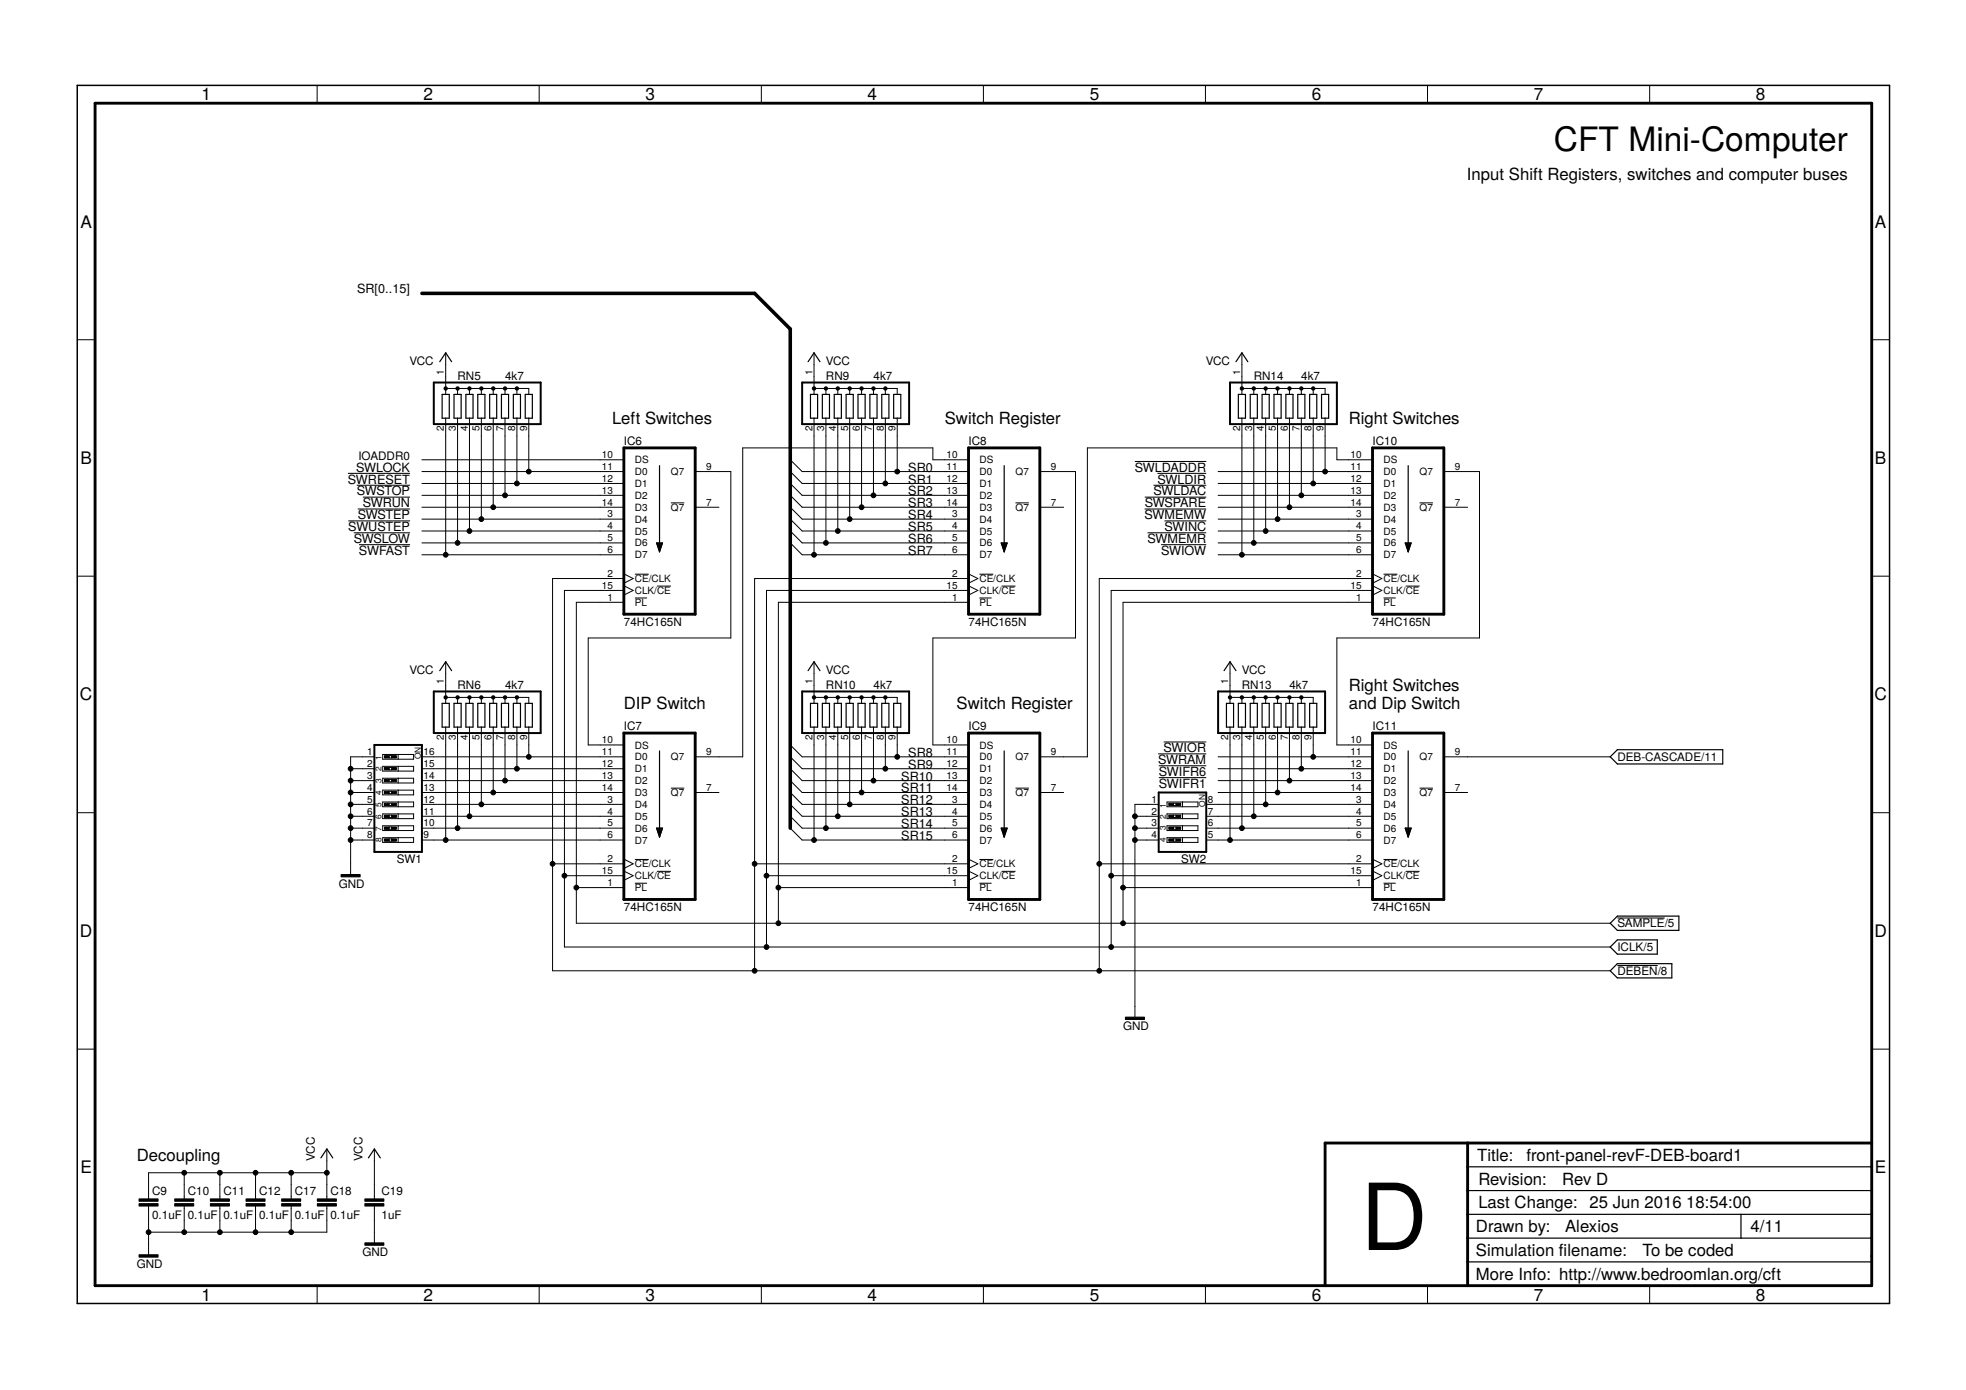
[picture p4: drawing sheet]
<svg xmlns="http://www.w3.org/2000/svg" width="420mm" height="297mm" viewBox="0 0 420 297" stroke-linecap="round" stroke-linejoin="round" font-family="sans-serif">
<defs><g id="words">
<text font-size="19.7" x="290.8" y="267.1">D</text>
<text font-size="7.2" x="332.1" y="32.2">CFT Mini-Computer</text>
<g font-size="3.7">
<text x="43" y="21.4">1</text>
<text x="90.5" y="21.4">2</text>
<text x="138" y="21.4">3</text>
<text x="185.4" y="21.4">4</text>
<text x="232.9" y="21.4">5</text>
<text x="280.3" y="21.4">6</text>
<text x="327.8" y="21.4">7</text>
<text x="375.3" y="21.4">8</text>
<text x="17.2" y="48.6">A</text>
<text x="400.7" y="48.6">A</text>
<text x="17.2" y="99.2">B</text>
<text x="400.7" y="99.2">B</text>
<text x="17.1" y="149.7">C</text>
<text x="400.6" y="149.7">C</text>
<text x="17.1" y="200.2">D</text>
<text x="400.6" y="200.2">D</text>
<text x="17.2" y="250.8">E</text>
<text x="400.7" y="250.8">E</text>
<text x="43" y="277.9">1</text>
<text x="90.5" y="277.9">2</text>
<text x="138" y="277.9">3</text>
<text x="185.4" y="277.9">4</text>
<text x="232.9" y="277.9">5</text>
<text x="280.3" y="277.9">6</text>
<text x="327.8" y="277.9">7</text>
<text x="375.3" y="277.9">8</text>
</g>
<g font-size="3.6">
<text x="313.5" y="38.6">Input Shift Registers, switches and computer buses</text>
<text x="130.8" y="90.6">Left Switches</text>
<text x="201.9" y="90.6">Switch Register</text>
<text x="288.3" y="90.6">Right Switches</text>
<text x="288.3" y="147.8">Right Switches</text>
<text x="133.3" y="151.6">DIP Switch</text>
<text x="204.4" y="151.6">Switch Register</text>
<text x="288.3" y="151.6">and Dip Switch</text>
<text x="29.2" y="248.1">Decoupling</text>
<text x="315.7" y="248.1">Title:</text>
<text x="326.2" y="248.2">front-panel-revF-DEB-board1</text>
<text x="315.9" y="253.2">Revision:</text>
<text x="333.8" y="253.3">Rev D</text>
<text x="315.4" y="263.3">Drawn by:</text>
<text x="315.9" y="258.2">Last Change: 25 Jun 2016</text>
<text x="334.5" y="263.3">Alexios</text>
<text x="360.4" y="258.1">18:54:00</text>
<text x="374.1" y="263.2">4/11</text>
<text x="315.4" y="268.4">Simulation flename:</text>
<text x="333.2" y="268.4">i</text>
<text x="351" y="268.4">To be coded</text>
<text x="315.4" y="273.5">More Info: http://www.bedroomlan.org/cft</text>
</g>
<g font-size="2.7">
<text x="76.3" y="62.7">SR[0..15]</text>
<text x="76.1" y="100.8">SWLOCK</text>
<text x="194.1" y="100.8">SR0</text>
<text x="242.5" y="100.8">SWLDADDR</text>
<text x="74.4" y="103.3">SWRESET</text>
<text x="76.2" y="105.9">SWSTOP</text>
<text x="194.1" y="103.3">SR1</text>
<text x="194.1" y="105.9">SR2</text>
<text x="246.5" y="105.9">SWLDAC</text>
<text x="247.3" y="103.3">SWLDIR</text>
<text x="74.4" y="113.5">SWUSTEP</text>
<text x="76.4" y="110.9">SWSTEP</text>
<text x="77.5" y="108.4">SWRUN</text>
<text x="194.1" y="108.4">SR3</text>
<text x="194.1" y="110.9">SR4</text>
<text x="194.1" y="113.5">SR5</text>
<text x="244.6" y="110.9">SWMEMW</text>
<text x="244.6" y="108.4">SWSPARE</text>
<text x="248.8" y="113.5">SWINC</text>
<text x="75.6" y="116">SWSLOW</text>
<text x="76.7" y="118.6">SWFAST</text>
<text x="194.1" y="116">SR6</text>
<text x="194.1" y="118.6">SR7</text>
<text x="245.2" y="116">SWMEMR</text>
<text x="248.1" y="118.6">SWIOW</text>
<text x="194.1" y="161.7">SR8</text>
<text x="248.7" y="160.7">SWIOR</text>
<text x="192.6" y="166.8">SR10</text>
<text x="194.1" y="164.3">SR9</text>
<text x="247.5" y="163.3">SWRAM</text>
<text x="247.6" y="165.8">SWIFR6</text>
<text x="192.6" y="169.4">SR11</text>
<text x="192.6" y="171.9">SR12</text>
<text x="247.6" y="168.3">SWIFR1</text>
<text x="192.6" y="174.4">SR13</text>
<text x="192.6" y="177">SR14</text>
<text x="192.6" y="179.5">SR15</text>
</g>
<g font-size="2.5">
<text x="87.5" y="77.9">VCC</text>
<text x="176.5" y="77.9">VCC</text>
<text x="257.7" y="77.9">VCC</text>
<text x="97.8" y="81.1">RN5</text>
<text x="107.9" y="81.1">4k7</text>
<text x="176.5" y="81.1">RN9</text>
<text x="186.7" y="81.1">4k7</text>
<text x="267.9" y="81.1">RN14</text>
<text x="278.1" y="81.1">4k7</text>
<text x="133.3" y="95.1">IC6</text>
<text x="207" y="95.1">IC8</text>
<text x="293.3" y="95.1">IC10</text>
<text x="76.6" y="98.2">IOADDR0</text>
<text x="133.3" y="133.8">74HC165N</text>
<text x="207" y="133.8">74HC165N</text>
<text x="293.3" y="133.8">74HC165N</text>
<text x="87.5" y="144">VCC</text>
<text x="176.5" y="144">VCC</text>
<text x="265.4" y="144">VCC</text>
<text x="97.8" y="147.1">RN6</text>
<text x="107.9" y="147.1">4k7</text>
<text x="176.5" y="147.1">RN10</text>
<text x="186.7" y="147.1">4k7</text>
<text x="265.4" y="147.1">RN13</text>
<text x="275.6" y="147.1">4k7</text>
<text x="133.3" y="156">IC7</text>
<text x="207" y="156">IC9</text>
<text x="293.3" y="156">IC11</text>
<text x="345.7" y="162.6">DEB-CASCADE/11</text>
<text x="84.8" y="184.5">SW1</text>
<text x="252.4" y="184.5">SW2</text>
<text x="72.4" y="189.7">GND</text>
<text x="133.3" y="194.7">74HC165N</text>
<text x="207" y="194.7">74HC165N</text>
<text x="293.3" y="194.7">74HC165N</text>
<text x="345.7" y="203.3">ICLK/5</text>
<text x="345.7" y="198.2">SAMPLE/5</text>
<text x="345.7" y="208.3">DEBEN/8</text>
<text x="240" y="220.1">GND</text>
<text x="67.3" y="248.1" transform="rotate(-90 67.3 248.1)">VCC</text>
<text x="77.5" y="248.1" transform="rotate(-90 77.5 248.1)">VCC</text>
<text x="32.5" y="255.3">C9</text>
<text x="40.1" y="255.3">C10</text>
<text x="47.7" y="255.3">C11</text>
<text x="55.4" y="255.3">C12</text>
<text x="63" y="255.3">C17</text>
<text x="70.6" y="255.3">C18</text>
<text x="81.5" y="255.3">C19</text>
<text x="32.5" y="260.4">0.1uF</text>
<text x="40.1" y="260.4">0.1uF</text>
<text x="47.7" y="260.4">0.1uF</text>
<text x="55.4" y="260.4">0.1uF</text>
<text x="63" y="260.4">0.1uF</text>
<text x="70.6" y="260.4">0.1uF</text>
<text x="81.5" y="260.4">1uF</text>
<text x="77.5" y="268.4">GND</text>
<text x="29.2" y="270.9">GND</text>
</g>
<g font-size="2.1">
<text x="94.9" y="80.1" transform="rotate(-90 94.9 80.1)">1</text>
<text x="173.6" y="80.1" transform="rotate(-90 173.6 80.1)">1</text>
<text x="265" y="80.1" transform="rotate(-90 265 80.1)">1</text>
<text x="94.9" y="92.2" transform="rotate(-90 94.9 92.2)">2</text>
<text x="97.4" y="92.2" transform="rotate(-90 97.4 92.2)">3</text>
<text x="100" y="92.2" transform="rotate(-90 100 92.2)">4</text>
<text x="102.5" y="92.2" transform="rotate(-90 102.5 92.2)">5</text>
<text x="105" y="92.2" transform="rotate(-90 105 92.2)">6</text>
<text x="107.6" y="92.2" transform="rotate(-90 107.6 92.2)">7</text>
<text x="110.1" y="92.2" transform="rotate(-90 110.1 92.2)">8</text>
<text x="112.7" y="92.2" transform="rotate(-90 112.7 92.2)">9</text>
<text x="173.6" y="92.2" transform="rotate(-90 173.6 92.2)">2</text>
<text x="176.2" y="92.2" transform="rotate(-90 176.2 92.2)">3</text>
<text x="178.7" y="92.2" transform="rotate(-90 178.7 92.2)">4</text>
<text x="181.2" y="92.2" transform="rotate(-90 181.2 92.2)">5</text>
<text x="183.8" y="92.2" transform="rotate(-90 183.8 92.2)">6</text>
<text x="186.3" y="92.2" transform="rotate(-90 186.3 92.2)">7</text>
<text x="188.9" y="92.2" transform="rotate(-90 188.9 92.2)">8</text>
<text x="191.4" y="92.2" transform="rotate(-90 191.4 92.2)">9</text>
<text x="265" y="92.2" transform="rotate(-90 265 92.2)">2</text>
<text x="267.6" y="92.2" transform="rotate(-90 267.6 92.2)">3</text>
<text x="270.1" y="92.2" transform="rotate(-90 270.1 92.2)">4</text>
<text x="272.7" y="92.2" transform="rotate(-90 272.7 92.2)">5</text>
<text x="275.2" y="92.2" transform="rotate(-90 275.2 92.2)">6</text>
<text x="277.7" y="92.2" transform="rotate(-90 277.7 92.2)">7</text>
<text x="280.3" y="92.2" transform="rotate(-90 280.3 92.2)">8</text>
<text x="282.8" y="92.2" transform="rotate(-90 282.8 92.2)">9</text>
<text x="128.6" y="97.9">10</text>
<text x="128.6" y="100.4">11</text>
<text x="135.7" y="99">DS</text>
<text x="135.7" y="101.5">D0</text>
<text x="143.4" y="101.5">Q7</text>
<text x="150.9" y="100.4">9</text>
<text x="202.3" y="97.9">10</text>
<text x="202.3" y="100.4">11</text>
<text x="209.3" y="99">DS</text>
<text x="209.3" y="101.5">D0</text>
<text x="217" y="101.5">Q7</text>
<text x="224.6" y="100.4">9</text>
<text x="288.6" y="97.9">10</text>
<text x="288.6" y="100.4">11</text>
<text x="295.7" y="99">DS</text>
<text x="295.7" y="101.5">D0</text>
<text x="303.4" y="101.5">Q7</text>
<text x="310.9" y="100.4">9</text>
<text x="128.6" y="103">12</text>
<text x="128.6" y="105.5">13</text>
<text x="135.7" y="104.1">D1</text>
<text x="135.7" y="106.6">D2</text>
<text x="202.3" y="103">12</text>
<text x="202.3" y="105.5">13</text>
<text x="209.3" y="104.1">D1</text>
<text x="209.3" y="106.6">D2</text>
<text x="288.6" y="103">12</text>
<text x="288.6" y="105.5">13</text>
<text x="295.7" y="104.1">D1</text>
<text x="295.7" y="106.6">D2</text>
<text x="128.6" y="108">14</text>
<text x="129.8" y="110.6">3</text>
<text x="129.8" y="113.1">4</text>
<text x="135.7" y="111.7">D4</text>
<text x="135.7" y="109.2">D3</text>
<text x="143.4" y="109.2">Q7</text>
<text x="150.9" y="108">7</text>
<text x="202.3" y="108">14</text>
<text x="203.5" y="110.6">3</text>
<text x="203.5" y="113.1">4</text>
<text x="209.3" y="111.7">D4</text>
<text x="209.3" y="109.2">D3</text>
<text x="217" y="109.2">Q7</text>
<text x="224.6" y="108">7</text>
<text x="288.6" y="108">14</text>
<text x="289.8" y="110.6">3</text>
<text x="289.8" y="113.1">4</text>
<text x="295.7" y="111.7">D4</text>
<text x="295.7" y="109.2">D3</text>
<text x="303.4" y="109.2">Q7</text>
<text x="310.9" y="108">7</text>
<text x="129.8" y="115.7">5</text>
<text x="129.8" y="118.2">6</text>
<text x="135.7" y="114.2">D5</text>
<text x="135.7" y="116.8">D6</text>
<text x="135.7" y="119.3">D7</text>
<text x="203.5" y="115.7">5</text>
<text x="203.5" y="118.2">6</text>
<text x="209.3" y="114.2">D5</text>
<text x="209.3" y="116.8">D6</text>
<text x="209.3" y="119.3">D7</text>
<text x="289.8" y="115.7">5</text>
<text x="289.8" y="118.2">6</text>
<text x="295.7" y="114.2">D5</text>
<text x="295.7" y="116.8">D6</text>
<text x="295.7" y="119.3">D7</text>
<text x="128.6" y="125.8">15</text>
<text x="129.8" y="123.3">2</text>
<text x="135.7" y="124.4">CE/CLK</text>
<text x="202.3" y="125.8">15</text>
<text x="203.5" y="123.3">2</text>
<text x="209.3" y="124.4">CE/CLK</text>
<text x="288.6" y="125.8">15</text>
<text x="289.8" y="123.3">2</text>
<text x="295.7" y="124.4">CE/CLK</text>
<text x="129.8" y="128.4">1</text>
<text x="135.7" y="129.5">PL</text>
<text x="135.7" y="126.9">CLK/CE</text>
<text x="203.5" y="128.4">1</text>
<text x="209.3" y="129.5">PL</text>
<text x="209.3" y="126.9">CLK/CE</text>
<text x="289.8" y="128.4">1</text>
<text x="295.7" y="129.5">PL</text>
<text x="295.7" y="126.9">CLK/CE</text>
<text x="94.9" y="146.1" transform="rotate(-90 94.9 146.1)">1</text>
<text x="173.6" y="146.1" transform="rotate(-90 173.6 146.1)">1</text>
<text x="262.5" y="146.1" transform="rotate(-90 262.5 146.1)">1</text>
<text x="78.5" y="161.4">1</text>
<text x="90.5" y="161.4">16</text>
<text x="94.9" y="158.2" transform="rotate(-90 94.9 158.2)">2</text>
<text x="97.4" y="158.2" transform="rotate(-90 97.4 158.2)">3</text>
<text x="100" y="158.2" transform="rotate(-90 100 158.2)">4</text>
<text x="102.5" y="158.2" transform="rotate(-90 102.5 158.2)">5</text>
<text x="105" y="158.2" transform="rotate(-90 105 158.2)">6</text>
<text x="107.6" y="158.2" transform="rotate(-90 107.6 158.2)">7</text>
<text x="110.1" y="158.2" transform="rotate(-90 110.1 158.2)">8</text>
<text x="112.7" y="158.2" transform="rotate(-90 112.7 158.2)">9</text>
<text x="128.6" y="158.8">10</text>
<text x="128.6" y="161.4">11</text>
<text x="135.7" y="160">DS</text>
<text x="150.9" y="161.4">9</text>
<text x="173.6" y="158.2" transform="rotate(-90 173.6 158.2)">2</text>
<text x="176.2" y="158.2" transform="rotate(-90 176.2 158.2)">3</text>
<text x="178.7" y="158.2" transform="rotate(-90 178.7 158.2)">4</text>
<text x="181.2" y="158.2" transform="rotate(-90 181.2 158.2)">5</text>
<text x="183.8" y="158.2" transform="rotate(-90 183.8 158.2)">6</text>
<text x="186.3" y="158.2" transform="rotate(-90 186.3 158.2)">7</text>
<text x="188.9" y="158.2" transform="rotate(-90 188.9 158.2)">8</text>
<text x="191.4" y="158.2" transform="rotate(-90 191.4 158.2)">9</text>
<text x="202.3" y="158.8">10</text>
<text x="202.3" y="161.4">11</text>
<text x="209.3" y="160">DS</text>
<text x="224.6" y="161.4">9</text>
<text x="262.5" y="158.2" transform="rotate(-90 262.5 158.2)">2</text>
<text x="265" y="158.2" transform="rotate(-90 265 158.2)">3</text>
<text x="267.6" y="158.2" transform="rotate(-90 267.6 158.2)">4</text>
<text x="270.1" y="158.2" transform="rotate(-90 270.1 158.2)">5</text>
<text x="272.7" y="158.2" transform="rotate(-90 272.7 158.2)">6</text>
<text x="275.2" y="158.2" transform="rotate(-90 275.2 158.2)">7</text>
<text x="277.7" y="158.2" transform="rotate(-90 277.7 158.2)">8</text>
<text x="280.3" y="158.2" transform="rotate(-90 280.3 158.2)">9</text>
<text x="288.6" y="158.8">10</text>
<text x="288.6" y="161.4">11</text>
<text x="295.7" y="160">DS</text>
<text x="310.9" y="161.4">9</text>
<text x="78.5" y="163.9">2</text>
<text x="78.5" y="166.5">3</text>
<text x="90.5" y="166.5">14</text>
<text x="90.5" y="163.9">15</text>
<text x="128.6" y="163.9">12</text>
<text x="128.6" y="166.5">13</text>
<text x="135.7" y="162.5">D0</text>
<text x="135.7" y="165">D1</text>
<text x="135.7" y="167.6">D2</text>
<text x="143.4" y="162.5">Q7</text>
<text x="202.3" y="163.9">12</text>
<text x="202.3" y="166.5">13</text>
<text x="209.3" y="162.5">D0</text>
<text x="209.3" y="165">D1</text>
<text x="209.3" y="167.6">D2</text>
<text x="217" y="162.5">Q7</text>
<text x="288.6" y="163.9">12</text>
<text x="288.6" y="166.5">13</text>
<text x="295.7" y="162.5">D0</text>
<text x="295.7" y="165">D1</text>
<text x="295.7" y="167.6">D2</text>
<text x="303.4" y="162.5">Q7</text>
<text x="78.5" y="169">4</text>
<text x="78.5" y="171.5">5</text>
<text x="90.5" y="171.5">12</text>
<text x="90.5" y="169">13</text>
<text x="128.6" y="169">14</text>
<text x="129.8" y="171.5">3</text>
<text x="135.7" y="172.7">D4</text>
<text x="135.7" y="170.1">D3</text>
<text x="143.4" y="170.1">Q7</text>
<text x="150.9" y="169">7</text>
<text x="202.3" y="169">14</text>
<text x="203.5" y="171.5">3</text>
<text x="209.3" y="172.7">D4</text>
<text x="209.3" y="170.1">D3</text>
<text x="217" y="170.1">Q7</text>
<text x="224.6" y="169">7</text>
<text x="246.1" y="171.5">1</text>
<text x="258.1" y="171.5">8</text>
<text x="288.6" y="169">14</text>
<text x="289.8" y="171.5">3</text>
<text x="295.7" y="172.7">D4</text>
<text x="295.7" y="170.1">D3</text>
<text x="303.4" y="170.1">Q7</text>
<text x="310.9" y="169">7</text>
<text x="78.5" y="174.1">6</text>
<text x="78.5" y="176.6">7</text>
<text x="78.5" y="179.2">8</text>
<text x="90.5" y="179.2">9</text>
<text x="90.5" y="176.6">10</text>
<text x="90.5" y="174.1">11</text>
<text x="129.8" y="174.1">4</text>
<text x="129.8" y="176.6">5</text>
<text x="129.8" y="179.2">6</text>
<text x="135.7" y="175.2">D5</text>
<text x="135.7" y="177.7">D6</text>
<text x="203.5" y="174.1">4</text>
<text x="203.5" y="176.6">5</text>
<text x="203.5" y="179.2">6</text>
<text x="209.3" y="175.2">D5</text>
<text x="209.3" y="177.7">D6</text>
<text x="246.1" y="174.1">2</text>
<text x="246.1" y="176.6">3</text>
<text x="246.1" y="179.2">4</text>
<text x="258.1" y="179.2">5</text>
<text x="258.1" y="176.6">6</text>
<text x="258.1" y="174.1">7</text>
<text x="289.8" y="174.1">4</text>
<text x="289.8" y="176.6">5</text>
<text x="289.8" y="179.2">6</text>
<text x="295.7" y="175.2">D5</text>
<text x="295.7" y="177.7">D6</text>
<text x="129.8" y="184.2">2</text>
<text x="135.7" y="185.4">CE/CLK</text>
<text x="135.7" y="180.3">D7</text>
<text x="203.5" y="184.2">2</text>
<text x="209.3" y="185.4">CE/CLK</text>
<text x="209.3" y="180.3">D7</text>
<text x="289.8" y="184.2">2</text>
<text x="295.7" y="185.4">CE/CLK</text>
<text x="295.7" y="180.3">D7</text>
<text x="128.6" y="186.8">15</text>
<text x="129.8" y="189.3">1</text>
<text x="135.7" y="190.4">PL</text>
<text x="135.7" y="187.9">CLK/CE</text>
<text x="202.3" y="186.8">15</text>
<text x="203.5" y="189.3">1</text>
<text x="209.3" y="190.4">PL</text>
<text x="209.3" y="187.9">CLK/CE</text>
<text x="288.6" y="186.8">15</text>
<text x="289.8" y="189.3">1</text>
<text x="295.7" y="190.4">PL</text>
<text x="295.7" y="187.9">CLK/CE</text>
</g>
<g font-size="1.8">
<text x="81.5" y="167.3" transform="rotate(-90 81.5 167.3)">3</text>
<text x="81.5" y="164.8" transform="rotate(-90 81.5 164.8)">2</text>
<text x="81.5" y="162.5" transform="rotate(-90 81.5 162.5)">1</text>
<text x="89.9" y="162.2" transform="rotate(-90 89.9 162.2)">ON</text>
<text x="81.5" y="172.5" transform="rotate(-90 81.5 172.5)">5</text>
<text x="81.5" y="169.8" transform="rotate(-90 81.5 169.8)">4</text>
<text x="249.1" y="172.6" transform="rotate(-90 249.1 172.6)">1</text>
<text x="257.5" y="172.4" transform="rotate(-90 257.5 172.4)">ON</text>
<text x="81.5" y="180" transform="rotate(-90 81.5 180)">8</text>
<text x="81.5" y="177.6" transform="rotate(-90 81.5 177.6)">7</text>
<text x="81.5" y="175" transform="rotate(-90 81.5 175)">6</text>
<text x="249.1" y="180" transform="rotate(-90 249.1 180)">4</text>
<text x="249.1" y="177.5" transform="rotate(-90 249.1 177.5)">3</text>
<text x="249.1" y="174.9" transform="rotate(-90 249.1 174.9)">2</text>
</g>
</g></defs>
<g fill="none" stroke="#000" stroke-width=".21">
<path d="M67.8 18.2v3.9M115.2 18.2v3.9M162.7 18.2v3.9M210.2 18.2v3.9M257.6 18.2v3.9M305.1 18.2v3.9M352.6 18.2v3.9M20.3 22.1h379.7v252.6h-379.7zM16.5 72.6h3.8M95.2 75.4v8.9M174 75.4v8.9M265.4 75.4v8.9"/>
<path d="M400 72.6h3.8M90.2 98.3h43.1M95.2 89.4v29.2M95.2 83h17.8v1.3M97.8 83v1.3M97.8 89.4v26.6M100.3 83v1.3M100.3 89.4v24.1M102.9 83v1.3M102.9 89.4v21.5M105.4 83v1.3M105.4 89.4v19"/>
<path d="M107.9 83v1.3M107.9 89.4v16.5M110.5 83v1.3M110.5 89.4v13.9M113 89.4v11.4M168.9 98.3l2.5 2.5h35.6M174 83h17.7v1.3M174 89.4v29.2M176.5 83v1.3M176.5 89.4v26.6M179 83v1.3M179 89.4v24.1"/>
<path d="M181.6 83v1.3M181.6 89.4v21.5M184.1 83v1.3M184.1 89.4v19M186.7 83v1.3M186.7 89.4v16.5M189.2 83v1.3M189.2 89.4v13.9M191.7 89.4v11.4M207 98.3h-7.6v-2.6h-40.7v66h-10.1M242.5 98.6h15.3M265.4 83h17.8v1.3"/>
<path d="M265.4 89.4v29.2M267.9 83v1.3M267.9 89.4v26.6M270.5 83v1.3M270.5 89.4v24.1M273 83v1.3M273 89.4v21.5M275.6 83v1.3M275.6 89.4v19M278.1 83v1.3M278.1 89.4v16.5M280.6 83v1.3"/>
<path d="M280.6 89.4v13.9M283.2 89.4v11.4M293.3 98.3h-7.6v-2.6h-53.3v66h-10.2M74.4 101.2h13.2M74.4 111.3h13.2M75.6 113.9h12M76.2 103.7h11.4M76.5 108.8h11.1M76.7 116.4h10.9M77.6 106.2h10M90.2 110.9h43.1M90.2 113.5h43.1"/>
<path d="M90.2 116h43.1M90.2 118.6h43.1M90.2 108.4h43.1M90.2 100.8h43.1M90.2 103.3h43.1M90.2 105.9h43.1M143.4 107.5h2.8M148.6 108.4h5M148.6 100.8h7.6v35.5h-30.5v22.9h7.6M168.9 108.4l2.5 2.5h35.6M168.9 110.9l2.5 2.6h35.6M168.9 113.5l2.5 2.5h35.6"/>
<path d="M168.9 116l2.5 2.6h35.6M168.9 105.9l2.5 2.5h35.6M168.9 100.8l2.5 2.5h35.6M168.9 103.3l2.5 2.6h35.6M217 107.5h2.9M222.2 108.4h5.1M222.2 100.8h7.6v35.5h-30.4v22.9h7.6M244.6 108.8h13.2M244.6 106.2h13.2M245.2 113.9h12.6M246.5 103.7h11.3M247.4 101.2h10.4"/>
<path d="M248.1 116.4h9.7M248.9 111.3h8.9M260.3 110.9h33M260.3 113.5h33M260.3 116h33M260.3 118.6h33M260.3 108.4h33M260.3 100.8h33M260.3 103.3h33M260.3 105.9h33M303.4 107.5h2.8M308.6 108.4h5"/>
<path d="M308.6 100.8h7.6v35.5h-30.5v22.9h7.6M16.5 123.1h3.8M133.3 128.7h-10.1v68.6h220.9M133.3 122.6l2 1-2 1M133.3 123.6h-15.2v83.9h226M133.3 125.2l2 1-2 1M133.3 126.2h-12.7v76.2h223.5M135.7 127.8h2.6M135.7 122.7h2.9M140.4 125.2h3M207 128.7h-40.7v68.6M207 123.6h-45.7v83.9"/>
<path d="M207 126.2h-43.2v76.2M207 122.6l2 1-2 1M207 125.2l2 1-2 1M209.3 127.8h2.6M209.3 122.7h3M214.1 125.2h2.9M293.3 128.7h-53.3v68.6M293.3 123.6h-58.4v83.9M293.3 126.2h-55.8v76.2M293.3 122.6l2 1-2 1M293.3 125.2l2 1-2 1M295.7 127.8h2.6"/>
<path d="M295.7 122.7h2.9M300.4 125.2h3M400 123.1h3.8M95.2 141.4v8.9M95.2 155.4v24.1M95.2 149h17.8v1.3M97.8 149v1.3M97.8 155.4v21.6M100.3 149v1.3M100.3 155.4v19M102.9 149v1.3M102.9 155.4v16.5"/>
<path d="M105.4 149v1.3M105.4 155.4v14M107.9 149v1.3M107.9 155.4v11.4M110.5 149v1.3M110.5 155.4v8.9M113 155.4v6.3M168.9 159.2l2.5 2.5h35.6M174 149h17.7v1.3M174 141.4v8.9M174 155.4v24.1M176.5 149v1.3"/>
<path d="M176.5 155.4v21.6M179 149v1.3M179 155.4v19M181.6 149v1.3M181.6 155.4v16.5M184.1 149v1.3M184.1 155.4v14M186.7 149v1.3M186.7 155.4v11.4M189.2 149v1.3M189.2 155.4v8.9M191.7 155.4v6.3"/>
<path d="M248.7 158.6h9.1M262.9 149h17.7v1.3M262.9 141.4v8.9M262.9 155.4v24.1M265.4 149v1.3M265.4 155.4v21.6M267.9 149v1.3M267.9 155.4v19M270.5 149v1.3M270.5 155.4v16.5M273 149v1.3M273 155.4v14"/>
<path d="M275.6 149v1.3M275.6 155.4v11.4M278.1 149v1.3M278.1 155.4v8.9M280.6 155.4v6.3M16.5 173.7h3.8M74.9 171.9h5.1M74.9 174.4h5.1M74.9 177h5.1M74.9 179.5h5.1M74.9 169.4h5.1M74.9 164.3h5.1"/>
<path d="M74.9 166.8h5.1M80 161.7h-5.1v25.4M81.8 179h6.6v1h-6.6zM81.8 161.2h6.6v1h-6.6zM81.8 163.8h6.6v1h-6.6zM81.8 166.3h6.6v1h-6.6zM81.8 168.8h6.6v1.1h-6.6zM81.8 171.4h6.6v1h-6.6zM81.8 173.9h6.6v1h-6.6zM81.8 176.5h6.6v1h-6.6zM83.2 179.8h.5M83.2 179.3h.5"/>
<path d="M83.2 177.2h.5M83.2 176.7h.5M83.2 174.7h.5M83.2 174.2h.5M83.2 172.1h.5M83.2 171.6h.5M83.2 169.6h.5M83.2 169.1h.5M83.2 167.1h.5M83.2 166.6h.5M83.2 164.5h.5M83.2 164h.5"/>
<path d="M83.2 162h.5M83.2 161.5h.5M85.1 161.2v1M85.1 163.8v1M85.1 166.3v1M85.1 168.8v1.1M85.1 171.4v1M85.1 173.9v1M85.1 176.5v1M85.1 179v1M90.2 171.9h43.1M90.2 174.4h43.1"/>
<path d="M90.2 177h43.1M90.2 179.5h43.1M90.2 169.4h43.1M90.2 161.7h43.1M90.2 164.3h43.1M90.2 166.8h43.1M143.4 168.4h2.8M148.6 169.4h5M168.9 169.4l2.5 2.5h35.6M168.9 171.9l2.5 2.5h35.6M168.9 174.4l2.5 2.6h35.6M168.9 177l2.5 2.5h35.6"/>
<path d="M168.9 166.8l2.5 2.6h35.6M168.9 161.7l2.5 2.6h35.6M168.9 164.3l2.5 2.5h35.6M217 168.4h2.9M222.2 169.4h5.1M242.5 174.4h5.1M242.5 177h5.1M242.5 179.5h5.1M247.5 161.1h10.3M247.6 171.9h-5.1v45.7M247.6 166.2h10.2M247.6 163.6h10.2"/>
<path d="M249.4 179h6.6v1h-6.6zM249.4 176.5h6.6v1h-6.6zM249.4 173.9h6.6v1h-6.6zM249.4 171.4h6.6v1h-6.6zM250.8 179.8h.5M250.8 179.3h.5M250.8 177.2h.5M250.8 176.7h.5M250.8 174.7h.5M250.8 174.2h.5M250.8 172.1h.5M250.8 171.6h.5"/>
<path d="M252.7 171.4v1M252.7 173.9v1M252.7 176.5v1M252.7 179v1M257.8 171.9h35.5M257.8 174.4h35.5M257.8 177h35.5M257.8 179.5h35.5M260.3 169.4h33M260.3 161.7h33M260.3 164.3h33M260.3 166.8h33"/>
<path d="M303.4 168.4h2.8M308.6 169.4h5M308.6 161.7h35.5M400 173.7h3.8M118.1 184.6h15.2M120.6 187.1h12.7M123.2 189.7h10.1M133.3 183.6l2 1-2 1M133.3 186.1l2 1-2 1M135.7 188.7h2.6M135.7 183.7h2.9M140.4 186.2h3"/>
<path d="M161.3 184.6h45.7M163.8 187.1h43.2M166.3 189.7h40.7M207 183.6l2 1-2 1M207 186.1l2 1-2 1M209.3 188.7h2.6M209.3 183.7h3M214.1 186.2h2.9M234.9 184.6h58.4M237.5 187.1h55.8M240 189.7h53.3M293.3 183.6l2 1-2 1"/>
<path d="M293.3 186.1l2 1-2 1M295.7 188.7h2.6M295.7 183.7h2.9M300.4 186.2h3M345.7 196.2h10.1M345.7 206.3h8.6M16.5 224.2h3.8M400 224.2h3.8M31.7 257.7v10.7M39.4 250.6v5.6M39.4 257.7v5.6M47 250.6v5.6"/>
<path d="M47 257.7v5.6M54.6 250.6v5.6M54.6 257.7v5.6M62.2 250.6v5.6M62.2 257.7v5.6M69.8 245.5v10.7M69.8 257.7v5.6h-38.1M69.8 250.6h-38.1v5.6M80 245.5v10.7M80 257.7v8.2M67.8 274.7v3.9M115.2 274.7v3.9"/>
<path d="M162.7 274.7v3.9M210.2 274.7v3.9M257.6 274.7v3.9M305.1 274.7v3.9M352.6 274.7v3.9M400 274.6h.1"/>
</g>
<g fill="none" stroke="#000" stroke-width=".25">
<path d="M94 77.3l1.2-1.9 1.3 1.9M172.7 77.3l1.3-1.9 1.2 1.9M264.1 77.3l1.3-1.9 1.3 1.9M94.5 84.3h1.5v5.1h-1.5zM97 84.3h1.6v5.1h-1.6zM99.6 84.3h1.5v5.1h-1.5zM102.1 84.3h1.5v5.1h-1.5zM104.6 84.3h1.6v5.1h-1.6zM107.2 84.3h1.5v5.1h-1.5zM109.7 84.3h1.5v5.1h-1.5zM112.2 84.3h1.6v5.1h-1.6zM140.9 99.5v18.4"/>
<path d="M173.2 84.3h1.5v5.1h-1.5zM175.7 84.3h1.6v5.1h-1.6zM178.3 84.3h1.5v5.1h-1.5zM180.8 84.3h1.6v5.1h-1.6zM183.4 84.3h1.5v5.1h-1.5zM185.9 84.3h1.5v5.1h-1.5zM188.4 84.3h1.6v5.1h-1.6zM191 84.3h1.5v5.1h-1.5zM214.6 99.5v18.4M264.6 84.3h1.6v5.1h-1.6zM267.2 84.3h1.5v5.1h-1.5zM269.7 84.3h1.6v5.1h-1.6z"/>
<path d="M272.3 84.3h1.5v5.1h-1.5zM274.8 84.3h1.5v5.1h-1.5zM277.3 84.3h1.6v5.1h-1.6zM279.9 84.3h1.5v5.1h-1.5zM282.4 84.3h1.6v5.1h-1.6zM300.9 99.5v18.4M140.3 116h1.3l-.7 1.9zM140.4 116.1h1.2M140.4 116.3h1.1M140.5 116.6h.9M140.6 116.8h.7M140.7 117h.6"/>
<path d="M140.7 117.2h.5M140.8 117.5h.3M140.9 117.7h.1M140.9 117.9h.1M214 116h1.2l-.6 1.9zM214 116.1h1.2M214.1 116.3h1M214.1 116.6h1M214.2 116.8h.8M214.3 117h.6M214.4 117.2h.4M214.4 117.5h.4"/>
<path d="M214.5 117.7h.2M214.6 117.9h.1M300.3 116h1.3l-.7 1.9zM300.4 116.1h1.2M300.4 116.3h1.1M300.5 116.6h.9M300.6 116.8h.7M300.7 117h.6M300.7 117.2h.5M300.8 117.5h.3M300.9 117.7h.1M300.9 117.9h.1"/>
<path d="M94 143.3l1.2-1.9 1.3 1.9M94.5 150.3h1.5v5.1h-1.5zM97 150.3h1.6v5.1h-1.6zM99.6 150.3h1.5v5.1h-1.5zM102.1 150.3h1.5v5.1h-1.5zM104.6 150.3h1.6v5.1h-1.6zM107.2 150.3h1.5v5.1h-1.5zM109.7 150.3h1.5v5.1h-1.5zM112.2 150.3h1.6v5.1h-1.6zM172.7 143.3l1.3-1.9 1.2 1.9M173.2 150.3h1.5v5.1h-1.5zM175.7 150.3h1.6v5.1h-1.6z"/>
<path d="M178.3 150.3h1.5v5.1h-1.5zM180.8 150.3h1.6v5.1h-1.6zM183.4 150.3h1.5v5.1h-1.5zM185.9 150.3h1.5v5.1h-1.5zM188.4 150.3h1.6v5.1h-1.6zM191 150.3h1.5v5.1h-1.5zM261.6 143.3l1.3-1.9 1.2 1.9M262.1 150.3h1.5v5.1h-1.5zM264.6 150.3h1.6v5.1h-1.6zM267.2 150.3h1.5v5.1h-1.5zM269.7 150.3h1.6v5.1h-1.6zM272.3 150.3h1.5v5.1h-1.5z"/>
<path d="M274.8 150.3h1.5v5.1h-1.5zM277.3 150.3h1.6v5.1h-1.6zM279.9 150.3h1.5v5.1h-1.5zM140.3 177h1.3l-.7 1.9zM140.3 177h1.3M140.4 177.2h1.1M140.5 177.4h.9M140.5 177.7h.9M140.6 177.9h.7M140.7 178.1h.5M140.8 178.3h.3M140.8 178.6h.3"/>
<path d="M140.9 178.8h.1M140.9 160.5v18.4M214 177h1.2l-.6 1.9zM214 177h1.2M214.1 177.2h1.1M214.1 177.4h1M214.2 177.7h.8M214.3 177.9h.6M214.4 178.1h.5M214.4 178.3h.4M214.5 178.6h.2M214.6 178.8h.1"/>
<path d="M214.6 160.5v18.4M300.3 177h1.3l-.7 1.9zM300.3 177h1.3M300.4 177.2h1.1M300.5 177.4h.9M300.5 177.7h.8M300.6 177.9h.7M300.7 178.1h.5M300.8 178.3h.3M300.8 178.6h.3M300.9 178.8h.1M300.9 160.5v18.4"/>
<path d="M344.1 161.7l1.6-1.5h22.5v3.1h-22.5zM73 187.1h3.8M344.1 197.3l1.6-1.5h13.1v3h-13.1zM240.6 217.6h3.9M344.1 202.4l1.6-1.5h8.5v3h-8.5zM344.1 207.5l1.6-1.6h11.6v3.1h-11.6zM68.6 247.4l1.2-1.9 1.3 1.9M78.7 247.4l1.3-1.9 1.3 1.9M313.6 249.3h86.4M313.6 254.4h86.4M313.6 259.5h86.4M372.1 259.5v5.1"/>
<path d="M29.8 268.4h3.9M78.1 265.9h3.8M313.6 264.6h86.4M400 268.4v1.3h-86.4"/>
</g>
<path d="M20.3 22.1h379.7v252.6h-379.7zM133.3 95.7h15.3v35.6h-15.3zM207 95.7h15.2v35.6h-15.2zM293.3 95.7h15.3v35.6h-15.3zM133.3 156.7h15.3v35.5h-15.3zM207 156.7h15.2v35.5h-15.2zM293.3 156.7h15.3v35.5h-15.3zM313.6 244.3v30.4M400 244.3h-116.8v30.4" fill="none" stroke="#000" stroke-width=".61"/>
<path d="M16.5 18.2h387.3v260.4h-387.3z" fill="none" stroke="#000" stroke-width=".32"/>
<g fill="none" stroke="#000" stroke-width=".42">
<path d="M92.7 81.7h22.8v8.9h-22.8zM171.4 81.7h22.9v8.9h-22.9zM262.9 81.7h22.8v8.9h-22.8zM80 159.2h10.2v22.9h-10.2zM92.7 147.8h22.8v8.9h-22.8zM171.4 147.8h22.9v8.9h-22.9zM260.3 147.8h22.9v8.9h-22.9zM247.6 169.4h10.2v12.7h-10.2z"/>
<circle cx="95.2" cy="83" r=".25"/>
<circle cx="97.8" cy="83" r=".25"/>
<circle cx="100.3" cy="83" r=".25"/>
<circle cx="102.9" cy="83" r=".25"/>
<circle cx="105.4" cy="83" r=".25"/>
<circle cx="107.9" cy="83" r=".25"/>
<circle cx="110.5" cy="83" r=".25"/>
<circle cx="174" cy="83" r=".25"/>
<circle cx="176.5" cy="83" r=".25"/>
<circle cx="179" cy="83" r=".25"/>
<circle cx="181.6" cy="83" r=".25"/>
<circle cx="184.1" cy="83" r=".25"/>
<circle cx="186.7" cy="83" r=".25"/>
<circle cx="189.2" cy="83" r=".25"/>
<circle cx="265.4" cy="83" r=".25"/>
<circle cx="267.9" cy="83" r=".25"/>
<circle cx="270.5" cy="83" r=".25"/>
<circle cx="273" cy="83" r=".25"/>
<circle cx="275.6" cy="83" r=".25"/>
<circle cx="278.1" cy="83" r=".25"/>
<circle cx="280.6" cy="83" r=".25"/>
<circle cx="95.2" cy="149" r=".25"/>
<circle cx="97.8" cy="149" r=".25"/>
<circle cx="100.3" cy="149" r=".25"/>
<circle cx="102.9" cy="149" r=".25"/>
<circle cx="105.4" cy="149" r=".25"/>
<circle cx="107.9" cy="149" r=".25"/>
<circle cx="110.5" cy="149" r=".25"/>
<circle cx="174" cy="149" r=".25"/>
<circle cx="176.5" cy="149" r=".25"/>
<circle cx="179" cy="149" r=".25"/>
<circle cx="181.6" cy="149" r=".25"/>
<circle cx="184.1" cy="149" r=".25"/>
<circle cx="186.7" cy="149" r=".25"/>
<circle cx="189.2" cy="149" r=".25"/>
<circle cx="262.9" cy="149" r=".25"/>
<circle cx="265.4" cy="149" r=".25"/>
<circle cx="267.9" cy="149" r=".25"/>
<circle cx="270.5" cy="149" r=".25"/>
<circle cx="273" cy="149" r=".25"/>
<circle cx="275.6" cy="149" r=".25"/>
<circle cx="278.1" cy="149" r=".25"/>
</g>
<g fill="#000" stroke="#000" stroke-width=".21">
<path d="M82.2 179.3h1v.5h-1zM82.2 176.7h1v.5h-1zM82.2 174.2h1v.5h-1zM82.2 171.6h1v.5h-1zM82.2 169.1h1v.5h-1zM82.2 166.6h1v.5h-1zM82.2 164h1v.5h-1zM82.2 161.5h1v.5h-1zM83.7 179.3h1v.5h-1zM83.7 176.7h1v.5h-1zM83.7 174.2h1v.5h-1zM83.7 171.6h1v.5h-1z"/>
<path d="M83.7 169.1h1v.5h-1zM83.7 166.6h1v.5h-1zM83.7 164h1v.5h-1zM83.7 161.5h1v.5h-1zM249.8 179.3h1v.5h-1zM249.8 176.7h1v.5h-1zM249.8 174.2h1v.5h-1zM249.8 171.6h1v.5h-1zM251.3 179.3h1v.5h-1zM251.3 176.7h1v.5h-1zM251.3 174.2h1v.5h-1zM251.3 171.6h1v.5h-1z"/>
<path d="M72.9 186.9h4.1v.5h-4.1zM240.5 217.4h4.1v.5h-4.1zM29.7 256.2h4.1v.5h-4.1zM29.7 257.2h4.1v.5h-4.1zM37.3 256.2h4.1v.5h-4.1zM37.3 257.2h4.1v.5h-4.1zM45 256.2h4v.5h-4zM45 257.2h4v.5h-4zM52.6 256.2h4v.5h-4zM52.6 257.2h4v.5h-4zM60.2 256.2h4.1v.5h-4.1zM60.2 257.2h4.1v.5h-4.1z"/>
<path d="M67.8 256.2h4.1v.5h-4.1zM67.8 257.2h4.1v.5h-4.1zM78 257.2h4v.5h-4zM78 256.2h4v.5h-4zM29.7 268.1h4.1v.5h-4.1zM78 265.6h4v.5h-4z"/>
</g>
<path d="M90.2 62.7h71.1l7.6 7.6v106.7" fill="none" stroke="#000" stroke-width=".76"/>
<g fill="#000" stroke="#000" stroke-width=".21">
<circle cx="95.2" cy="118.6" r=".51"/>
<circle cx="97.8" cy="116" r=".51"/>
<circle cx="100.3" cy="113.5" r=".51"/>
<circle cx="102.9" cy="110.9" r=".51"/>
<circle cx="105.4" cy="108.4" r=".51"/>
<circle cx="107.9" cy="105.9" r=".51"/>
<circle cx="110.5" cy="103.3" r=".51"/>
<circle cx="113" cy="100.8" r=".51"/>
<circle cx="174" cy="118.6" r=".51"/>
<circle cx="176.5" cy="116" r=".51"/>
<circle cx="179" cy="113.5" r=".51"/>
<circle cx="181.6" cy="110.9" r=".51"/>
<circle cx="184.1" cy="108.4" r=".51"/>
<circle cx="186.7" cy="105.9" r=".51"/>
<circle cx="189.2" cy="103.3" r=".51"/>
<circle cx="191.7" cy="100.8" r=".51"/>
<circle cx="265.4" cy="118.6" r=".51"/>
<circle cx="267.9" cy="116" r=".51"/>
<circle cx="270.5" cy="113.5" r=".51"/>
<circle cx="273" cy="110.9" r=".51"/>
<circle cx="275.6" cy="108.4" r=".51"/>
<circle cx="278.1" cy="105.9" r=".51"/>
<circle cx="280.6" cy="103.3" r=".51"/>
<circle cx="283.2" cy="100.8" r=".51"/>
<circle cx="74.9" cy="169.4" r=".51"/>
<circle cx="74.9" cy="177" r=".51"/>
<circle cx="74.9" cy="174.4" r=".51"/>
<circle cx="74.9" cy="171.9" r=".51"/>
<circle cx="74.9" cy="166.8" r=".51"/>
<circle cx="74.9" cy="164.3" r=".51"/>
<circle cx="74.9" cy="179.5" r=".51"/>
<circle cx="95.2" cy="179.5" r=".51"/>
<circle cx="97.8" cy="177" r=".51"/>
<circle cx="100.3" cy="174.4" r=".51"/>
<circle cx="102.9" cy="171.9" r=".51"/>
<circle cx="105.4" cy="169.4" r=".51"/>
<circle cx="107.9" cy="166.8" r=".51"/>
<circle cx="110.5" cy="164.3" r=".51"/>
<circle cx="113" cy="161.7" r=".51"/>
<circle cx="174" cy="179.5" r=".51"/>
<circle cx="176.5" cy="177" r=".51"/>
<circle cx="179" cy="174.4" r=".51"/>
<circle cx="181.6" cy="171.9" r=".51"/>
<circle cx="184.1" cy="169.4" r=".51"/>
<circle cx="186.7" cy="166.8" r=".51"/>
<circle cx="189.2" cy="164.3" r=".51"/>
<circle cx="191.7" cy="161.7" r=".51"/>
<circle cx="242.5" cy="179.5" r=".51"/>
<circle cx="242.5" cy="177" r=".51"/>
<circle cx="242.5" cy="174.4" r=".51"/>
<circle cx="262.9" cy="179.5" r=".51"/>
<circle cx="265.4" cy="177" r=".51"/>
<circle cx="267.9" cy="174.4" r=".51"/>
<circle cx="270.5" cy="171.9" r=".51"/>
<circle cx="273" cy="169.4" r=".51"/>
<circle cx="275.6" cy="166.8" r=".51"/>
<circle cx="278.1" cy="164.3" r=".51"/>
<circle cx="280.6" cy="161.7" r=".51"/>
<circle cx="118.1" cy="184.6" r=".51"/>
<circle cx="120.6" cy="187.1" r=".51"/>
<circle cx="123.2" cy="189.7" r=".51"/>
<circle cx="161.3" cy="184.6" r=".51"/>
<circle cx="163.8" cy="187.1" r=".51"/>
<circle cx="166.3" cy="189.7" r=".51"/>
<circle cx="166.3" cy="197.3" r=".51"/>
<circle cx="234.9" cy="184.6" r=".51"/>
<circle cx="237.5" cy="187.1" r=".51"/>
<circle cx="240" cy="197.3" r=".51"/>
<circle cx="240" cy="189.7" r=".51"/>
<circle cx="161.3" cy="207.5" r=".51"/>
<circle cx="163.8" cy="202.4" r=".51"/>
<circle cx="234.9" cy="207.5" r=".51"/>
<circle cx="237.5" cy="202.4" r=".51"/>
<circle cx="39.4" cy="250.6" r=".51"/>
<circle cx="47" cy="250.6" r=".51"/>
<circle cx="54.6" cy="250.6" r=".51"/>
<circle cx="62.2" cy="250.6" r=".51"/>
<circle cx="69.8" cy="250.6" r=".51"/>
<circle cx="31.7" cy="263.3" r=".51"/>
<circle cx="39.4" cy="263.3" r=".51"/>
<circle cx="47" cy="263.3" r=".51"/>
<circle cx="54.6" cy="263.3" r=".51"/>
<circle cx="62.2" cy="263.3" r=".51"/>
</g>
<use href="#words"/>
</svg>
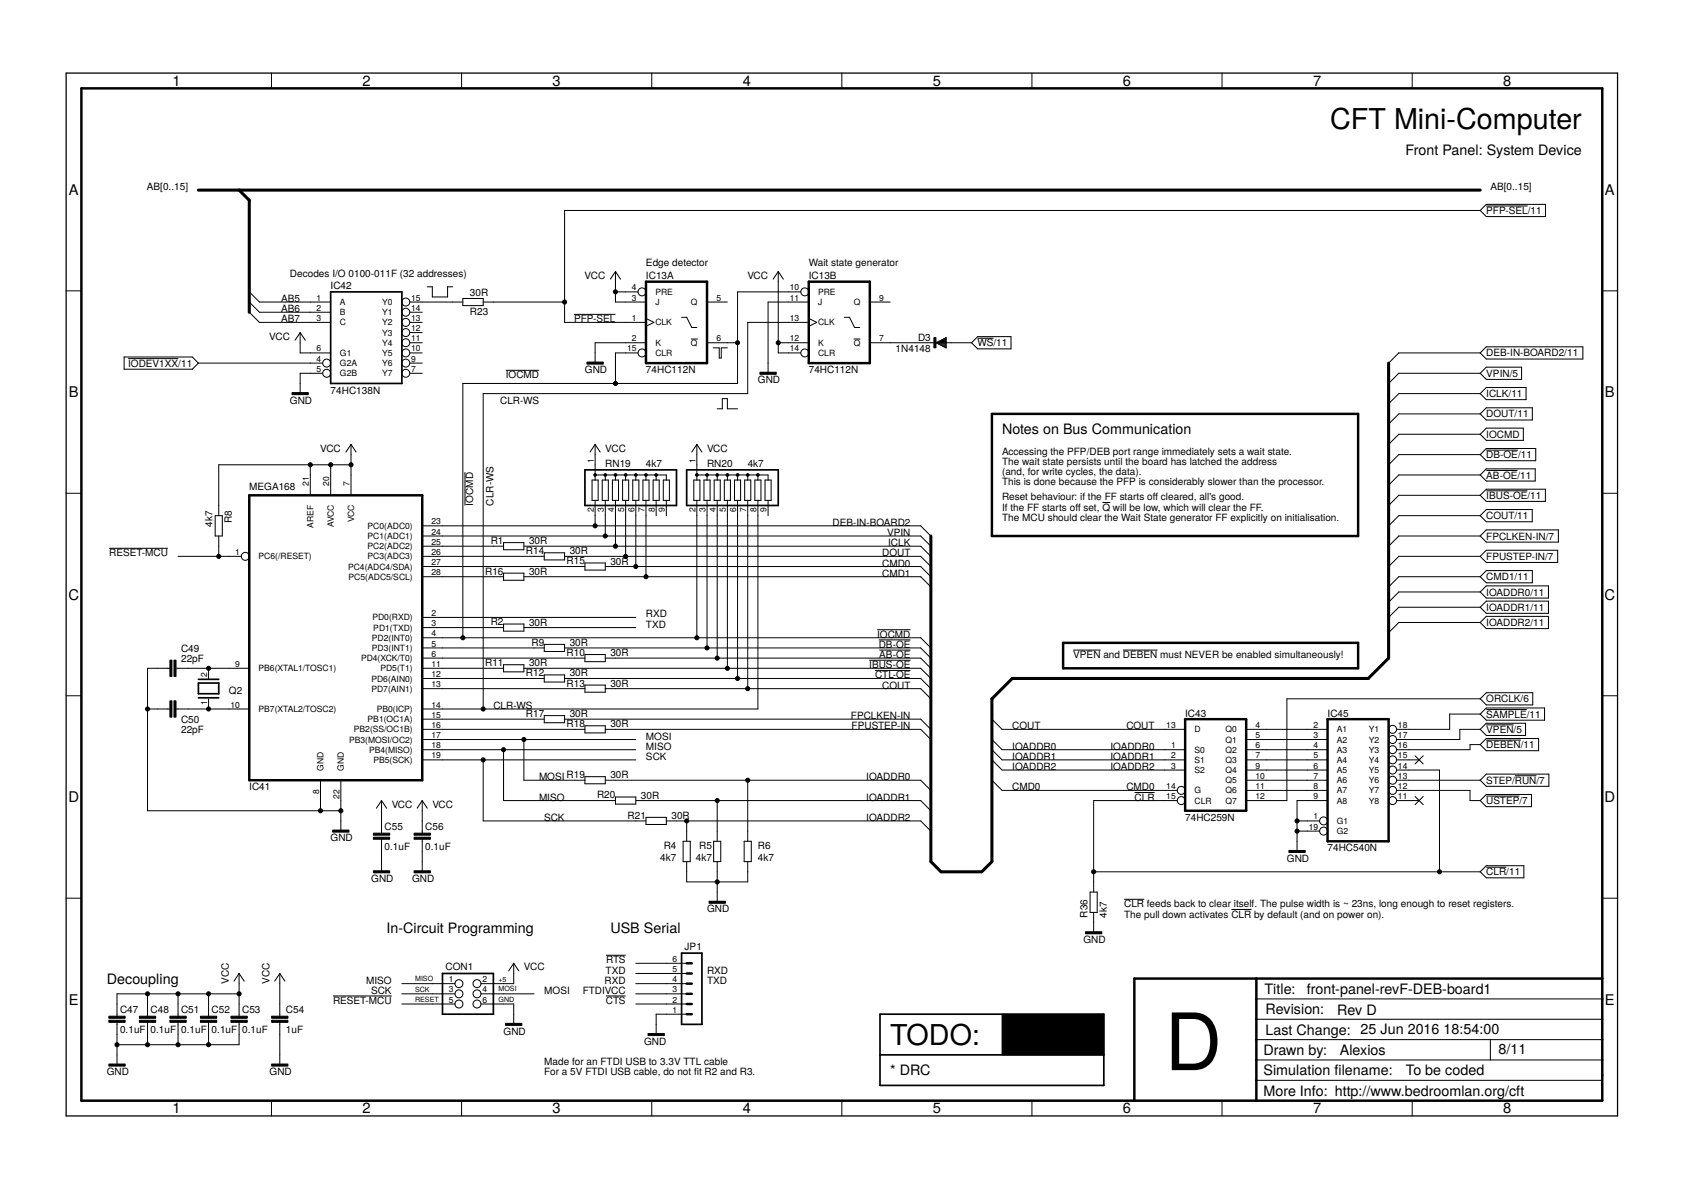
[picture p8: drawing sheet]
<svg xmlns="http://www.w3.org/2000/svg" width="420mm" height="297mm" viewBox="0 0 420 297" stroke-linecap="round" stroke-linejoin="round" font-family="sans-serif">
<defs><g id="words">
<text font-size="19.7" x="290.8" y="267.1">D</text>
<g font-size="7.2">
<text x="332.1" y="32.2">CFT Mini-Computer</text>
<text x="222.2" y="260.8">TODO:</text>
</g>
<g font-size="3.7">
<text x="43" y="21.4">1</text>
<text x="90.5" y="21.4">2</text>
<text x="138" y="21.4">3</text>
<text x="185.4" y="21.4">4</text>
<text x="232.9" y="21.4">5</text>
<text x="280.3" y="21.4">6</text>
<text x="327.8" y="21.4">7</text>
<text x="375.3" y="21.4">8</text>
<text x="17.2" y="48.6">A</text>
<text x="400.7" y="48.6">A</text>
<text x="17.2" y="99.2">B</text>
<text x="400.7" y="99.2">B</text>
<text x="17.1" y="149.7">C</text>
<text x="400.6" y="149.7">C</text>
<text x="17.1" y="200.2">D</text>
<text x="400.6" y="200.2">D</text>
<text x="17.2" y="250.8">E</text>
<text x="400.7" y="250.8">E</text>
<text x="43" y="277.9">1</text>
<text x="90.5" y="277.9">2</text>
<text x="138" y="277.9">3</text>
<text x="185.4" y="277.9">4</text>
<text x="232.9" y="277.9">5</text>
<text x="280.3" y="277.9">6</text>
<text x="327.8" y="277.9">7</text>
<text x="375.3" y="277.9">8</text>
</g>
<g font-size="3.6">
<text x="350.9" y="38.6">Front Panel: System Device</text>
<text x="250.2" y="108.4">Notes on Bus Communication</text>
<text x="96.5" y="232.8">In-Circuit Programming</text>
<text x="152.4" y="232.8">USB Serial</text>
<text x="26.7" y="245.5">Decoupling</text>
<text x="315.7" y="248.1">Title:</text>
<text x="326.2" y="248.2">front-panel-revF-DEB-board1</text>
<text x="315.9" y="253.2">Revision:</text>
<text x="333.8" y="253.3">Rev D</text>
<text x="315.4" y="263.3">Drawn by:</text>
<text x="315.9" y="258.2">Last Change: 25 Jun 2016</text>
<text x="334.5" y="263.3">Alexios</text>
<text x="360.4" y="258.1">18:54:00</text>
<text x="374.1" y="263.2">8/11</text>
<text x="222.2" y="268.4">* DRC</text>
<text x="315.4" y="268.4">Simulation flename:</text>
<text x="333.2" y="268.4">i</text>
<text x="351" y="268.4">To be coded</text>
<text x="315.4" y="273.5">More Info: http://www.bedroomlan.org/cft</text>
</g>
<g font-size="2.5">
<text x="36.7" y="47.5">AB[0..15]</text>
<text x="372.1" y="47.5">AB[0..15]</text>
<text x="371.1" y="53.4">PFP-SEL/11</text>
<text x="72.4" y="69">Decodes I/O 0100-011F (32 addresses)</text>
<text x="145.9" y="69.5">VCC</text>
<text x="161.3" y="66.5">Edge detector</text>
<text x="161.3" y="69.7">IC13A</text>
<text x="186.6" y="69.5">VCC</text>
<text x="201.9" y="66.5">Wait state generator</text>
<text x="201.9" y="69.7">IC13B</text>
<text x="70.2" y="75.4">AB5</text>
<text x="70.2" y="77.9">AB6</text>
<text x="82.5" y="72.2">IC42</text>
<text x="117.3" y="73.9">30R</text>
<text x="70.2" y="80.5">AB7</text>
<text x="117.3" y="78.7">R23</text>
<text x="143.3" y="80.5">PFP-SEL</text>
<text x="67.2" y="84.8">VCC</text>
<text x="223.6" y="87.9">1N4148</text>
<text x="229.2" y="85.1">D3</text>
<text x="244.1" y="86.4">WS/11</text>
<text x="371.1" y="89">DEB-IN-BOARD2/11</text>
<text x="32" y="91.5">IODEV1XX/11</text>
<text x="126.3" y="94.4">IOCMD</text>
<text x="146" y="93.2">GND</text>
<text x="161.3" y="93.2">74HC112N</text>
<text x="189.2" y="95.7">GND</text>
<text x="201.9" y="93.2">74HC112N</text>
<text x="371.1" y="94.1">VPIN/5</text>
<text x="72.4" y="100.8">GND</text>
<text x="82.5" y="98.2">74HC138N</text>
<text x="124.9" y="100.8">CLR-WS</text>
<text x="371.1" y="99.1">ICLK/11</text>
<text x="371.1" y="104.2">DOUT/11</text>
<text x="79.9" y="112.7">VCC</text>
<text x="151.1" y="112.7">VCC</text>
<text x="176.5" y="112.7">VCC</text>
<text x="250.2" y="113.5">Accessing the PFP/DEB port range immediately sets a wait state.</text>
<text x="371.1" y="109.3">IOCMD</text>
<text x="151.1" y="116.7">RN19</text>
<text x="161.3" y="116.7">4k7</text>
<text x="176.5" y="116.7">RN20</text>
<text x="186.7" y="116.7">4k7</text>
<text x="250.2" y="116">The wait state persists until the board has latched the address</text>
<text x="250.2" y="118.6">(and, for write cycles, the data).</text>
<text x="371.1" y="114.4">DB-OE/11</text>
<text x="371.1" y="119.5">AB-OE/11</text>
<text x="62.2" y="122.4">MEGA168</text>
<text x="250.2" y="121.1">This is done because the PFP is considerably slower than the processor.</text>
<text x="250.2" y="124.9">Reset behaviour: if the FF starts of cleared, all's good.</text>
<text x="287.8" y="124.9">f</text>
<text x="371.1" y="124.5">IBUS-OE/11</text>
<text x="53.1" y="131.5" transform="rotate(-90 53.1 131.5)">4k7</text>
<text x="57.9" y="130.6" transform="rotate(-90 57.9 130.6)">R8</text>
<text x="118.1" y="126.2" transform="rotate(-90 118.1 126.2)">IOCMD</text>
<text x="123.2" y="126.2" transform="rotate(-90 123.2 126.2)">CLR-WS</text>
<text x="207.8" y="131.3">DEB-IN-BOARD2</text>
<text x="250.2" y="127.4">If the FF starts of set, Q will be low, which will clear the FF.</text>
<text x="250.2" y="130">The MCU should clear the Wait State generator FF explicitly on initialisation.</text>
<text x="268.5" y="127.4">f</text>
<text x="371.1" y="129.6">COUT/11</text>
<text x="122.5" y="135.8">R1</text>
<text x="132.1" y="135.8">30R</text>
<text x="221.5" y="133.8">VPIN</text>
<text x="221.7" y="136.3">ICLK</text>
<text x="371.1" y="134.7">FPCLKEN-IN/7</text>
<text x="27.3" y="138.9">RESET-MCU</text>
<text x="121.1" y="143.4">R16</text>
<text x="131.3" y="138.3">R14</text>
<text x="132.1" y="143.4">30R</text>
<text x="141.4" y="140.9">R15</text>
<text x="142.2" y="138.4">30R</text>
<text x="152.4" y="140.9">30R</text>
<text x="220.2" y="141.4">CMD0</text>
<text x="220.2" y="144">CMD1</text>
<text x="220.2" y="138.9">DOUT</text>
<text x="371.1" y="139.8">FPUSTEP-IN/7</text>
<text x="371.1" y="148.7">IOADDR0/11</text>
<text x="371.1" y="144.8">CMD1/11</text>
<text x="161.3" y="154.1">RXD</text>
<text x="371.1" y="152.5">IOADDR1/11</text>
<text x="122.5" y="156.1">R2</text>
<text x="132.1" y="156.1">30R</text>
<text x="132.7" y="161.2">R9</text>
<text x="142.2" y="161.2">30R</text>
<text x="161.3" y="156.7">TXD</text>
<text x="219" y="159.2">IOCMD</text>
<text x="219.4" y="161.7">DB-OE</text>
<text x="371.1" y="156.3">IOADDR2/11</text>
<text x="45.2" y="165.2">22pF</text>
<text x="45.2" y="162.6">C49</text>
<text x="121.1" y="166.3">R11</text>
<text x="132.1" y="166.3">30R</text>
<text x="141.4" y="163.7">R10</text>
<text x="152.4" y="163.8">30R</text>
<text x="217" y="166.8">IBUS-OE</text>
<text x="219.5" y="164.3">AB-OE</text>
<text x="267.9" y="164.3">VPEN and DEBEN must NEVER be enabled simultaneously!</text>
<text x="57.1" y="173.2">Q2</text>
<text x="131.3" y="168.8">R12</text>
<text x="141.4" y="171.4">R13</text>
<text x="142.2" y="168.8">30R</text>
<text x="152.4" y="171.4">30R</text>
<text x="218.5" y="169.4">CTL-OE</text>
<text x="220.3" y="171.9">COUT</text>
<text x="123.2" y="177">CLR-WS</text>
<text x="131.3" y="179">R17</text>
<text x="142.2" y="179">30R</text>
<text x="212.4" y="179.5">FPCLKEN-IN</text>
<text x="295.9" y="178.9">IC43</text>
<text x="331.4" y="178.9">IC45</text>
<text x="371.1" y="179.1">SAMPLE/11</text>
<text x="371.1" y="175.3">ORCLK/6</text>
<text x="45.2" y="182.9">22pF</text>
<text x="45.2" y="180.4">C50</text>
<text x="141.4" y="181.5">R18</text>
<text x="152.4" y="181.5">30R</text>
<text x="161.3" y="184.6">MOSI</text>
<text x="212.6" y="182.1">FPUSTEP-IN</text>
<text x="252.7" y="182.1">COUT</text>
<text x="281.2" y="182.1">COUT</text>
<text x="371.1" y="182.9">VPEN/5</text>
<text x="161.3" y="189.7">SCK</text>
<text x="161.3" y="187.1">MISO</text>
<text x="252.7" y="187.1">IOADDR0</text>
<text x="252.7" y="189.7">IOADDR1</text>
<text x="277.2" y="187.1">IOADDR0</text>
<text x="277.2" y="189.7">IOADDR1</text>
<text x="371.1" y="186.7">DEBEN/11</text>
<text x="62.2" y="197.3">IC41</text>
<text x="134.6" y="194.7">MOSI R19</text>
<text x="152.4" y="194.2">30R</text>
<text x="216.3" y="194.7">IOADDR0</text>
<text x="252.7" y="192.2">IOADDR2</text>
<text x="252.7" y="197.3">CMD0</text>
<text x="277.2" y="192.2">IOADDR2</text>
<text x="281.2" y="197.3">CMD0</text>
<text x="371.1" y="195.6">STEP/RUN/7</text>
<text x="97.8" y="201.6">VCC</text>
<text x="107.9" y="201.6">VCC</text>
<text x="134.6" y="199.8">MISO</text>
<text x="149.1" y="199.3">R20</text>
<text x="160" y="199.3">30R</text>
<text x="216.3" y="199.8">IOADDR1</text>
<text x="283.3" y="199.8">CLR</text>
<text x="371.1" y="200.7">USTEP/7</text>
<text x="82.5" y="210">GND</text>
<text x="96" y="207.1">C55</text>
<text x="106.2" y="207.1">C56</text>
<text x="135.8" y="204.9">SCK</text>
<text x="156.7" y="204.4">R21</text>
<text x="167.6" y="204.4">30R</text>
<text x="216.3" y="204.9">IOADDR2</text>
<text x="295.9" y="204.9">74HC259N</text>
<text x="96" y="212.1">0.1uF</text>
<text x="106.2" y="212.1">0.1uF</text>
<text x="164.8" y="214.8">4k7</text>
<text x="165.7" y="212">R4</text>
<text x="173.7" y="214.8">4k7</text>
<text x="174.6" y="212">R5</text>
<text x="189.2" y="214.8">4k7</text>
<text x="189.2" y="212">R6</text>
<text x="321.3" y="215.1">GND</text>
<text x="331.4" y="212.5">74HC540N</text>
<text x="92.7" y="220.1">GND</text>
<text x="102.9" y="220.1">GND</text>
<text x="371.1" y="218.5">CLR/11</text>
<text x="176.5" y="227.8">GND</text>
<text x="280.6" y="226.5">CLR feeds back to clear itself. The pulse width is ~ 23ns, long enough to reset registers.</text>
<text x="271.5" y="229" transform="rotate(-90 271.5 229)">R36</text>
<text x="276.3" y="229" transform="rotate(-90 276.3 229)">4k7</text>
<text x="280.6" y="229">The pull down activates CLR by default (and on power on).</text>
<text x="170.9" y="237.2">JP1</text>
<text x="270.5" y="235.4">GND</text>
<text x="57.1" y="245.5" transform="rotate(-90 57.1 245.5)">VCC</text>
<text x="67.3" y="245.5" transform="rotate(-90 67.3 245.5)">VCC</text>
<text x="91.4" y="245.5">MISO</text>
<text x="111.2" y="242.2">CON1</text>
<text x="130.8" y="242.2">VCC</text>
<text x="150.9" y="245.5">RXD</text>
<text x="151.2" y="243">TXD</text>
<text x="151.3" y="240.5">RTS</text>
<text x="176.5" y="243">RXD</text>
<text x="176.5" y="245.5">TXD</text>
<text x="83.1" y="250.6">RESET-MCU</text>
<text x="92.7" y="248.1">SCK</text>
<text x="135.9" y="248.1">MOSI</text>
<text x="145.5" y="248.1">FTDIVCC</text>
<text x="151.3" y="250.6">CTS</text>
<text x="30" y="257.9">0.1uF</text>
<text x="30" y="252.8">C47</text>
<text x="37.6" y="257.9">0.1uF</text>
<text x="37.6" y="252.8">C48</text>
<text x="45.2" y="257.9">0.1uF</text>
<text x="45.2" y="252.8">C51</text>
<text x="52.8" y="257.9">0.1uF</text>
<text x="52.8" y="252.8">C52</text>
<text x="60.4" y="257.9">0.1uF</text>
<text x="60.4" y="252.8">C53</text>
<text x="71.4" y="257.9">1uF</text>
<text x="71.4" y="252.8">C54</text>
<text x="125.7" y="258.2">GND</text>
<text x="160.8" y="260.8">GND</text>
<text x="26.7" y="268.4">GND</text>
<text x="67.3" y="268.4">GND</text>
<text x="135.9" y="265.9">Made for an FTDI USB to 3.3V TTL cable</text>
<text x="135.9" y="268.4">For a 5V FTDI USB cable, do not ft R2 and R3.</text>
<text x="173.3" y="268.4">i</text>
</g>
<g font-size="2.1">
<text x="79" y="75">1</text>
<text x="79" y="77.6">2</text>
<text x="84.9" y="76.2">A</text>
<text x="95.4" y="76.2">Y0</text>
<text x="102.7" y="77.6">14</text>
<text x="102.7" y="75">15</text>
<text x="157.8" y="75">3</text>
<text x="157.8" y="72.5">4</text>
<text x="163.6" y="76.2">J</text>
<text x="163.6" y="73.6">PRE</text>
<text x="172.5" y="76.2">Q</text>
<text x="178.8" y="75">5</text>
<text x="197.2" y="75">11</text>
<text x="197.2" y="72.5">10</text>
<text x="204.2" y="76.2">J</text>
<text x="204.2" y="73.6">PRE</text>
<text x="213.1" y="76.2">Q</text>
<text x="219.5" y="75">9</text>
<text x="79" y="80.1">3</text>
<text x="84.9" y="78.7">B</text>
<text x="84.9" y="81.2">C</text>
<text x="95.4" y="83.8">Y3</text>
<text x="95.4" y="81.2">Y2</text>
<text x="95.4" y="78.7">Y1</text>
<text x="102.7" y="82.7">12</text>
<text x="102.7" y="80.1">13</text>
<text x="157.8" y="80.1">1</text>
<text x="163.6" y="81.2">CLK</text>
<text x="197.2" y="80.1">13</text>
<text x="204.2" y="81.2">CLK</text>
<text x="79" y="87.7">6</text>
<text x="84.9" y="88.8">G1</text>
<text x="95.4" y="88.8">Y5</text>
<text x="95.4" y="86.3">Y4</text>
<text x="102.7" y="87.7">10</text>
<text x="102.7" y="85.2">11</text>
<text x="156.6" y="87.7">15</text>
<text x="157.8" y="85.2">2</text>
<text x="163.6" y="86.3">K</text>
<text x="163.6" y="88.8">CLR</text>
<text x="172.5" y="86.3">Q</text>
<text x="178.8" y="85.2">6</text>
<text x="197.2" y="85.2">12</text>
<text x="197.2" y="87.7">14</text>
<text x="204.2" y="86.3">K</text>
<text x="204.2" y="88.8">CLR</text>
<text x="213.1" y="86.3">Q</text>
<text x="219.5" y="85.2">7</text>
<text x="79" y="90.3">4</text>
<text x="79" y="92.8">5</text>
<text x="84.9" y="91.4">G2A</text>
<text x="84.9" y="93.9">G2B</text>
<text x="95.4" y="93.9">Y7</text>
<text x="95.4" y="91.4">Y6</text>
<text x="102.7" y="92.8">7</text>
<text x="102.7" y="90.3">9</text>
<text x="148.2" y="115.7" transform="rotate(-90 148.2 115.7)">1</text>
<text x="173.6" y="115.7" transform="rotate(-90 173.6 115.7)">1</text>
<text x="77.1" y="121.3" transform="rotate(-90 77.1 121.3)">21</text>
<text x="82.2" y="121.3" transform="rotate(-90 82.2 121.3)">20</text>
<text x="87.3" y="121.3" transform="rotate(-90 87.3 121.3)">7</text>
<text x="78.2" y="131.7" transform="rotate(-90 78.2 131.7)">AREF</text>
<text x="83.3" y="131.6" transform="rotate(-90 83.3 131.6)">AVCC</text>
<text x="88.4" y="130.4" transform="rotate(-90 88.4 130.4)">VCC</text>
<text x="107.7" y="130.9">23</text>
<text x="148.2" y="127.7" transform="rotate(-90 148.2 127.7)">2</text>
<text x="150.8" y="127.7" transform="rotate(-90 150.8 127.7)">3</text>
<text x="153.3" y="127.7" transform="rotate(-90 153.3 127.7)">4</text>
<text x="155.8" y="127.7" transform="rotate(-90 155.8 127.7)">5</text>
<text x="158.4" y="127.7" transform="rotate(-90 158.4 127.7)">6</text>
<text x="160.9" y="127.7" transform="rotate(-90 160.9 127.7)">7</text>
<text x="163.5" y="127.7" transform="rotate(-90 163.5 127.7)">8</text>
<text x="166" y="127.7" transform="rotate(-90 166 127.7)">9</text>
<text x="173.6" y="127.7" transform="rotate(-90 173.6 127.7)">2</text>
<text x="176.2" y="127.7" transform="rotate(-90 176.2 127.7)">3</text>
<text x="178.7" y="127.7" transform="rotate(-90 178.7 127.7)">4</text>
<text x="181.2" y="127.7" transform="rotate(-90 181.2 127.7)">5</text>
<text x="183.8" y="127.7" transform="rotate(-90 183.8 127.7)">6</text>
<text x="186.3" y="127.7" transform="rotate(-90 186.3 127.7)">7</text>
<text x="188.9" y="127.7" transform="rotate(-90 188.9 127.7)">8</text>
<text x="191.4" y="127.7" transform="rotate(-90 191.4 127.7)">9</text>
<text x="91.8" y="137.1">PC2(ADC2)</text>
<text x="91.8" y="134.6">PC1(ADC1)</text>
<text x="91.8" y="132">PC0(ADC0)</text>
<text x="107.7" y="136">25</text>
<text x="107.7" y="133.4">24</text>
<text x="58.7" y="138.5">1</text>
<text x="64.6" y="139.6">PC6(/RESET)</text>
<text x="86.9" y="142.2">PC4(ADC4/SDA)</text>
<text x="91.8" y="139.6">PC3(ADC3)</text>
<text x="107.7" y="143.6">28</text>
<text x="107.7" y="141.1">27</text>
<text x="107.7" y="138.5">26</text>
<text x="87" y="144.7">PC5(ADC5/SCL)</text>
<text x="93" y="154.9">PD0(RXD)</text>
<text x="107.7" y="153.8">2</text>
<text x="92.8" y="160">PD2(INT0)</text>
<text x="93.2" y="157.4">PD1(TXD)</text>
<text x="107.7" y="161.4">5</text>
<text x="107.7" y="158.8">4</text>
<text x="107.7" y="156.3">3</text>
<text x="58.7" y="166.5">9</text>
<text x="64.6" y="167.6">PB6(XTAL1/TOSC1)</text>
<text x="90.1" y="165">PD4(XCK/T0)</text>
<text x="92.8" y="162.5">PD3(INT1)</text>
<text x="95" y="167.6">PD5(T1)</text>
<text x="107.7" y="166.5">11</text>
<text x="107.7" y="163.9">6</text>
<text x="51.7" y="169" transform="rotate(-90 51.7 169)">2</text>
<text x="92.7" y="172.7">PD7(AIN1)</text>
<text x="92.7" y="170.1">PD6(AIN0)</text>
<text x="107.7" y="171.5">13</text>
<text x="107.7" y="169">12</text>
<text x="51.7" y="176" transform="rotate(-90 51.7 176)">1</text>
<text x="57.5" y="176.6">10</text>
<text x="64.6" y="177.7">PB7(XTAL2/TOSC2)</text>
<text x="94" y="177.7">PB0(ICP)</text>
<text x="107.7" y="179.2">15</text>
<text x="107.7" y="176.6">14</text>
<text x="87.1" y="185.4">PB3(MOSI/OC2)</text>
<text x="88.4" y="182.8">PB2(SS/OC1B)</text>
<text x="91.8" y="180.3">PB1(OC1A)</text>
<text x="107.7" y="184.2">17</text>
<text x="107.7" y="181.7">16</text>
<text x="291.2" y="181.7">13</text>
<text x="298.2" y="182.8">D</text>
<text x="305.9" y="182.8">Q0</text>
<text x="305.9" y="185.4">Q1</text>
<text x="313.5" y="181.7">4</text>
<text x="313.5" y="184.2">5</text>
<text x="327.9" y="181.7">2</text>
<text x="327.9" y="184.2">3</text>
<text x="333.8" y="182.8">A1</text>
<text x="333.8" y="185.4">A2</text>
<text x="341.7" y="185.4">Y2</text>
<text x="341.7" y="182.8">Y1</text>
<text x="349" y="184.2">17</text>
<text x="349" y="181.7">18</text>
<text x="92.1" y="187.9">PB4(MISO)</text>
<text x="93.2" y="190.4">PB5(SCK)</text>
<text x="107.7" y="189.3">19</text>
<text x="107.7" y="186.8">18</text>
<text x="292.4" y="186.8">1</text>
<text x="292.4" y="189.3">2</text>
<text x="292.4" y="191.9">3</text>
<text x="298.2" y="187.9">S0</text>
<text x="298.2" y="190.4">S1</text>
<text x="305.9" y="187.9">Q2</text>
<text x="305.9" y="190.4">Q3</text>
<text x="313.5" y="186.8">6</text>
<text x="313.5" y="189.3">7</text>
<text x="313.5" y="191.9">9</text>
<text x="327.9" y="186.8">4</text>
<text x="327.9" y="189.3">5</text>
<text x="327.9" y="191.9">6</text>
<text x="333.8" y="187.9">A3</text>
<text x="333.8" y="190.4">A4</text>
<text x="341.7" y="190.4">Y4</text>
<text x="341.7" y="187.9">Y3</text>
<text x="349" y="191.9">14</text>
<text x="349" y="189.3">15</text>
<text x="349" y="186.8">16</text>
<text x="80.8" y="192.4" transform="rotate(-90 80.8 192.4)">GND</text>
<text x="85.8" y="192.4" transform="rotate(-90 85.8 192.4)">GND</text>
<text x="291.2" y="196.9">14</text>
<text x="298.2" y="193">S2</text>
<text x="305.9" y="193">Q4</text>
<text x="305.9" y="195.5">Q5</text>
<text x="313.5" y="194.4">10</text>
<text x="313.5" y="196.9">11</text>
<text x="327.9" y="194.4">7</text>
<text x="327.9" y="196.9">8</text>
<text x="333.8" y="193">A5</text>
<text x="333.8" y="195.5">A6</text>
<text x="341.7" y="195.5">Y6</text>
<text x="341.7" y="193">Y5</text>
<text x="349" y="196.9">12</text>
<text x="349" y="194.4">13</text>
<text x="79.6" y="198.3" transform="rotate(-90 79.6 198.3)">8</text>
<text x="84.7" y="199.5" transform="rotate(-90 84.7 199.5)">22</text>
<text x="291.2" y="199.5">15</text>
<text x="298.2" y="198">G</text>
<text x="298.2" y="200.6">CLR</text>
<text x="305.9" y="198">Q6</text>
<text x="305.9" y="200.6">Q7</text>
<text x="313.5" y="199.5">12</text>
<text x="327.9" y="199.5">9</text>
<text x="333.8" y="198">A7</text>
<text x="333.8" y="200.6">A8</text>
<text x="341.7" y="200.6">Y8</text>
<text x="341.7" y="198">Y7</text>
<text x="349" y="199.5">11</text>
<text x="326.7" y="207.1">19</text>
<text x="327.9" y="204.6">1</text>
<text x="333.8" y="205.7">G1</text>
<text x="333.8" y="208.2">G2</text>
<text x="112" y="245.2">1</text>
<text x="120.4" y="245.2">2</text>
<text x="167.9" y="245.2">4</text>
<text x="167.9" y="242.6">5</text>
<text x="167.9" y="240.1">6</text>
<text x="112" y="247.7">3</text>
<text x="112" y="250.3">5</text>
<text x="120.4" y="247.7">4</text>
<text x="120.4" y="250.3">6</text>
<text x="167.9" y="250.3">2</text>
<text x="167.9" y="247.7">3</text>
<text x="167.9" y="252.8">1</text>
</g>
<g font-size="1.8">
<text x="103.6" y="244.8">MISO</text>
<text x="124.4" y="245">+5</text>
<text x="103.6" y="250.1">RESET</text>
<text x="103.6" y="247.6">SCK</text>
<text x="124.4" y="247.4">MOSI</text>
<text x="124.4" y="250.1">GND</text>
</g>
</g></defs>
<g fill="none" stroke="#000" stroke-width=".25">
<path d="M67.8 18.2v3.9M115.2 18.2v3.9M162.7 18.2v3.9M210.2 18.2v3.9M257.6 18.2v3.9M305.1 18.2v3.9M352.6 18.2v3.9M20.3 22.1h379.7v252.6h-379.7zM369.5 52.5l1.6-1.5h14.7v3.1h-14.7zM369.5 52.5h-228.6v28h20.4M371.1 51.4h10.3M16.5 72.6h3.8"/>
<path d="M62.2 72.9l2.6 2.5h17.7M62.2 75.4l2.6 2.5h17.7M62.2 77.9l2.6 2.6h17.7M102.3 75.4h13.2M102.3 77.9h3.1M106.7 71.6h1.2v2.5h3.8v-2.5h1.3M115.5 74.5h5.1v1.8h-5.1zM120.6 75.4h20.3M143.3 78.5h10.3M153.6 67.8v7.6h7.7M153.6 72.9h5.7M153.6 67.8l1.3 1.9"/>
<path d="M153.6 67.8l-1.2 1.9M161.3 79.5l2 1-2 .9M170.2 79.2h1.2l1.3 2.5h1.3M176.5 75.4h5.1M194.3 67.8v20.3h5.6M194.3 67.8l1.3 1.9M194.3 67.8l-1.3 1.9M199.9 72.9h-15.8v22.8h-68.6v63.5M201.9 75.4h-10.2v17.8M201.9 79.5l2 1-2 .9M210.8 79.2h1.3l1.2 2.5h1.3M217.1 75.4h5.1"/>
<path d="M400 72.6h3.8M31 89.1h17l1.5 1.5-1.5 1.6h-17zM32 89.5h12.5M49.5 90.6h31.1M73 98.3h3.8M74.9 83v5.1h7.6M74.9 83l1.3 1.9M74.9 83l-1.2 1.9M80.6 93.2h-5.7v5.1M102.3 80.5h3.1M102.3 90.6h3.1M102.3 93.2h3.1"/>
<path d="M102.3 88.1h3.1M102.3 85.6h3.1M102.3 83h3.1M126.3 92.4h8.3M146.7 90.6h3.8M159.3 88.1h-5.7v7.6M161.3 85.6h-12.7v5M172.5 84.6h1.7M176.5 85.6h7.6M178 86.8h1.6v2.6h.5v-2.6h1.5M189.8 93.2h3.9M194.3 85.6h7.6"/>
<path d="M201.9 80.5h-15.2v17.8h-66.1v78.7M213.1 84.6h1.7M217.1 85.6h25.4M233.7 85.6l2.5-1.3v2.5zM233.8 85.4h2.4M233.9 85.7h2.3M234.3 85.2h1.9M234.4 85.9h1.8M234.7 85h1.5M234.8 86.1h1.4M235.2 84.8h1M235.2 86.3h1"/>
<path d="M235.6 84.6h.6M235.7 86.6h.5M236.1 84.3h.1M236.1 86.8h.1M244.1 84h8.3v3.1h-8.3l-1.6-1.5zM244.1 84.4h3.9M369.5 98.3h-20.3l-2.5 2.5M369.5 93.2h-20.3l-2.5 2.5M369.5 88.1h-20.3l-2.5 2.5M371.1 86.6h24.1v3h-24.1l-1.6-1.5zM371.1 91.7h8.8v3h-8.8l-1.6-1.5zM371.1 96.7h9.9v3.1h-9.9l-1.6-1.5z"/>
<path d="M77.5 116v7.6M82.5 116v7.6M87.6 110.9v12.7M87.6 110.9l1.3 1.9M87.6 110.9l-1.2 1.9M87.6 116h-33v12.7M116.1 117.9v8.3M147.8 119.8h1.5v5.1h-1.5zM148.6 110.9v8.9M148.6 118.6h17.7v1.2M148.6 110.9l-1.3 1.9M148.6 110.9l1.2 1.9"/>
<path d="M150.3 119.8h1.6v5.1h-1.6zM151.1 118.6v1.2M152.9 119.8h1.5v5.1h-1.5zM153.6 118.6v1.2M155.4 119.8h1.6v5.1h-1.6zM156.2 118.6v1.2M158 119.8h1.5v5.1h-1.5zM158.7 118.6v1.2M160.5 119.8h1.5v5.1h-1.5zM161.3 118.6v1.2M163 119.8h1.6v5.1h-1.6zM163.8 118.6v1.2"/>
<path d="M165.6 119.8h1.5v5.1h-1.5zM173.2 119.8h1.5v5.1h-1.5zM174 118.6h17.7v1.2M174 110.9v8.9M174 110.9l-1.3 1.9M174 110.9l1.2 1.9M175.7 119.8h1.6v5.1h-1.6zM176.5 118.6v1.2M178.3 119.8h1.5v5.1h-1.5zM179 102h1.3v-2.5h1.3v2.5h2.5M179 118.6v1.2M180.8 119.8h1.6v5.1h-1.6z"/>
<path d="M181.6 118.6v1.2M183.4 119.8h1.5v5.1h-1.5zM184.1 118.6v1.2M185.9 119.8h1.5v5.1h-1.5zM186.7 118.6v1.2M188.4 119.8h1.6v5.1h-1.6zM189.2 118.6v1.2M191 119.8h1.5v5.1h-1.5zM369.5 108.4h-20.3l-2.5 2.5M369.5 103.3l1.6-1.5h11.4v3h-11.4zM369.5 113.5h-20.3l-2.5 2.5M369.5 118.6h-20.3l-2.5 2.5"/>
<path d="M369.5 103.3h-20.3l-2.5 2.6M371.1 106.9h9.2v3h-9.2l-1.6-1.5zM371.1 112h12.3v3h-12.3l-1.6-1.5zM371.1 112.4h7.9M371.1 117h12.2v3.1h-12.2l-1.6-1.5zM371.1 117.4h7.7M16.5 123.1h3.8M27.3 136.9h14.6M44.4 138.9h15.8M53.7 128.7h1.8v5.1h-1.8zM54.6 133.8v5.1M105.4 138.9h30.5"/>
<path d="M105.4 136.3h20.3M105.4 133.8h124.4l2.6 2.5M105.4 131.3h124.4l2.6 2.5M125.7 135.4h5.1v1.8h-5.1zM130.8 136.3h99l2.6 2.6M135.9 138h5v1.8h-5zM140.9 138.9h88.9l2.6 2.5M148.6 124.9v6.4M151.1 124.9v8.9M153.6 124.9v11.4M156.2 124.9v14M158.7 124.9v16.5"/>
<path d="M161.3 124.9v19.1M163.8 124.9v3.8M166.3 124.9v3.8M174 124.9v34.3M176.5 124.9v36.8M179 124.9v39.4M181.6 124.9v41.9M184.1 124.9v44.5M186.7 124.9v47M189.2 124.9v52.1h-83.8M191.7 124.9v3.8M275.2 125.4h2"/>
<path d="M369.5 128.7h-20.3l-2.5 2.6M369.5 128.7l1.6-1.5h11.4v3h-11.4zM369.5 123.6h-20.3l-2.5 2.6M369.5 133.8h-20.3l-2.5 2.5M369.5 138.9h-20.3l-2.5 2.5M371.1 122.1h14.7v3.1h-14.7l-1.6-1.6zM371.1 122.5h10.2M371.1 132.3h17.9v3h-17.9l-1.6-1.5zM371.1 137.4h17.8v3h-17.8l-1.6-1.5zM400 123.1h3.8M105.4 159.2h124.4l2.6 2.5M105.4 156.7h20.3"/>
<path d="M105.4 154.1h53.3M105.4 144h20.3M105.4 141.4h40.6M125.7 143.1h5.1v1.7h-5.1zM125.7 155.8h5.1v1.7h-5.1zM130.8 156.7h27.9M130.8 144h99l2.6 2.5M146 140.5h5.1v1.8h-5.1zM151.1 141.4h78.7l2.6 2.6M219 157.2h8.3M219.4 159.7h7.9M369.5 151.6l1.6-1.5h15.5v3h-15.5z"/>
<path d="M369.5 155.4l1.6-1.5h15.5v3h-15.5zM369.5 144h-20.3l-2.5 2.5M369.5 147.8h-20.3l-2.5 2.5M369.5 151.6h-20.3l-2.5 2.5M369.5 155.4h-20.3l-2.5 2.5M371.1 146.2h15.5v3.1h-15.5l-1.6-1.5zM371.1 142.4h11.4v3.1h-11.4l-1.6-1.5zM16.5 173.7h3.8M36.8 177h5.6M42.4 166.8h-5.6v35.6h48.3M43.9 177h18.3M43.9 166.8h18.3"/>
<path d="M52.1 166.8v2.6M52.1 174.4v2.6M105.4 166.8h20.3M105.4 179.5h30.5M105.4 171.9h40.6M105.4 169.4h30.5M105.4 164.3h40.6M105.4 161.7h30.5M125.7 165.9h5.1v1.8h-5.1zM130.8 166.8h99l2.6 2.6M135.9 160.8h5v1.8h-5zM135.9 168.5h5v1.7h-5z"/>
<path d="M135.9 178.6h5v1.8h-5zM140.9 179.5h88.9l2.6 2.6M140.9 169.4h88.9l2.6 2.5M140.9 161.7h88.9l2.6 2.6M146 163.4h5.1v1.8h-5.1zM146 171h5.1v1.8h-5.1zM151.1 171.9h78.7l2.6 2.5M151.1 164.3h78.7l2.6 2.5M217 164.8h10.3M218.5 167.3h8.8M219.5 162.3h7.8M247.6 179.5l2.6 2.6h45.7"/>
<path d="M267.9 162.3h6.9M280.4 162.3h8.6M369.5 178.2h-7.6v3.9h-13.2M369.5 174.4h-48.2v25.4h-10.2M371.1 176.7h14.5v3.1h-14.5l-1.6-1.6zM371.1 177.1h10.1M371.1 172.9h11.6v3.1h-11.6l-1.6-1.6zM400 173.7h3.8M80 194.8v7.6M85.1 194.8v12.7M95.2 199.8v8.2M95.2 199.8l-1.2 1.9"/>
<path d="M95.2 199.8l1.3 1.9M105.4 189.7h53.3M105.4 187.1h53.3M105.4 184.6h53.3M105.4 182.1h40.6M105.4 199.8v8.2M105.4 199.8l-1.3 1.9M105.4 199.8l1.3 1.9M120.6 189.7v15.2h40.7M125.7 187.1v12.7h27.9M130.8 184.6v10.2h15.2M146 181.2h5.1v1.7h-5.1z"/>
<path d="M146 193.9h5.1v1.7h-5.1zM151.1 182.1h78.7l2.6 2.5M151.1 194.8h78.7l2.6 2.5M153.6 198.9h5.1v1.8h-5.1zM158.7 199.8h71.1l2.6 2.6M179 199.8v10.2M186.7 194.8v15.2M247.6 187.1l2.6 2.6h45.7M247.6 184.6l2.6 2.5h45.7M247.6 189.7l2.6 2.5h45.7M247.6 194.8l2.6 2.5h43.7M283.3 197.8h4.9"/>
<path d="M293.9 199.8h-20.9v22.9M311.1 189.7h20.3M311.1 187.1h20.3M311.1 184.6h20.3M311.1 182.1h20.3M311.1 192.2h20.3M311.1 194.8h20.3M311.1 197.3h20.3M331.4 199.8h-7.6v12.7M348.7 189.7h5.6M348.7 192.2h10.7v25.4M348.7 194.8h20.8"/>
<path d="M348.7 197.3h18.3v2.5h2.5M348.7 199.8h5.6M353.3 198.8l2 2.1M353.3 188.7l2 2M355.3 188.7l-2 2M355.3 198.8l-2 2.1M369.5 185.9h-2.5v1.2h-18.3M369.5 182.1h-5.1v2.5h-15.7M371.1 180.5h9.8v3.1h-9.8l-1.6-1.5zM371.1 180.9h6.8M371.1 184.3h13v3.1h-13l-1.6-1.5zM371.1 184.7h8.6"/>
<path d="M371.1 193.2h15.6v3.1h-15.6l-1.6-1.5zM371.1 198.3h11.2v3.1h-11.2l-1.6-1.6zM371.1 198.7h8.2M378.2 193.6h5.4M83.2 207.5h3.8M93.3 217.6h3.9M95.2 209.5v8.1M103.5 217.6h3.8M105.4 209.5v8.1M161.3 204h5v1.8h-5zM166.3 204.9h63.5l2.6 2.6M170.5 210h1.8v5.1h-1.8z"/>
<path d="M171.4 215.1v5h15.3v-5M171.4 204.9v5.1M178.2 210h1.7v5.1h-1.7zM179 215.1v10.1M185.8 210h1.8v5.1h-1.8zM273 217.6h96.5M321.9 212.5h3.8M323.8 207.5h5.7M323.8 204.9h5.7M371.1 216.1h9.3v3h-9.3l-1.6-1.5zM371.1 216.5h4.9M16.5 224.2h3.8"/>
<path d="M151.3 238.4h4.9M177.1 225.2h3.9M271.1 232.8h3.8M272.1 222.7h1.8v5.1h-1.8zM273 227.8v5M280.6 224.5h5M307.4 227h5M400 224.2h3.8M29.2 255.2v10.7M36.8 248.1v5.6M36.8 255.2v5.6M44.4 248.1v5.6"/>
<path d="M44.4 255.2v5.6M52.1 248.1v5.6M52.1 255.2v5.6M59.7 243l1.3 1.9M59.7 243l-1.3 1.9M59.7 243v10.7M59.7 255.2v5.6h-30.5M59.7 248.1h-30.5v5.6M69.8 243l1.3 1.9M69.8 243l-1.2 1.9M69.8 243v10.7M69.8 255.2v10.7"/>
<path d="M83.1 248.6h14.7M100.3 245.5h13.3M100.3 248.1h13.3M100.3 250.6h13.3M120.1 248.1h13.2M120.1 250.6h8.1v5.1M126.3 255.7h3.9M128.2 240.5v5h-8.1M128.2 240.5l-1.2 1.9M128.2 240.5l1.3 1.9M151.3 248.6h4.9M158.7 245.5h12.7"/>
<path d="M158.7 248.1h12.7M158.7 250.6h12.7M158.7 243h12.7M158.7 240.5h12.7M161.9 258.2h3.8M171.4 253.2h-7.6v5M313.6 249.3h86.4M313.6 254.4h86.4M313.6 259.5h86.4M372.1 259.5v5.1M27.3 265.9h3.8M67.8 274.7v3.9"/>
<path d="M67.9 265.9h3.9M115.2 274.7v3.9M162.7 274.7v3.9M210.2 274.7v3.9M257.6 274.7v3.9M305.1 274.7v3.9M313.6 264.6h86.4M313.6 269.7h86.4M352.6 274.7v3.9M400 274.6h.1"/>
<circle cx="101.3" cy="75.4" r=".99"/>
<circle cx="101.3" cy="77.9" r=".99"/>
<circle cx="160.3" cy="72.9" r=".99"/>
<circle cx="200.9" cy="72.9" r=".99"/>
<circle cx="81.6" cy="93.2" r=".99"/>
<circle cx="81.6" cy="90.6" r=".99"/>
<circle cx="101.3" cy="93.2" r=".99"/>
<circle cx="101.3" cy="90.6" r=".99"/>
<circle cx="101.3" cy="88.1" r=".99"/>
<circle cx="101.3" cy="83" r=".99"/>
<circle cx="101.3" cy="80.5" r=".99"/>
<circle cx="101.3" cy="85.6" r=".99"/>
<circle cx="160.3" cy="88.1" r=".99"/>
<circle cx="200.9" cy="88.1" r=".99"/>
<circle cx="61.2" cy="138.9" r=".99"/>
<circle cx="294.9" cy="199.8" r=".99"/>
<circle cx="294.9" cy="197.3" r=".99"/>
<circle cx="347.7" cy="194.8" r=".99"/>
<circle cx="347.7" cy="199.8" r=".99"/>
<circle cx="347.7" cy="197.3" r=".99"/>
<circle cx="347.7" cy="192.2" r=".99"/>
<circle cx="347.7" cy="187.1" r=".99"/>
<circle cx="347.7" cy="184.6" r=".99"/>
<circle cx="347.7" cy="182.1" r=".99"/>
<circle cx="347.7" cy="189.7" r=".99"/>
<circle cx="330.4" cy="204.9" r=".99"/>
<circle cx="330.4" cy="207.5" r=".99"/>
<circle cx="114.6" cy="250.6" r=".99"/>
<circle cx="114.6" cy="245.5" r=".99"/>
<circle cx="114.6" cy="248.1" r=".99"/>
<circle cx="119.1" cy="245.5" r=".99"/>
<circle cx="119.1" cy="248.1" r=".99"/>
<circle cx="119.1" cy="250.6" r=".99"/>
</g>
<g fill="none" stroke="#000" stroke-width=".61">
<path d="M20.3 22.1h379.7v252.6h-379.7zM161.3 70.3h15.2v20.3h-15.2zM201.9 70.3h15.2v20.3h-15.2zM247.6 103.3h91.4v30.5h-91.4zM62.2 123.6h43.2v71.2h-43.2zM265.4 160.5h73.6v6.3h-73.6zM295.9 179.5h15.2v22.9h-15.2zM331.4 179.5h15.3v30.5h-15.3zM171.4 248.1h1.3M171.4 250.6h1.3M171.4 253.2h1.3M171.4 243h1.3"/>
<path d="M171.4 245.5h1.3M171.4 240.5h1.3M313.6 244.3v30.4M400 244.3h-116.8v30.4"/>
</g>
<path d="M16.5 18.2h387.3v260.4h-387.3z" fill="none" stroke="#000" stroke-width=".32"/>
<g fill="#000" stroke="#000" stroke-width=".25">
<path d="M72.9 98h4.1v.5h-4.1zM146.5 90.4h4.1v.5h-4.1zM189.7 92.9h4.1v.5h-4.1zM233.2 84.3h.5v2.5h-.5zM42.4 164.8h.5v4h-.5zM42.4 174.9h.5v4.1h-.5zM43.4 164.8h.5v4h-.5zM43.4 174.9h.5v4.1h-.5zM83.1 207.2h4v.5h-4zM93.2 208h4.1v.5h-4.1zM93.2 209h4.1v.5h-4.1zM93.2 217.4h4.1v.5h-4.1z"/>
<path d="M103.4 208h4v.5h-4zM103.4 209h4v.5h-4zM103.4 217.4h4v.5h-4zM321.8 212.3h4v.5h-4zM177 225h4.1v.5h-4.1zM271 232.6h4.1v.5h-4.1zM27.2 253.7h4v.5h-4zM27.2 254.7h4v.5h-4zM34.8 253.7h4.1v.5h-4.1zM34.8 254.7h4.1v.5h-4.1zM42.4 253.7h4.1v.5h-4.1zM42.4 254.7h4.1v.5h-4.1z"/>
<path d="M50 253.7h4.1v.5h-4.1zM50 254.7h4.1v.5h-4.1zM57.7 253.7h4v.5h-4zM57.7 254.7h4v.5h-4zM67.8 254.7h4.1v.5h-4.1zM67.8 253.7h4.1v.5h-4.1zM126.2 255.4h4.1v.5h-4.1zM161.8 258h4v.5h-4zM250.2 253.2h25.4v10.1h-25.4zM27.2 265.6h4v.5h-4zM67.8 265.6h4.1v.5h-4.1z"/>
</g>
<g fill="none" stroke="#000" stroke-width=".42">
<path d="M82.5 72.9h17.8v22.8h-17.8zM146 117.3h22.9v8.9h-22.9zM171.4 117.3h22.9v8.9h-22.9zM49.5 170.5h5.1v2.7h-5.1zM49.5 169.6h5.1M49.5 174.2h5.1M170.2 237.9h5v17.8h-5zM110.5 243h12.7v10.2h-12.7zM219.7 253.2h55.9v17.7h-55.9zM219.7 263.3h55.9"/>
<circle cx="148.6" cy="118.6" r=".25"/>
<circle cx="151.1" cy="118.6" r=".25"/>
<circle cx="153.6" cy="118.6" r=".25"/>
<circle cx="156.2" cy="118.6" r=".25"/>
<circle cx="158.7" cy="118.6" r=".25"/>
<circle cx="161.3" cy="118.6" r=".25"/>
<circle cx="163.8" cy="118.6" r=".25"/>
<circle cx="174" cy="118.6" r=".25"/>
<circle cx="176.5" cy="118.6" r=".25"/>
<circle cx="179" cy="118.6" r=".25"/>
<circle cx="181.6" cy="118.6" r=".25"/>
<circle cx="184.1" cy="118.6" r=".25"/>
<circle cx="186.7" cy="118.6" r=".25"/>
<circle cx="189.2" cy="118.6" r=".25"/>
</g>
<path d="M49.5 47.5h320M59.7 47.5l2.5 2.5v27.9M346.7 90.6v73.7l-5.1 5.1h-88.9l-5.1 5v40.7l-2.5 2.5h-10.2l-2.5-2.5v-81.3" fill="none" stroke="#000" stroke-width=".76"/>
<g fill="#000" stroke="#000" stroke-width=".25">
<circle cx="140.9" cy="75.4" r=".51"/>
<circle cx="153.6" cy="72.9" r=".51"/>
<circle cx="153.6" cy="95.7" r=".51"/>
<circle cx="184.1" cy="85.6" r=".51"/>
<circle cx="194.3" cy="85.6" r=".51"/>
<circle cx="77.5" cy="116" r=".51"/>
<circle cx="82.5" cy="116" r=".51"/>
<circle cx="87.6" cy="116" r=".51"/>
<circle cx="54.6" cy="138.9" r=".51"/>
<circle cx="148.6" cy="131.3" r=".51"/>
<circle cx="151.1" cy="133.8" r=".51"/>
<circle cx="153.6" cy="136.3" r=".51"/>
<circle cx="156.2" cy="138.9" r=".51"/>
<circle cx="115.5" cy="159.2" r=".51"/>
<circle cx="158.7" cy="141.4" r=".51"/>
<circle cx="161.3" cy="144" r=".51"/>
<circle cx="174" cy="159.2" r=".51"/>
<circle cx="36.8" cy="177" r=".51"/>
<circle cx="52.1" cy="177" r=".51"/>
<circle cx="52.1" cy="166.8" r=".51"/>
<circle cx="120.6" cy="177" r=".51"/>
<circle cx="176.5" cy="161.7" r=".51"/>
<circle cx="179" cy="164.3" r=".51"/>
<circle cx="181.6" cy="166.8" r=".51"/>
<circle cx="184.1" cy="169.4" r=".51"/>
<circle cx="186.7" cy="171.9" r=".51"/>
<circle cx="120.6" cy="189.7" r=".51"/>
<circle cx="125.7" cy="187.1" r=".51"/>
<circle cx="130.8" cy="184.6" r=".51"/>
<circle cx="179" cy="199.8" r=".51"/>
<circle cx="186.7" cy="194.8" r=".51"/>
<circle cx="80" cy="202.4" r=".51"/>
<circle cx="85.1" cy="202.4" r=".51"/>
<circle cx="171.4" cy="204.9" r=".51"/>
<circle cx="273" cy="217.6" r=".51"/>
<circle cx="323.8" cy="207.5" r=".51"/>
<circle cx="323.8" cy="204.9" r=".51"/>
<circle cx="359.4" cy="217.6" r=".51"/>
<circle cx="179" cy="220.1" r=".51"/>
<circle cx="36.8" cy="248.1" r=".51"/>
<circle cx="44.4" cy="248.1" r=".51"/>
<circle cx="52.1" cy="248.1" r=".51"/>
<circle cx="59.7" cy="248.1" r=".51"/>
<circle cx="29.2" cy="260.8" r=".51"/>
<circle cx="36.8" cy="260.8" r=".51"/>
<circle cx="44.4" cy="260.8" r=".51"/>
<circle cx="52.1" cy="260.8" r=".51"/>
</g>
<use href="#words"/>
</svg>
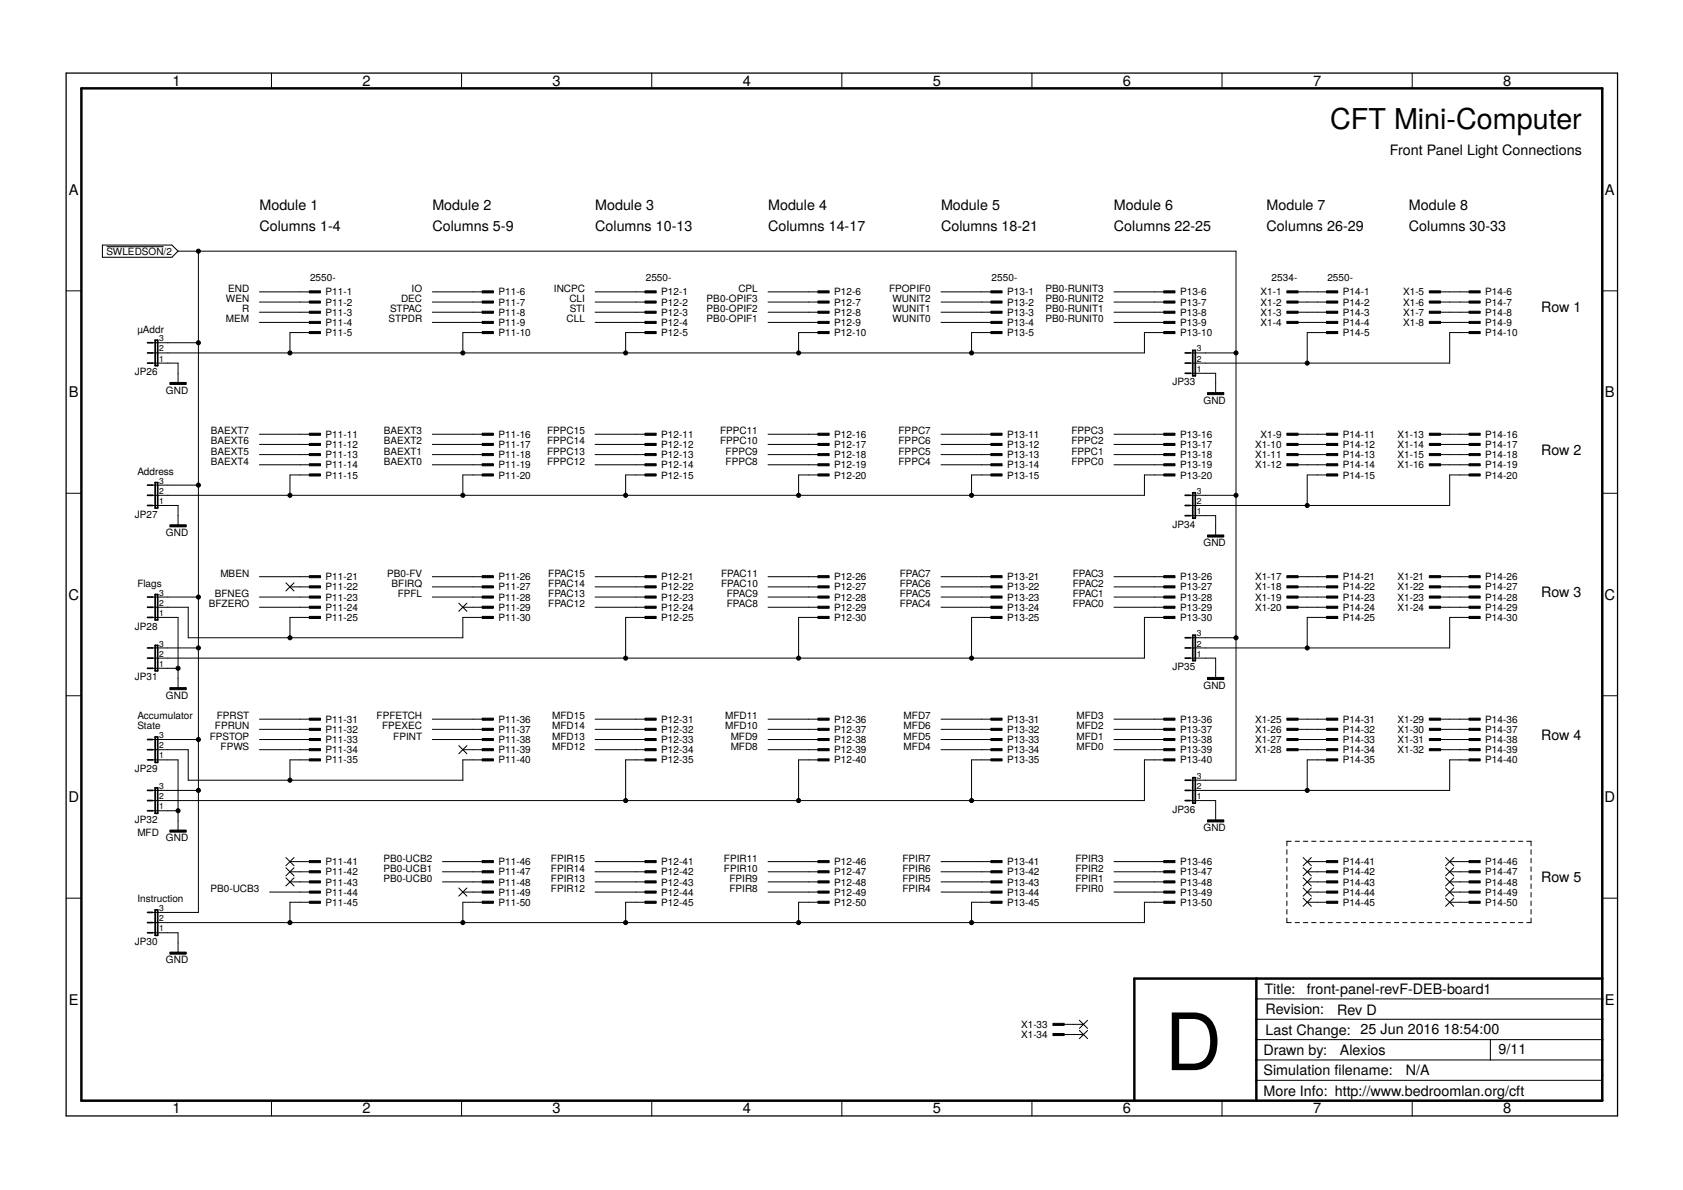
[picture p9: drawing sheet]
<svg xmlns="http://www.w3.org/2000/svg" width="420mm" height="297mm" viewBox="0 0 420 297" stroke-linecap="round" stroke-linejoin="round" font-family="sans-serif">
<defs><g id="words">
<text font-size="19.7" x="290.8" y="267.1">D</text>
<text font-size="7.2" x="332.1" y="32.2">CFT Mini-Computer</text>
<g font-size="3.7">
<text x="43" y="21.4">1</text>
<text x="90.5" y="21.4">2</text>
<text x="138" y="21.4">3</text>
<text x="185.4" y="21.4">4</text>
<text x="232.9" y="21.4">5</text>
<text x="280.3" y="21.4">6</text>
<text x="327.8" y="21.4">7</text>
<text x="375.3" y="21.4">8</text>
<text x="17.2" y="48.6">A</text>
<text x="400.7" y="48.6">A</text>
<text x="17.2" y="99.2">B</text>
<text x="400.7" y="99.2">B</text>
<text x="17.1" y="149.7">C</text>
<text x="400.6" y="149.7">C</text>
<text x="17.1" y="200.2">D</text>
<text x="400.6" y="200.2">D</text>
<text x="17.2" y="250.8">E</text>
<text x="400.7" y="250.8">E</text>
<text x="43" y="277.9">1</text>
<text x="90.5" y="277.9">2</text>
<text x="138" y="277.9">3</text>
<text x="185.4" y="277.9">4</text>
<text x="232.9" y="277.9">5</text>
<text x="280.3" y="277.9">6</text>
<text x="327.8" y="277.9">7</text>
<text x="375.3" y="277.9">8</text>
</g>
<g font-size="3.6">
<text x="347" y="38.6">Front Panel Light Connections</text>
<text x="64.8" y="52.5">Module 1</text>
<text x="107.9" y="52.5">Module 2</text>
<text x="148.6" y="52.5">Module 3</text>
<text x="191.7" y="52.5">Module 4</text>
<text x="234.9" y="52.5">Module 5</text>
<text x="278.1" y="52.5">Module 6</text>
<text x="316.2" y="52.5">Module 7</text>
<text x="351.8" y="52.5">Module 8</text>
<text x="64.8" y="57.6">Columns 1-4</text>
<text x="107.9" y="57.6">Columns 5-9</text>
<text x="148.6" y="57.6">Columns 10-13</text>
<text x="191.7" y="57.6">Columns 14-17</text>
<text x="234.9" y="57.6">Columns 18-21</text>
<text x="278.1" y="57.6">Columns 22-25</text>
<text x="316.2" y="57.6">Columns 26-29</text>
<text x="351.8" y="57.6">Columns 30-33</text>
<text x="384.8" y="77.9">Row 1</text>
<text x="384.8" y="113.5">Row 2</text>
<text x="384.8" y="149">Row 3</text>
<text x="384.8" y="184.6">Row 4</text>
<text x="384.8" y="220.1">Row 5</text>
<text x="315.7" y="248.1">Title:</text>
<text x="326.2" y="248.2">front-panel-revF-DEB-board1</text>
<text x="315.9" y="253.2">Revision:</text>
<text x="333.8" y="253.3">Rev D</text>
<text x="315.4" y="263.3">Drawn by:</text>
<text x="315.9" y="258.2">Last Change: 25 Jun 2016</text>
<text x="334.5" y="263.3">Alexios</text>
<text x="360.4" y="258.1">18:54:00</text>
<text x="374.1" y="263.2">9/11</text>
<text x="315.4" y="268.4">Simulation flename:</text>
<text x="333.2" y="268.4">i</text>
<text x="351" y="268.4">N/A</text>
<text x="315.4" y="273.5">More Info: http://www.bedroomlan.org/cft</text>
</g>
<g font-size="2.5">
<text x="26.6" y="63.6">SWLEDSON/2</text>
<text x="77.4" y="70.2">2550-</text>
<text x="161.2" y="70.2">2550-</text>
<text x="247.6" y="70.2">2550-</text>
<text x="317.5" y="70.2">2534-</text>
<text x="331.4" y="70.2">2550-</text>
<text x="56.4" y="75.4">WEN</text>
<text x="57" y="72.8">END</text>
<text x="60.4" y="77.9">R</text>
<text x="81.3" y="73.7">P11-1</text>
<text x="81.3" y="76.3">P11-2</text>
<text x="97.4" y="77.9">STPAC</text>
<text x="100.1" y="75.4">DEC</text>
<text x="102.8" y="72.8">IO</text>
<text x="124.4" y="73.7">P11-6</text>
<text x="124.4" y="76.3">P11-7</text>
<text x="138.3" y="72.8">INCPC</text>
<text x="142.1" y="75.4">CLI</text>
<text x="142.2" y="77.9">STI</text>
<text x="165.1" y="73.7">P12-1</text>
<text x="165.1" y="76.3">P12-2</text>
<text x="176.4" y="77.9">PB0-OPIF2</text>
<text x="176.4" y="75.4">PB0-OPIF3</text>
<text x="184.3" y="72.8">CPL</text>
<text x="208.3" y="73.7">P12-6</text>
<text x="208.3" y="76.3">P12-7</text>
<text x="221.9" y="72.8">FPOPIF0</text>
<text x="222.8" y="75.4">WUNIT2</text>
<text x="222.8" y="77.9">WUNIT1</text>
<text x="251.4" y="73.7">P13-1</text>
<text x="251.4" y="76.3">P13-2</text>
<text x="261" y="77.9">PB0-RUNIT1</text>
<text x="261" y="75.4">PB0-RUNIT2</text>
<text x="261" y="72.8">PB0-RUNIT3</text>
<text x="294.6" y="73.7">P13-6</text>
<text x="294.6" y="76.3">P13-7</text>
<text x="314.7" y="73.7">X1-1</text>
<text x="314.7" y="76.3">X1-2</text>
<text x="335.2" y="73.7">P14-1</text>
<text x="335.2" y="76.3">P14-2</text>
<text x="350.3" y="73.7">X1-5</text>
<text x="350.3" y="76.3">X1-6</text>
<text x="370.8" y="73.7">P14-6</text>
<text x="370.8" y="76.3">P14-7</text>
<text x="34.3" y="83">µAddr</text>
<text x="56.4" y="80.5">MEM</text>
<text x="81.3" y="78.8">P11-3</text>
<text x="81.3" y="81.4">P11-4</text>
<text x="81.3" y="83.9">P11-5</text>
<text x="97" y="80.5">STPDR</text>
<text x="124.4" y="78.8">P11-8</text>
<text x="124.4" y="81.4">P11-9</text>
<text x="124.4" y="83.9">P11-10</text>
<text x="141.4" y="80.5">CLL</text>
<text x="165.1" y="78.8">P12-3</text>
<text x="165.1" y="81.4">P12-4</text>
<text x="165.1" y="83.9">P12-5</text>
<text x="176.4" y="80.5">PB0-OPIF1</text>
<text x="208.3" y="78.8">P12-8</text>
<text x="208.3" y="81.4">P12-9</text>
<text x="208.3" y="83.9">P12-10</text>
<text x="222.8" y="80.5">WUNIT0</text>
<text x="251.4" y="78.8">P13-3</text>
<text x="251.4" y="81.4">P13-4</text>
<text x="251.4" y="83.9">P13-5</text>
<text x="261" y="80.5">PB0-RUNIT0</text>
<text x="294.6" y="78.8">P13-8</text>
<text x="294.6" y="81.4">P13-9</text>
<text x="294.6" y="83.9">P13-10</text>
<text x="314.7" y="78.8">X1-3</text>
<text x="314.7" y="81.4">X1-4</text>
<text x="335.2" y="78.8">P14-3</text>
<text x="335.2" y="81.4">P14-4</text>
<text x="335.2" y="83.9">P14-5</text>
<text x="350.3" y="78.8">X1-7</text>
<text x="350.3" y="81.4">X1-8</text>
<text x="370.8" y="78.8">P14-8</text>
<text x="370.8" y="81.4">P14-9</text>
<text x="370.8" y="83.9">P14-10</text>
<text x="33.7" y="93.7">JP26</text>
<text x="41.4" y="98.2">GND</text>
<text x="292.7" y="96.2">JP33</text>
<text x="300.5" y="100.8">GND</text>
<text x="52.7" y="108.4">BAEXT7</text>
<text x="52.7" y="110.9">BAEXT6</text>
<text x="52.7" y="113.5">BAEXT5</text>
<text x="81.3" y="109.3">P11-11</text>
<text x="81.3" y="111.8">P11-12</text>
<text x="95.8" y="108.4">BAEXT3</text>
<text x="95.8" y="110.9">BAEXT2</text>
<text x="95.8" y="113.5">BAEXT1</text>
<text x="124.4" y="109.3">P11-16</text>
<text x="124.4" y="111.8">P11-17</text>
<text x="136.6" y="108.4">FPPC15</text>
<text x="136.6" y="110.9">FPPC14</text>
<text x="136.6" y="113.5">FPPC13</text>
<text x="165.1" y="109.3">P12-11</text>
<text x="165.1" y="111.8">P12-12</text>
<text x="179.7" y="108.4">FPPC11</text>
<text x="179.7" y="110.9">FPPC10</text>
<text x="181.1" y="113.5">FPPC9</text>
<text x="208.3" y="109.3">P12-16</text>
<text x="208.3" y="111.8">P12-17</text>
<text x="224.3" y="108.4">FPPC7</text>
<text x="224.3" y="110.9">FPPC6</text>
<text x="224.3" y="113.5">FPPC5</text>
<text x="251.4" y="109.3">P13-11</text>
<text x="251.4" y="111.8">P13-12</text>
<text x="267.5" y="108.4">FPPC3</text>
<text x="267.5" y="110.9">FPPC2</text>
<text x="267.5" y="113.5">FPPC1</text>
<text x="294.6" y="109.3">P13-16</text>
<text x="294.6" y="111.8">P13-17</text>
<text x="313.3" y="111.8">X1-10</text>
<text x="314.7" y="109.3">X1-9</text>
<text x="335.2" y="109.3">P14-11</text>
<text x="335.2" y="111.8">P14-12</text>
<text x="348.9" y="109.3">X1-13</text>
<text x="348.9" y="111.8">X1-14</text>
<text x="370.8" y="109.3">P14-16</text>
<text x="370.8" y="111.8">P14-17</text>
<text x="34.3" y="118.6">Address</text>
<text x="52.7" y="116">BAEXT4</text>
<text x="81.3" y="114.4">P11-13</text>
<text x="81.3" y="116.9">P11-14</text>
<text x="81.3" y="119.5">P11-15</text>
<text x="95.8" y="116">BAEXT0</text>
<text x="124.4" y="114.4">P11-18</text>
<text x="124.4" y="116.9">P11-19</text>
<text x="124.4" y="119.5">P11-20</text>
<text x="136.6" y="116">FPPC12</text>
<text x="165.1" y="114.4">P12-13</text>
<text x="165.1" y="116.9">P12-14</text>
<text x="165.1" y="119.5">P12-15</text>
<text x="181.1" y="116">FPPC8</text>
<text x="208.3" y="114.4">P12-18</text>
<text x="208.3" y="116.9">P12-19</text>
<text x="208.3" y="119.5">P12-20</text>
<text x="224.3" y="116">FPPC4</text>
<text x="251.4" y="114.4">P13-13</text>
<text x="251.4" y="116.9">P13-14</text>
<text x="251.4" y="119.5">P13-15</text>
<text x="267.5" y="116">FPPC0</text>
<text x="294.6" y="114.4">P13-18</text>
<text x="294.6" y="116.9">P13-19</text>
<text x="294.6" y="119.5">P13-20</text>
<text x="313.3" y="114.4">X1-11</text>
<text x="313.3" y="116.9">X1-12</text>
<text x="335.2" y="114.4">P14-13</text>
<text x="335.2" y="116.9">P14-14</text>
<text x="335.2" y="119.5">P14-15</text>
<text x="348.9" y="114.4">X1-15</text>
<text x="348.9" y="116.9">X1-16</text>
<text x="370.8" y="114.4">P14-18</text>
<text x="370.8" y="116.9">P14-19</text>
<text x="370.8" y="119.5">P14-20</text>
<text x="33.7" y="129.2">JP27</text>
<text x="292.7" y="131.8">JP34</text>
<text x="41.4" y="133.8">GND</text>
<text x="300.5" y="136.3">GND</text>
<text x="55" y="144">MBEN</text>
<text x="96.6" y="144">PB0-FV</text>
<text x="136.9" y="144">FPAC15</text>
<text x="180" y="144">FPAC11</text>
<text x="224.6" y="144">FPAC7</text>
<text x="267.8" y="144">FPAC3</text>
<text x="34.3" y="146.5">Flags</text>
<text x="53.6" y="149">BFNEG</text>
<text x="81.3" y="144.8">P11-21</text>
<text x="81.3" y="147.4">P11-22</text>
<text x="81.3" y="149.9">P11-23</text>
<text x="97.8" y="146.5">BFIRQ</text>
<text x="99.3" y="149">FPFL</text>
<text x="124.4" y="144.8">P11-26</text>
<text x="124.4" y="147.4">P11-27</text>
<text x="124.4" y="149.9">P11-28</text>
<text x="136.9" y="149">FPAC13</text>
<text x="136.9" y="146.5">FPAC14</text>
<text x="165.1" y="144.8">P12-21</text>
<text x="165.1" y="147.4">P12-22</text>
<text x="165.1" y="149.9">P12-23</text>
<text x="180" y="146.5">FPAC10</text>
<text x="181.4" y="149">FPAC9</text>
<text x="208.3" y="144.8">P12-26</text>
<text x="208.3" y="147.4">P12-27</text>
<text x="208.3" y="149.9">P12-28</text>
<text x="224.6" y="149">FPAC5</text>
<text x="224.6" y="146.5">FPAC6</text>
<text x="251.4" y="144.8">P13-21</text>
<text x="251.4" y="147.4">P13-22</text>
<text x="251.4" y="149.9">P13-23</text>
<text x="267.8" y="149">FPAC1</text>
<text x="267.8" y="146.5">FPAC2</text>
<text x="294.6" y="144.8">P13-26</text>
<text x="294.6" y="147.4">P13-27</text>
<text x="294.6" y="149.9">P13-28</text>
<text x="313.3" y="144.8">X1-17</text>
<text x="313.3" y="147.4">X1-18</text>
<text x="313.3" y="149.9">X1-19</text>
<text x="335.2" y="144.8">P14-21</text>
<text x="335.2" y="147.4">P14-22</text>
<text x="335.2" y="149.9">P14-23</text>
<text x="348.9" y="144.8">X1-21</text>
<text x="348.9" y="147.4">X1-22</text>
<text x="348.9" y="149.9">X1-23</text>
<text x="370.8" y="144.8">P14-26</text>
<text x="370.8" y="147.4">P14-27</text>
<text x="370.8" y="149.9">P14-28</text>
<text x="52.1" y="151.6">BFZERO</text>
<text x="81.3" y="152.5">P11-24</text>
<text x="81.3" y="155">P11-25</text>
<text x="124.4" y="152.5">P11-29</text>
<text x="124.4" y="155">P11-30</text>
<text x="136.9" y="151.6">FPAC12</text>
<text x="165.1" y="152.5">P12-24</text>
<text x="165.1" y="155">P12-25</text>
<text x="181.4" y="151.6">FPAC8</text>
<text x="208.3" y="152.5">P12-29</text>
<text x="208.3" y="155">P12-30</text>
<text x="224.6" y="151.6">FPAC4</text>
<text x="251.4" y="152.5">P13-24</text>
<text x="251.4" y="155">P13-25</text>
<text x="267.8" y="151.6">FPAC0</text>
<text x="294.6" y="152.5">P13-29</text>
<text x="294.6" y="155">P13-30</text>
<text x="313.3" y="152.5">X1-20</text>
<text x="335.2" y="152.5">P14-24</text>
<text x="335.2" y="155">P14-25</text>
<text x="348.9" y="152.5">X1-24</text>
<text x="370.8" y="152.5">P14-29</text>
<text x="370.8" y="155">P14-30</text>
<text x="33.7" y="157.2">JP28</text>
<text x="292.7" y="167.3">JP35</text>
<text x="33.7" y="169.9">JP31</text>
<text x="300.5" y="171.9">GND</text>
<text x="34.3" y="179.5">Accumulator</text>
<text x="41.4" y="174.4">GND</text>
<text x="54.1" y="179.5">FPRST</text>
<text x="94" y="179.5">FPFETCH</text>
<text x="137.8" y="179.5">MFD15</text>
<text x="181" y="179.5">MFD11</text>
<text x="225.6" y="179.5">MFD7</text>
<text x="268.8" y="179.5">MFD3</text>
<text x="34.3" y="182.1">State</text>
<text x="52.4" y="184.6">FPSTOP</text>
<text x="53.7" y="182.1">FPRUN</text>
<text x="81.3" y="180.4">P11-31</text>
<text x="81.3" y="182.9">P11-32</text>
<text x="81.3" y="185.5">P11-33</text>
<text x="95.4" y="182.1">FPEXEC</text>
<text x="98.2" y="184.6">FPINT</text>
<text x="124.4" y="180.4">P11-36</text>
<text x="124.4" y="182.9">P11-37</text>
<text x="124.4" y="185.5">P11-38</text>
<text x="137.8" y="182.1">MFD14</text>
<text x="137.8" y="184.6">MFD13</text>
<text x="165.1" y="180.4">P12-31</text>
<text x="165.1" y="182.9">P12-32</text>
<text x="165.1" y="185.5">P12-33</text>
<text x="181" y="182.1">MFD10</text>
<text x="182.4" y="184.6">MFD9</text>
<text x="208.3" y="180.4">P12-36</text>
<text x="208.3" y="182.9">P12-37</text>
<text x="208.3" y="185.5">P12-38</text>
<text x="225.6" y="182.1">MFD6</text>
<text x="225.6" y="184.6">MFD5</text>
<text x="251.4" y="180.4">P13-31</text>
<text x="251.4" y="182.9">P13-32</text>
<text x="251.4" y="185.5">P13-33</text>
<text x="268.8" y="182.1">MFD2</text>
<text x="268.8" y="184.6">MFD1</text>
<text x="294.6" y="180.4">P13-36</text>
<text x="294.6" y="182.9">P13-37</text>
<text x="294.6" y="185.5">P13-38</text>
<text x="313.3" y="180.4">X1-25</text>
<text x="313.3" y="182.9">X1-26</text>
<text x="313.3" y="185.5">X1-27</text>
<text x="335.2" y="180.4">P14-31</text>
<text x="335.2" y="182.9">P14-32</text>
<text x="335.2" y="185.5">P14-33</text>
<text x="348.9" y="180.4">X1-29</text>
<text x="348.9" y="182.9">X1-30</text>
<text x="348.9" y="185.5">X1-31</text>
<text x="370.8" y="180.4">P14-36</text>
<text x="370.8" y="182.9">P14-37</text>
<text x="370.8" y="185.5">P14-38</text>
<text x="55.1" y="187.1">FPWS</text>
<text x="81.3" y="188">P11-34</text>
<text x="81.3" y="190.6">P11-35</text>
<text x="124.4" y="188">P11-39</text>
<text x="124.4" y="190.6">P11-40</text>
<text x="137.8" y="187.1">MFD12</text>
<text x="165.1" y="188">P12-34</text>
<text x="165.1" y="190.6">P12-35</text>
<text x="182.4" y="187.1">MFD8</text>
<text x="208.3" y="188">P12-39</text>
<text x="208.3" y="190.6">P12-40</text>
<text x="225.6" y="187.1">MFD4</text>
<text x="251.4" y="188">P13-34</text>
<text x="251.4" y="190.6">P13-35</text>
<text x="268.8" y="187.1">MFD0</text>
<text x="294.6" y="188">P13-39</text>
<text x="294.6" y="190.6">P13-40</text>
<text x="313.3" y="188">X1-28</text>
<text x="335.2" y="188">P14-34</text>
<text x="335.2" y="190.6">P14-35</text>
<text x="348.9" y="188">X1-32</text>
<text x="370.8" y="188">P14-39</text>
<text x="370.8" y="190.6">P14-40</text>
<text x="33.7" y="192.7">JP29</text>
<text x="292.7" y="202.9">JP36</text>
<text x="33.7" y="205.4">JP32</text>
<text x="34.3" y="208.7">MFD</text>
<text x="41.4" y="210">GND</text>
<text x="300.5" y="207.4">GND</text>
<text x="81.3" y="216">P11-41</text>
<text x="95.7" y="215.1">PB0-UCB2</text>
<text x="124.4" y="216">P11-46</text>
<text x="137.5" y="215.1">FPIR15</text>
<text x="165.1" y="216">P12-41</text>
<text x="180.7" y="215.1">FPIR11</text>
<text x="208.3" y="216">P12-46</text>
<text x="225.3" y="215.1">FPIR7</text>
<text x="251.4" y="216">P13-41</text>
<text x="268.5" y="215.1">FPIR3</text>
<text x="294.6" y="216">P13-46</text>
<text x="335.2" y="216">P14-41</text>
<text x="370.8" y="216">P14-46</text>
<text x="81.3" y="218.5">P11-42</text>
<text x="81.3" y="221">P11-43</text>
<text x="95.7" y="217.6">PB0-UCB1</text>
<text x="95.7" y="220.1">PB0-UCB0</text>
<text x="124.4" y="218.5">P11-47</text>
<text x="124.4" y="221">P11-48</text>
<text x="137.5" y="217.6">FPIR14</text>
<text x="137.5" y="220.1">FPIR13</text>
<text x="165.1" y="218.5">P12-42</text>
<text x="165.1" y="221">P12-43</text>
<text x="180.7" y="217.6">FPIR10</text>
<text x="182.1" y="220.1">FPIR9</text>
<text x="208.3" y="218.5">P12-47</text>
<text x="208.3" y="221">P12-48</text>
<text x="225.3" y="217.6">FPIR6</text>
<text x="225.3" y="220.1">FPIR5</text>
<text x="251.4" y="218.5">P13-42</text>
<text x="251.4" y="221">P13-43</text>
<text x="268.5" y="220.1">FPIR1</text>
<text x="268.5" y="217.6">FPIR2</text>
<text x="294.6" y="218.5">P13-47</text>
<text x="294.6" y="221">P13-48</text>
<text x="335.2" y="218.5">P14-42</text>
<text x="335.2" y="221">P14-43</text>
<text x="370.8" y="218.5">P14-47</text>
<text x="370.8" y="221">P14-48</text>
<text x="34.3" y="225.2">Instruction</text>
<text x="52.5" y="222.7">PB0-UCB3</text>
<text x="81.3" y="223.6">P11-44</text>
<text x="81.3" y="226.1">P11-45</text>
<text x="124.4" y="223.6">P11-49</text>
<text x="124.4" y="226.1">P11-50</text>
<text x="137.5" y="222.7">FPIR12</text>
<text x="165.1" y="223.6">P12-44</text>
<text x="165.1" y="226.1">P12-45</text>
<text x="182.1" y="222.7">FPIR8</text>
<text x="208.3" y="223.6">P12-49</text>
<text x="208.3" y="226.1">P12-50</text>
<text x="225.3" y="222.7">FPIR4</text>
<text x="251.4" y="223.6">P13-44</text>
<text x="251.4" y="226.1">P13-45</text>
<text x="268.5" y="222.7">FPIR0</text>
<text x="294.6" y="223.6">P13-49</text>
<text x="294.6" y="226.1">P13-50</text>
<text x="335.2" y="223.6">P14-44</text>
<text x="335.2" y="226.1">P14-45</text>
<text x="370.8" y="223.6">P14-49</text>
<text x="370.8" y="226.1">P14-50</text>
<text x="33.7" y="235.9">JP30</text>
<text x="41.4" y="240.5">GND</text>
<text x="254.9" y="256.6">X1-33</text>
<text x="254.9" y="259.1">X1-34</text>
</g>
<g font-size="2.1">
<text x="39.7" y="87.7">2</text>
<text x="39.7" y="85.2">3</text>
<text x="298.8" y="87.7">3</text>
<text x="39.7" y="90.3">1</text>
<text x="298.8" y="92.8">1</text>
<text x="298.8" y="90.3">2</text>
<text x="39.7" y="125.8">1</text>
<text x="39.7" y="123.3">2</text>
<text x="39.7" y="120.7">3</text>
<text x="298.8" y="125.8">2</text>
<text x="298.8" y="123.3">3</text>
<text x="298.8" y="128.4">1</text>
<text x="39.7" y="148.7">3</text>
<text x="39.7" y="153.8">1</text>
<text x="39.7" y="151.2">2</text>
<text x="39.7" y="161.4">3</text>
<text x="298.8" y="161.4">2</text>
<text x="298.8" y="158.8">3</text>
<text x="39.7" y="166.5">1</text>
<text x="39.7" y="163.9">2</text>
<text x="298.8" y="163.9">1</text>
<text x="39.7" y="184.2">3</text>
<text x="39.7" y="189.3">1</text>
<text x="39.7" y="186.8">2</text>
<text x="39.7" y="196.9">3</text>
<text x="298.8" y="196.9">2</text>
<text x="298.8" y="194.4">3</text>
<text x="39.7" y="202">1</text>
<text x="39.7" y="199.5">2</text>
<text x="298.8" y="199.5">1</text>
<text x="39.7" y="227.4">3</text>
<text x="39.7" y="232.5">1</text>
<text x="39.7" y="229.9">2</text>
</g>
</g></defs>
<g fill="none" stroke="#000" stroke-width=".25">
<path d="M67.8 18.2v3.9M115.2 18.2v3.9M162.7 18.2v3.9M210.2 18.2v3.9M257.6 18.2v3.9M305.1 18.2v3.9M352.6 18.2v3.9M20.3 22.1h379.7v252.6h-379.7zM16.5 72.6h3.8M25.6 61.2h17.3l1.5 1.5-1.5 1.5h-17.3zM26.6 61.6h14.2M44.4 62.7h264.2v132.1h-11.5"/>
<path d="M49.5 62.7v165.1h-11.4M64.8 72.9h12.7M64.8 75.4h12.7M64.8 77.9h12.7M107.9 72.9h12.7M107.9 75.4h12.7M107.9 77.9h12.7M148.6 72.9h12.7M148.6 75.4h12.7M148.6 77.9h12.7M191.7 72.9h12.7M191.7 75.4h12.7"/>
<path d="M191.7 77.9h12.7M234.9 72.9h12.7M234.9 75.4h12.7M234.9 77.9h12.7M278.1 72.9h12.7M278.1 75.4h12.7M278.1 77.9h12.7M323.8 72.9h7.6M323.8 75.4h7.6M323.8 77.9h7.6M359.4 72.9h7.6M359.4 75.4h7.6"/>
<path d="M359.4 77.9h7.6M400 72.6h3.8M38.1 90.6h6.3v5.1M38.1 85.6h11.4M42.5 95.7h3.9M64.8 80.5h12.7M77.5 83h-5.1v5.1M107.9 80.5h12.7M120.6 83h-5.1v5.1M148.6 80.5h12.7M161.3 83h-5.1v5.1M191.7 80.5h12.7"/>
<path d="M204.4 83h-5v5.1M234.9 80.5h12.7M247.6 83h-5.1v5.1M278.1 80.5h12.7M290.8 83h-5.1v5.1h-247.6M297.1 93.2h6.4v5.1M297.1 88.1h11.5M301.6 98.3h3.8M323.8 80.5h7.6M331.4 83h-5.1v7.6M359.4 80.5h7.6M367 83h-5.1v7.6h-64.8"/>
<path d="M64.8 108.4h12.7M64.8 110.9h12.7M64.8 113.5h12.7M64.8 116h12.7M77.5 118.6h-5.1v5M107.9 108.4h12.7M107.9 110.9h12.7M107.9 113.5h12.7M107.9 116h12.7M120.6 118.6h-5.1v5M148.6 108.4h12.7M148.6 110.9h12.7"/>
<path d="M148.6 113.5h12.7M148.6 116h12.7M161.3 118.6h-5.1v5M191.7 108.4h12.7M191.7 110.9h12.7M191.7 113.5h12.7M191.7 116h12.7M204.4 118.6h-5v5M234.9 108.4h12.7M234.9 110.9h12.7M234.9 113.5h12.7M234.9 116h12.7"/>
<path d="M247.6 118.6h-5.1v5M278.1 108.4h12.7M278.1 110.9h12.7M278.1 113.5h12.7M278.1 116h12.7M290.8 118.6h-5.1v5h-247.6M323.8 108.4h7.6M323.8 110.9h7.6M323.8 113.5h7.6M323.8 116h7.6M331.4 118.6h-5.1v7.6M359.4 108.4h7.6"/>
<path d="M359.4 110.9h7.6M359.4 113.5h7.6M359.4 116h7.6M367 118.6h-5.1v7.6h-64.8M16.5 123.1h3.8M38.1 126.2h6.3v5.1M38.1 121.1h11.4M42.5 131.3h3.9M297.1 128.7h6.4v5.1M297.1 123.6h11.5M301.6 133.8h3.8M400 123.1h3.8"/>
<path d="M38.1 149h11.4M38.1 151.6h8.9v7.6h68.5v-5.1h5.1M38.1 154.1h6.3v17.8M64.8 144h12.7M64.8 149h12.7M64.8 151.6h12.7M71.4 145.5l2 2M72.4 146.5h5.1M73.4 145.5l-2 2M77.5 154.1h-5.1v5.1M107.9 144h12.7M107.9 146.5h12.7"/>
<path d="M107.9 149h12.7M114.5 150.6l2.1 2M115.5 151.6h5.1M116.6 150.6l-2.1 2M148.6 144h12.7M148.6 146.5h12.7M148.6 149h12.7M148.6 151.6h12.7M161.3 154.1h-5.1v10.2M191.7 144h12.7M191.7 146.5h12.7M191.7 149h12.7"/>
<path d="M191.7 151.6h12.7M204.4 154.1h-5v10.2M234.9 144h12.7M234.9 146.5h12.7M234.9 149h12.7M234.9 151.6h12.7M247.6 154.1h-5.1v10.2M278.1 144h12.7M278.1 146.5h12.7M278.1 149h12.7M278.1 151.6h12.7M290.8 154.1h-5.1v10.2h-247.6"/>
<path d="M297.1 159.2h11.5M323.8 144h7.6M323.8 146.5h7.6M323.8 149h7.6M323.8 151.6h7.6M331.4 154.1h-5.1v7.6M359.4 144h7.6M359.4 146.5h7.6M359.4 149h7.6M359.4 151.6h7.6M367 154.1h-5.1v7.6h-64.8M16.5 173.7h3.8"/>
<path d="M38.1 161.7h11.4M38.1 166.8h6.3M42.5 171.9h3.9M64.8 179.5h12.7M107.9 179.5h12.7M148.6 179.5h12.7M191.7 179.5h12.7M234.9 179.5h12.7M278.1 179.5h12.7M297.1 164.3h6.4v5.1M301.6 169.4h3.8M323.8 179.5h7.6"/>
<path d="M359.4 179.5h7.6M400 173.7h3.8M38.1 184.6h11.4M38.1 187.1h8.9v7.7h68.5v-5.1h5.1M38.1 189.7h6.3v17.8M38.1 197.3h11.4M64.8 182.1h12.7M64.8 184.6h12.7M64.8 187.1h12.7M77.5 189.7h-5.1v5.1M107.9 182.1h12.7M107.9 184.6h12.7"/>
<path d="M114.5 186.1l2.1 2.1M115.5 187.1h5.1M116.6 186.1l-2.1 2.1M148.6 182.1h12.7M148.6 184.6h12.7M148.6 187.1h12.7M161.3 189.7h-5.1v10.1M191.7 182.1h12.7M191.7 184.6h12.7M191.7 187.1h12.7M204.4 189.7h-5v10.1M234.9 182.1h12.7"/>
<path d="M234.9 184.6h12.7M234.9 187.1h12.7M247.6 189.7h-5.1v10.1M278.1 182.1h12.7M278.1 184.6h12.7M278.1 187.1h12.7M290.8 189.7h-5.1v10.1h-247.6M297.1 199.8h6.4v5.1M323.8 182.1h7.6M323.8 184.6h7.6M323.8 187.1h7.6M331.4 189.7h-5.1v7.6"/>
<path d="M359.4 182.1h7.6M359.4 184.6h7.6M359.4 187.1h7.6M367 189.7h-5.1v7.6h-64.8M38.1 202.4h6.3M42.5 207.5h3.9M71.4 214.1l2 2M71.4 216.6l2 2M71.4 219.1l2 2M72.4 215.1h5.1M72.4 217.6h5.1M73.4 214.1l-2 2"/>
<path d="M73.4 216.6l-2 2M73.4 219.1l-2 2M110.5 215.1h10.1M110.5 217.6h10.1M148.6 215.1h12.7M148.6 217.6h12.7M191.7 215.1h12.7M191.7 217.6h12.7M234.9 215.1h12.7M234.9 217.6h12.7M278.1 215.1h12.7M278.1 217.6h12.7"/>
<path d="M301.6 204.9h3.8M321.3 212.1v1.2M321.3 214.2v1.2M321.3 216.4v1.1M321.3 218.5v1.1M322.3 210h-1v1.1M323.3 210h1.1M325.3 214.1l2.1 2M325.3 216.6l2.1 2M325.3 219.1l2.1 2M325.4 210h1.1M326.3 215.1h5.1"/>
<path d="M326.3 217.6h5.1M327.4 214.1l-2.1 2M327.4 216.6l-2.1 2M327.4 219.1l-2.1 2M327.5 210h1M329.5 210h1.1M331.6 210h1.1M333.7 210h1M335.7 210h1.1M337.8 210h1.1M339.9 210h1M341.9 210h1.1"/>
<path d="M344 210h1.1M346.1 210h1M348.1 210h1.1M350.2 210h1.1M352.3 210h1M354.3 210h1.1M356.4 210h1M358.4 210h1.1M360.5 210h1.1M360.9 214.1l2 2M360.9 216.6l2 2M360.9 219.1l2 2"/>
<path d="M361.9 215.1h5.1M361.9 217.6h5.1M362.6 210h1M362.9 214.1l-2 2M362.9 216.6l-2 2M362.9 219.1l-2 2M364.6 210h1.1M366.7 210h1.1M368.8 210h1M370.8 210h1.1M372.9 210h1.1M375 210h1"/>
<path d="M377 210h1.1M379.1 210h1.1M381.2 210h1v1.1M382.2 212.1v1.2M382.2 214.2v1.2M382.2 216.4v1.1M382.2 218.5v1.1M16.5 224.2h3.8M38.1 232.8h6.3v5.1M42.5 237.9h3.9M67.3 222.7h10.2M72.4 220.1h5.1"/>
<path d="M77.5 225.2h-5.1v5.1M110.5 220.1h10.1M114.5 221.7l2.1 2M115.5 222.7h5.1M116.6 221.7l-2.1 2M120.6 225.2h-5.1v5.1M148.6 220.1h12.7M148.6 222.7h12.7M161.3 225.2h-5.1v5.1M191.7 220.1h12.7M191.7 222.7h12.7M204.4 225.2h-5v5.1"/>
<path d="M234.9 220.1h12.7M234.9 222.7h12.7M247.6 225.2h-5.1v5.1M278.1 220.1h12.7M278.1 222.7h12.7M290.8 225.2h-5.1v5.1h-247.6M321.3 229.2v1.1h1M321.3 220.6v1.2M321.3 222.8v1.1M321.3 224.9v1.1M321.3 227v1.2M323.3 230.3h1.1"/>
<path d="M325.3 221.7l2.1 2M325.3 224.2l2.1 2M325.4 230.3h1.1M326.3 220.1h5.1M326.3 222.7h5.1M326.3 225.2h5.1M327.4 221.7l-2.1 2M327.4 224.2l-2.1 2M327.5 230.3h1M329.5 230.3h1.1M331.6 230.3h1.1M333.7 230.3h1"/>
<path d="M335.7 230.3h1.1M337.8 230.3h1.1M339.9 230.3h1M341.9 230.3h1.1M344 230.3h1.1M346.1 230.3h1M348.1 230.3h1.1M350.2 230.3h1.1M352.3 230.3h1M354.3 230.3h1.1M356.4 230.3h1M358.4 230.3h1.1"/>
<path d="M360.5 230.3h1.1M360.9 221.7l2 2M360.9 224.2l2 2M361.9 220.1h5.1M361.9 222.7h5.1M361.9 225.2h5.1M362.6 230.3h1M362.9 221.7l-2 2M362.9 224.2l-2 2M364.6 230.3h1.1M366.7 230.3h1.1M368.8 230.3h1"/>
<path d="M370.8 230.3h1.1M372.9 230.3h1.1M375 230.3h1M377 230.3h1.1M379.1 230.3h1.1M382.2 220.6v1.2M382.2 222.8v1.1M382.2 224.9v1.1M382.2 227v1.2M382.2 229.2v1.1h-1M400 224.2h3.8M265.4 255.7h5.1"/>
<path d="M265.4 258.2h5.1M269.5 254.7l2 2M269.5 257.2l2 2M271.5 254.7l-2 2M271.5 257.2l-2 2M313.6 249.3h86.4M313.6 254.4h86.4M313.6 259.5h86.4M372.1 259.5v5.1M67.8 274.7v3.9M115.2 274.7v3.9M162.7 274.7v3.9"/>
<path d="M210.2 274.7v3.9M257.6 274.7v3.9M305.1 274.7v3.9M313.6 264.6h86.4M313.6 269.7h86.4M352.6 274.7v3.9M400 274.6h.1"/>
</g>
<path d="M20.3 22.1h379.7v252.6h-379.7zM313.6 244.3v30.4M400 244.3h-116.8v30.4" fill="none" stroke="#000" stroke-width=".61"/>
<path d="M16.5 18.2h387.3v260.4h-387.3z" fill="none" stroke="#000" stroke-width=".32"/>
<g fill="#000" stroke="#000" stroke-width=".25">
<path d="M77.2 72.6h2.8v.5h-2.8zM77.2 75.1h2.8v.5h-2.8zM77.2 77.7h2.8v.5h-2.8zM120.4 72.6h2.8v.5h-2.8zM120.4 75.1h2.8v.5h-2.8zM120.4 77.7h2.8v.5h-2.8zM161 72.6h2.8v.5h-2.8zM161 75.1h2.8v.5h-2.8zM161 77.7h2.8v.5h-2.8zM204.2 72.6h2.8v.5h-2.8zM204.2 75.1h2.8v.5h-2.8zM204.2 77.7h2.8v.5h-2.8z"/>
<path d="M247.4 72.6h2.8v.5h-2.8zM247.4 75.1h2.8v.5h-2.8zM247.4 77.7h2.8v.5h-2.8zM290.5 72.6h2.8v.5h-2.8zM290.5 75.1h2.8v.5h-2.8zM290.5 77.7h2.8v.5h-2.8zM321.3 72.6h2.8v.5h-2.8zM321.3 75.1h2.8v.5h-2.8zM321.3 77.7h2.8v.5h-2.8zM331.2 72.6h2.8v.5h-2.8zM331.2 75.1h2.8v.5h-2.8zM331.2 77.7h2.8v.5h-2.8z"/>
<path d="M356.8 72.6h2.8v.5h-2.8zM356.8 75.1h2.8v.5h-2.8zM356.8 77.7h2.8v.5h-2.8zM366.7 72.6h2.8v.5h-2.8zM366.7 75.1h2.8v.5h-2.8zM366.7 77.7h2.8v.5h-2.8zM42.4 95.5h4.1v.5h-4.1zM77.2 80.2h2.8v.5h-2.8zM77.2 82.8h2.8v.5h-2.8zM120.4 80.2h2.8v.5h-2.8zM120.4 82.8h2.8v.5h-2.8zM161 80.2h2.8v.5h-2.8z"/>
<path d="M161 82.8h2.8v.5h-2.8zM204.2 80.2h2.8v.5h-2.8zM204.2 82.8h2.8v.5h-2.8zM247.4 80.2h2.8v.5h-2.8zM247.4 82.8h2.8v.5h-2.8zM290.5 80.2h2.8v.5h-2.8zM290.5 82.8h2.8v.5h-2.8zM301.5 98h4v.5h-4zM321.3 80.2h2.8v.5h-2.8zM331.2 80.2h2.8v.5h-2.8zM331.2 82.8h2.8v.5h-2.8zM356.8 80.2h2.8v.5h-2.8z"/>
<path d="M366.7 80.2h2.8v.5h-2.8zM366.7 82.8h2.8v.5h-2.8zM77.2 108.1h2.8v.5h-2.8zM77.2 110.7h2.8v.5h-2.8zM77.2 113.2h2.8v.5h-2.8zM77.2 115.8h2.8v.5h-2.8zM77.2 118.3h2.8v.5h-2.8zM120.4 108.1h2.8v.5h-2.8zM120.4 110.7h2.8v.5h-2.8zM120.4 113.2h2.8v.5h-2.8zM120.4 115.8h2.8v.5h-2.8zM120.4 118.3h2.8v.5h-2.8z"/>
<path d="M161 108.1h2.8v.5h-2.8zM161 110.7h2.8v.5h-2.8zM161 113.2h2.8v.5h-2.8zM161 115.8h2.8v.5h-2.8zM161 118.3h2.8v.5h-2.8zM204.2 108.1h2.8v.5h-2.8zM204.2 110.7h2.8v.5h-2.8zM204.2 113.2h2.8v.5h-2.8zM204.2 115.8h2.8v.5h-2.8zM204.2 118.3h2.8v.5h-2.8zM247.4 108.1h2.8v.5h-2.8zM247.4 110.7h2.8v.5h-2.8z"/>
<path d="M247.4 113.2h2.8v.5h-2.8zM247.4 115.8h2.8v.5h-2.8zM247.4 118.3h2.8v.5h-2.8zM290.5 108.1h2.8v.5h-2.8zM290.5 110.7h2.8v.5h-2.8zM290.5 113.2h2.8v.5h-2.8zM290.5 115.8h2.8v.5h-2.8zM290.5 118.3h2.8v.5h-2.8zM321.3 108.1h2.8v.5h-2.8zM321.3 110.7h2.8v.5h-2.8zM321.3 113.2h2.8v.5h-2.8zM321.3 115.8h2.8v.5h-2.8z"/>
<path d="M331.2 108.1h2.8v.5h-2.8zM331.2 110.7h2.8v.5h-2.8zM331.2 113.2h2.8v.5h-2.8zM331.2 115.8h2.8v.5h-2.8zM331.2 118.3h2.8v.5h-2.8zM356.8 108.1h2.8v.5h-2.8zM356.8 110.7h2.8v.5h-2.8zM356.8 113.2h2.8v.5h-2.8zM356.8 115.8h2.8v.5h-2.8zM366.7 108.1h2.8v.5h-2.8zM366.7 110.7h2.8v.5h-2.8zM366.7 113.2h2.8v.5h-2.8z"/>
<path d="M366.7 115.8h2.8v.5h-2.8zM366.7 118.3h2.8v.5h-2.8zM42.4 131h4.1v.5h-4.1zM301.5 133.5h4v.5h-4zM77.2 143.7h2.8v.5h-2.8zM77.2 146.2h2.8v.5h-2.8zM77.2 148.8h2.8v.5h-2.8zM77.2 151.3h2.8v.5h-2.8zM77.2 153.9h2.8v.5h-2.8zM120.4 143.7h2.8v.5h-2.8zM120.4 146.2h2.8v.5h-2.8zM120.4 148.8h2.8v.5h-2.8z"/>
<path d="M120.4 151.3h2.8v.5h-2.8zM120.4 153.9h2.8v.5h-2.8zM161 143.7h2.8v.5h-2.8zM161 146.2h2.8v.5h-2.8zM161 148.8h2.8v.5h-2.8zM161 151.3h2.8v.5h-2.8zM161 153.9h2.8v.5h-2.8zM204.2 143.7h2.8v.5h-2.8zM204.2 146.2h2.8v.5h-2.8zM204.2 148.8h2.8v.5h-2.8zM204.2 151.3h2.8v.5h-2.8zM204.2 153.9h2.8v.5h-2.8z"/>
<path d="M247.4 143.7h2.8v.5h-2.8zM247.4 146.2h2.8v.5h-2.8zM247.4 148.8h2.8v.5h-2.8zM247.4 151.3h2.8v.5h-2.8zM247.4 153.9h2.8v.5h-2.8zM290.5 143.7h2.8v.5h-2.8zM290.5 146.2h2.8v.5h-2.8zM290.5 148.8h2.8v.5h-2.8zM290.5 151.3h2.8v.5h-2.8zM290.5 153.9h2.8v.5h-2.8zM321.3 143.7h2.8v.5h-2.8zM321.3 146.2h2.8v.5h-2.8z"/>
<path d="M321.3 148.8h2.8v.5h-2.8zM321.3 151.3h2.8v.5h-2.8zM331.2 143.7h2.8v.5h-2.8zM331.2 146.2h2.8v.5h-2.8zM331.2 148.8h2.8v.5h-2.8zM331.2 151.3h2.8v.5h-2.8zM331.2 153.9h2.8v.5h-2.8zM356.8 143.7h2.8v.5h-2.8zM356.8 146.2h2.8v.5h-2.8zM356.8 148.8h2.8v.5h-2.8zM356.8 151.3h2.8v.5h-2.8zM366.7 143.7h2.8v.5h-2.8z"/>
<path d="M366.7 146.2h2.8v.5h-2.8zM366.7 148.8h2.8v.5h-2.8zM366.7 151.3h2.8v.5h-2.8zM366.7 153.9h2.8v.5h-2.8zM42.4 171.6h4.1v.5h-4.1zM77.2 179.3h2.8v.5h-2.8zM120.4 179.3h2.8v.5h-2.8zM161 179.3h2.8v.5h-2.8zM204.2 179.3h2.8v.5h-2.8zM247.4 179.3h2.8v.5h-2.8zM290.5 179.3h2.8v.5h-2.8zM301.5 169.1h4v.5h-4z"/>
<path d="M321.3 179.3h2.8v.5h-2.8zM331.2 179.3h2.8v.5h-2.8zM356.8 179.3h2.8v.5h-2.8zM366.7 179.3h2.8v.5h-2.8zM77.2 181.8h2.8v.5h-2.8zM77.2 184.3h2.8v.5h-2.8zM77.2 186.9h2.8v.5h-2.8zM77.2 189.4h2.8v.5h-2.8zM120.4 181.8h2.8v.5h-2.8zM120.4 184.3h2.8v.5h-2.8zM120.4 186.9h2.8v.5h-2.8zM120.4 189.4h2.8v.5h-2.8z"/>
<path d="M161 181.8h2.8v.5h-2.8zM161 184.3h2.8v.5h-2.8zM161 186.9h2.8v.5h-2.8zM161 189.4h2.8v.5h-2.8zM204.2 181.8h2.8v.5h-2.8zM204.2 184.3h2.8v.5h-2.8zM204.2 186.9h2.8v.5h-2.8zM204.2 189.4h2.8v.5h-2.8zM247.4 181.8h2.8v.5h-2.8zM247.4 184.3h2.8v.5h-2.8zM247.4 186.9h2.8v.5h-2.8zM247.4 189.4h2.8v.5h-2.8z"/>
<path d="M290.5 181.8h2.8v.5h-2.8zM290.5 184.3h2.8v.5h-2.8zM290.5 186.9h2.8v.5h-2.8zM290.5 189.4h2.8v.5h-2.8zM321.3 181.8h2.8v.5h-2.8zM321.3 184.3h2.8v.5h-2.8zM321.3 186.9h2.8v.5h-2.8zM331.2 181.8h2.8v.5h-2.8zM331.2 184.3h2.8v.5h-2.8zM331.2 186.9h2.8v.5h-2.8zM331.2 189.4h2.8v.5h-2.8zM356.8 181.8h2.8v.5h-2.8z"/>
<path d="M356.8 184.3h2.8v.5h-2.8zM356.8 186.9h2.8v.5h-2.8zM366.7 181.8h2.8v.5h-2.8zM366.7 184.3h2.8v.5h-2.8zM366.7 186.9h2.8v.5h-2.8zM366.7 189.4h2.8v.5h-2.8zM42.4 207.2h4.1v.5h-4.1zM77.2 214.8h2.8v.5h-2.8zM77.2 217.4h2.8v.5h-2.8zM77.2 219.9h2.8v.5h-2.8zM120.4 214.8h2.8v.5h-2.8zM120.4 217.4h2.8v.5h-2.8z"/>
<path d="M120.4 219.9h2.8v.5h-2.8zM161 214.8h2.8v.5h-2.8zM161 217.4h2.8v.5h-2.8zM161 219.9h2.8v.5h-2.8zM204.2 214.8h2.8v.5h-2.8zM204.2 217.4h2.8v.5h-2.8zM204.2 219.9h2.8v.5h-2.8zM247.4 214.8h2.8v.5h-2.8zM247.4 217.4h2.8v.5h-2.8zM247.4 219.9h2.8v.5h-2.8zM290.5 214.8h2.8v.5h-2.8zM290.5 217.4h2.8v.5h-2.8z"/>
<path d="M290.5 219.9h2.8v.5h-2.8zM301.5 204.7h4v.5h-4zM331.2 214.8h2.8v.5h-2.8zM331.2 217.4h2.8v.5h-2.8zM331.2 219.9h2.8v.5h-2.8zM366.7 214.8h2.8v.5h-2.8zM366.7 217.4h2.8v.5h-2.8zM366.7 219.9h2.8v.5h-2.8zM42.4 237.7h4.1v.5h-4.1zM77.2 222.4h2.8v.5h-2.8zM77.2 225h2.8v.5h-2.8zM120.4 222.4h2.8v.5h-2.8z"/>
<path d="M120.4 225h2.8v.5h-2.8zM161 222.4h2.8v.5h-2.8zM161 225h2.8v.5h-2.8zM204.2 222.4h2.8v.5h-2.8zM204.2 225h2.8v.5h-2.8zM247.4 222.4h2.8v.5h-2.8zM247.4 225h2.8v.5h-2.8zM290.5 222.4h2.8v.5h-2.8zM290.5 225h2.8v.5h-2.8zM331.2 222.4h2.8v.5h-2.8zM331.2 225h2.8v.5h-2.8zM366.7 222.4h2.8v.5h-2.8z"/>
<path d="M366.7 225h2.8v.5h-2.8zM262.9 255.4h2.8v.5h-2.8zM262.9 258h2.8v.5h-2.8z"/>
</g>
<g fill="none" stroke="#000" stroke-width=".42">
<path d="M36.8 85.6h1.3M36.8 88.1h1.3M36.8 90.6h1.3M38.7 84.9h.7v6.4h-.7zM295.9 88.1h1.2M295.9 90.6h1.2M295.9 93.2h1.2M297.8 87.5h.6v6.3h-.6zM36.8 121.1h1.3M36.8 123.6h1.3M36.8 126.2h1.3M38.7 120.5h.7v6.3h-.7z"/>
<path d="M295.9 123.6h1.2M295.9 126.2h1.2M295.9 128.7h1.2M297.8 123h.6v6.3h-.6zM36.8 149h1.3M36.8 151.6h1.3M36.8 154.1h1.3M38.7 148.4h.7v6.3h-.7zM295.9 159.2h1.2M297.8 158.6h.6v6.3h-.6zM36.8 161.7h1.3M36.8 164.3h1.3"/>
<path d="M36.8 166.8h1.3M38.7 161.1h.7v6.3h-.7zM295.9 161.7h1.2M295.9 164.3h1.2M36.8 184.6h1.3M36.8 187.1h1.3M36.8 189.7h1.3M36.8 197.3h1.3M36.8 199.8h1.3M38.7 184h.7v6.3h-.7zM38.7 196.7h.7v6.3h-.7zM295.9 197.3h1.2"/>
<path d="M295.9 199.8h1.2M295.9 194.8h1.2M297.8 194.1h.6v6.4h-.6zM36.8 202.4h1.3M36.8 227.8h1.3M36.8 230.3h1.3M36.8 232.8h1.3M38.7 227.1h.7v6.4h-.7z"/>
</g>
<g fill="#000" stroke="#000" stroke-width=".25">
<circle cx="49.5" cy="62.7" r=".51"/>
<circle cx="49.5" cy="85.6" r=".51"/>
<circle cx="72.4" cy="88.1" r=".51"/>
<circle cx="115.5" cy="88.1" r=".51"/>
<circle cx="156.2" cy="88.1" r=".51"/>
<circle cx="199.4" cy="88.1" r=".51"/>
<circle cx="242.5" cy="88.1" r=".51"/>
<circle cx="308.6" cy="88.1" r=".51"/>
<circle cx="326.3" cy="90.6" r=".51"/>
<circle cx="49.5" cy="121.1" r=".51"/>
<circle cx="72.4" cy="123.6" r=".51"/>
<circle cx="115.5" cy="123.6" r=".51"/>
<circle cx="156.2" cy="123.6" r=".51"/>
<circle cx="199.4" cy="123.6" r=".51"/>
<circle cx="242.5" cy="123.6" r=".51"/>
<circle cx="308.6" cy="123.6" r=".51"/>
<circle cx="326.3" cy="126.2" r=".51"/>
<circle cx="49.5" cy="149" r=".51"/>
<circle cx="72.4" cy="159.2" r=".51"/>
<circle cx="308.6" cy="159.2" r=".51"/>
<circle cx="44.4" cy="166.8" r=".51"/>
<circle cx="49.5" cy="161.7" r=".51"/>
<circle cx="156.2" cy="164.3" r=".51"/>
<circle cx="199.4" cy="164.3" r=".51"/>
<circle cx="242.5" cy="164.3" r=".51"/>
<circle cx="326.3" cy="161.7" r=".51"/>
<circle cx="49.5" cy="184.6" r=".51"/>
<circle cx="49.5" cy="197.3" r=".51"/>
<circle cx="72.4" cy="194.8" r=".51"/>
<circle cx="156.2" cy="199.8" r=".51"/>
<circle cx="199.4" cy="199.8" r=".51"/>
<circle cx="242.5" cy="199.8" r=".51"/>
<circle cx="326.3" cy="197.3" r=".51"/>
<circle cx="44.4" cy="202.4" r=".51"/>
<circle cx="72.4" cy="230.3" r=".51"/>
<circle cx="115.5" cy="230.3" r=".51"/>
<circle cx="156.2" cy="230.3" r=".51"/>
<circle cx="199.4" cy="230.3" r=".51"/>
<circle cx="242.5" cy="230.3" r=".51"/>
</g>
<use href="#words"/>
</svg>
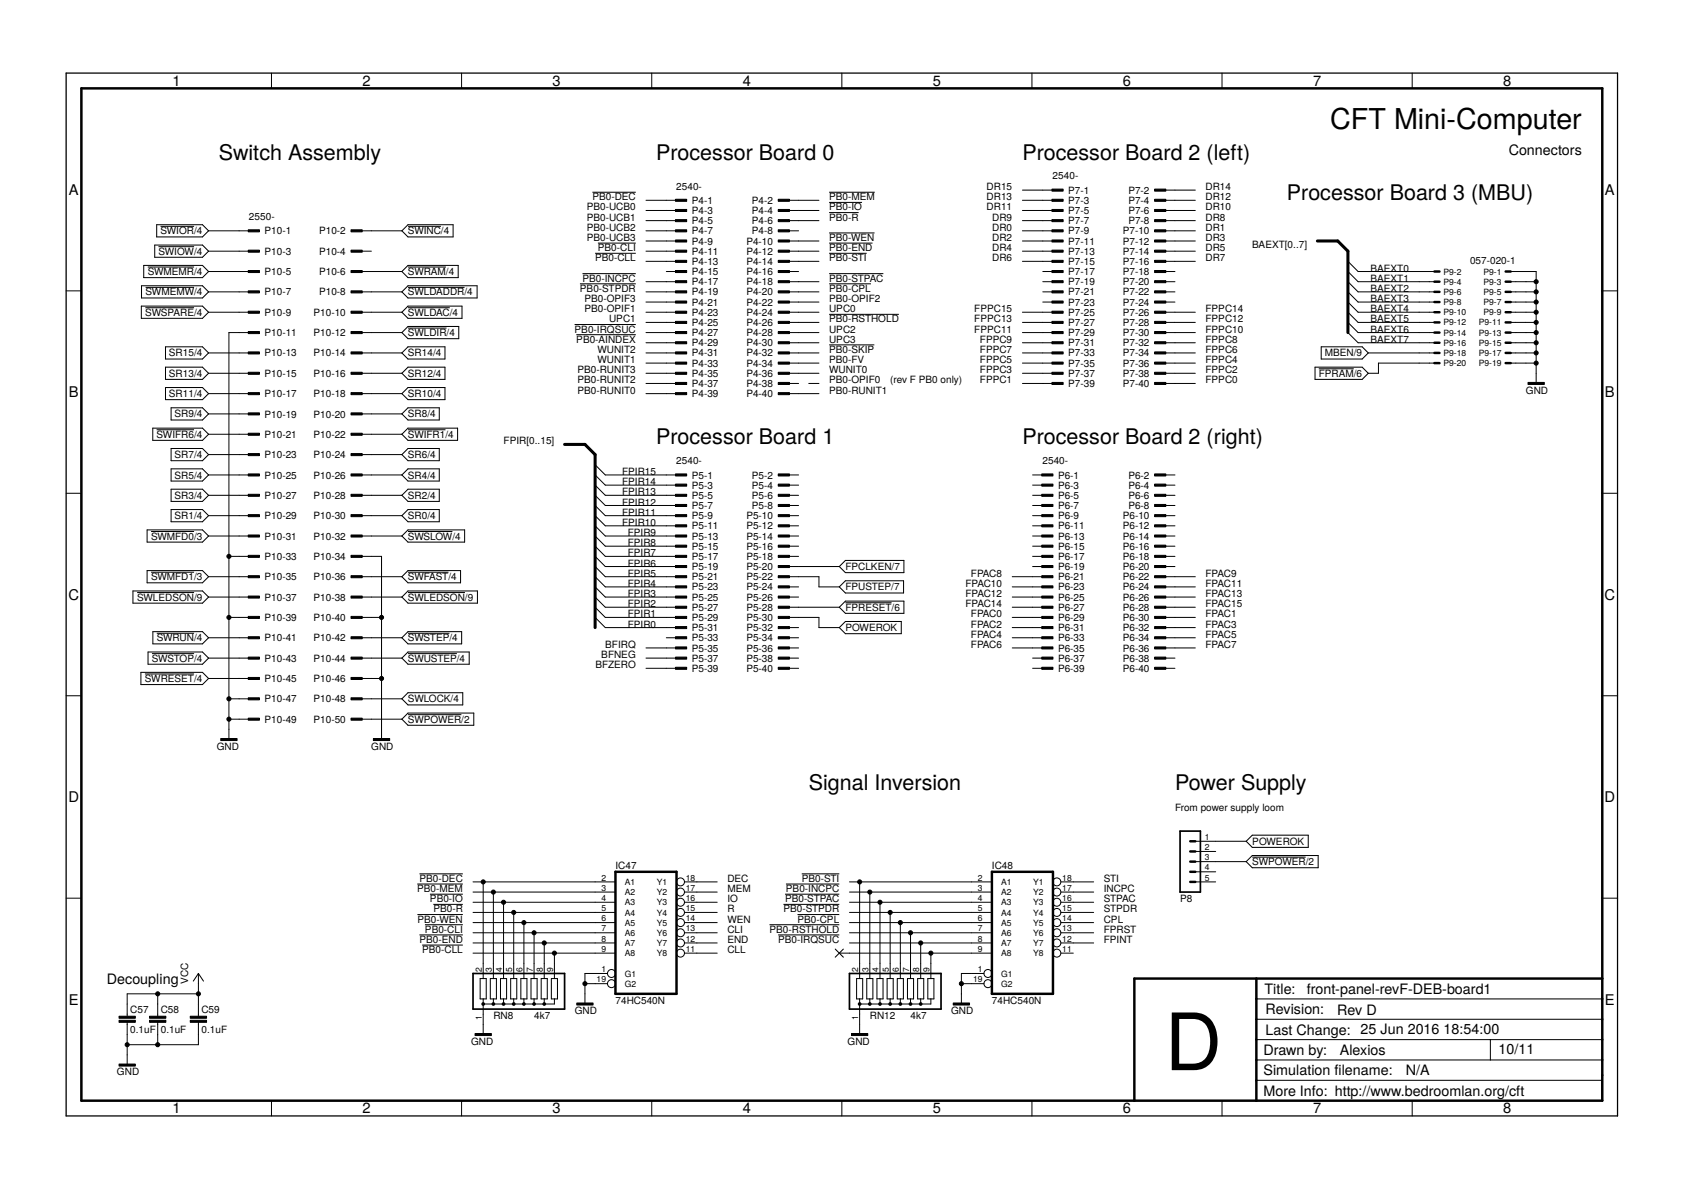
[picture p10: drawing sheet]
<svg xmlns="http://www.w3.org/2000/svg" width="420mm" height="297mm" viewBox="0 0 420 297" stroke-linecap="round" stroke-linejoin="round" font-family="sans-serif">
<defs><g id="words">
<text font-size="19.7" x="290.8" y="267.1">D</text>
<text font-size="7.2" x="332.1" y="32.2">CFT Mini-Computer</text>
<g font-size="5.4">
<text x="54.6" y="39.8">Switch Assembly</text>
<text x="163.8" y="39.8">Processor Board 0</text>
<text x="255.2" y="39.8">Processor Board 2 (left)</text>
<text x="321.3" y="50">Processor Board 3 (MBU)</text>
<text x="163.8" y="110.9">Processor Board 1</text>
<text x="255.2" y="110.9">Processor Board 2 (right)</text>
<text x="201.9" y="197.3">Signal Inversion</text>
<text x="293.3" y="197.3">Power Supply</text>
</g>
<g font-size="3.7">
<text x="43" y="21.4">1</text>
<text x="90.5" y="21.4">2</text>
<text x="138" y="21.4">3</text>
<text x="185.4" y="21.4">4</text>
<text x="232.9" y="21.4">5</text>
<text x="280.3" y="21.4">6</text>
<text x="327.8" y="21.4">7</text>
<text x="375.3" y="21.4">8</text>
<text x="17.2" y="48.6">A</text>
<text x="400.7" y="48.6">A</text>
<text x="17.2" y="99.2">B</text>
<text x="400.7" y="99.2">B</text>
<text x="17.1" y="149.7">C</text>
<text x="400.6" y="149.7">C</text>
<text x="17.1" y="200.2">D</text>
<text x="400.6" y="200.2">D</text>
<text x="17.2" y="250.8">E</text>
<text x="400.7" y="250.8">E</text>
<text x="43" y="277.9">1</text>
<text x="90.5" y="277.9">2</text>
<text x="138" y="277.9">3</text>
<text x="185.4" y="277.9">4</text>
<text x="232.9" y="277.9">5</text>
<text x="280.3" y="277.9">6</text>
<text x="327.8" y="277.9">7</text>
<text x="375.3" y="277.9">8</text>
</g>
<g font-size="3.6">
<text x="376.6" y="38.6">Connectors</text>
<text x="26.7" y="245.5">Decoupling</text>
<text x="315.7" y="248.1">Title:</text>
<text x="326.2" y="248.2">front-panel-revF-DEB-board1</text>
<text x="315.9" y="253.2">Revision:</text>
<text x="333.8" y="253.3">Rev D</text>
<text x="315.4" y="263.3">Drawn by:</text>
<text x="315.9" y="258.2">Last Change: 25 Jun 2016</text>
<text x="334.5" y="263.3">Alexios</text>
<text x="360.4" y="258.1">18:54:00</text>
<text x="374.1" y="263.2">10/11</text>
<text x="315.4" y="268.4">Simulation flename:</text>
<text x="333.2" y="268.4">i</text>
<text x="351" y="268.4">N/A</text>
<text x="315.4" y="273.5">More Info: http://www.bedroomlan.org/cft</text>
</g>
<g font-size="2.5">
<text x="168.8" y="47.3">2540-</text>
<text x="246.3" y="47.5">DR15</text>
<text x="262.8" y="44.8">2540-</text>
<text x="301" y="47.5">DR14</text>
<text x="146.5" y="52.5">PB0-UCB0</text>
<text x="147.9" y="50">PB0-DEC</text>
<text x="172.7" y="50.9">P4-1</text>
<text x="172.7" y="53.4">P4-3</text>
<text x="187.7" y="50.9">P4-2</text>
<text x="187.7" y="53.4">P4-4</text>
<text x="207" y="50">PB0-MEM</text>
<text x="207" y="52.5">PB0-IO</text>
<text x="246.3" y="52.5">DR11</text>
<text x="246.3" y="50">DR13</text>
<text x="266.7" y="48.3">P7-1</text>
<text x="266.7" y="50.9">P7-3</text>
<text x="266.7" y="53.4">P7-5</text>
<text x="281.7" y="48.3">P7-2</text>
<text x="281.7" y="50.9">P7-4</text>
<text x="281.7" y="53.4">P7-6</text>
<text x="301" y="52.5">DR10</text>
<text x="301" y="50">DR12</text>
<text x="40.1" y="58.5">SWIOR/4</text>
<text x="62.2" y="54.9">2550-</text>
<text x="66" y="58.5">P10-1</text>
<text x="79.7" y="58.5">P10-2</text>
<text x="101.8" y="58.5">SWINC/4</text>
<text x="146.5" y="55.1">PB0-UCB1</text>
<text x="146.5" y="57.6">PB0-UCB2</text>
<text x="172.7" y="56">P4-5</text>
<text x="172.7" y="58.5">P4-7</text>
<text x="187.7" y="56">P4-6</text>
<text x="187.7" y="58.5">P4-8</text>
<text x="207" y="55.1">PB0-R</text>
<text x="247.7" y="57.6">DR0</text>
<text x="247.7" y="55.1">DR9</text>
<text x="266.7" y="56">P7-7</text>
<text x="266.7" y="58.5">P7-9</text>
<text x="280.3" y="58.5">P7-10</text>
<text x="281.7" y="56">P7-8</text>
<text x="301" y="57.6">DR1</text>
<text x="301" y="55.1">DR8</text>
<text x="39.6" y="63.6">SWIOW/4</text>
<text x="66" y="63.6">P10-3</text>
<text x="79.7" y="63.6">P10-4</text>
<text x="146.5" y="60.2">PB0-UCB3</text>
<text x="148.6" y="65.2">PB0-CLL</text>
<text x="149.3" y="62.7">PB0-CLI</text>
<text x="172.7" y="61">P4-9</text>
<text x="172.7" y="63.6">P4-11</text>
<text x="186.3" y="61">P4-10</text>
<text x="186.3" y="63.6">P4-12</text>
<text x="207" y="60.2">PB0-WEN</text>
<text x="207" y="62.7">PB0-END</text>
<text x="207" y="65.2">PB0-STI</text>
<text x="247.7" y="60.2">DR2</text>
<text x="247.7" y="62.7">DR4</text>
<text x="247.7" y="65.2">DR6</text>
<text x="266.7" y="61">P7-11</text>
<text x="266.7" y="63.6">P7-13</text>
<text x="280.3" y="61">P7-12</text>
<text x="280.3" y="63.6">P7-14</text>
<text x="301" y="60.2">DR3</text>
<text x="301" y="62.7">DR5</text>
<text x="301" y="65.2">DR7</text>
<text x="312.6" y="61.9">BAEXT[0..7]</text>
<text x="367" y="65.9">057-020-1</text>
<text x="36.9" y="68.7">SWMEMR/4</text>
<text x="66" y="68.7">P10-5</text>
<text x="79.7" y="68.7">P10-6</text>
<text x="101.8" y="68.7">SWRAM/4</text>
<text x="145.4" y="70.3">PB0-INCPC</text>
<text x="172.7" y="66.1">P4-13</text>
<text x="172.7" y="68.7">P4-15</text>
<text x="172.7" y="71.2">P4-17</text>
<text x="186.3" y="66.1">P4-14</text>
<text x="186.3" y="68.7">P4-16</text>
<text x="186.3" y="71.2">P4-18</text>
<text x="207" y="70.3">PB0-STPAC</text>
<text x="266.7" y="66.1">P7-15</text>
<text x="266.7" y="68.7">P7-17</text>
<text x="266.7" y="71.2">P7-19</text>
<text x="280.3" y="66.1">P7-16</text>
<text x="280.3" y="68.7">P7-18</text>
<text x="280.3" y="71.2">P7-20</text>
<text x="342.2" y="67.8">BAEXT0</text>
<text x="342.2" y="70.3">BAEXT1</text>
<text x="36.3" y="73.7">SWMEMW/4</text>
<text x="66" y="73.7">P10-7</text>
<text x="79.7" y="73.7">P10-8</text>
<text x="101.8" y="73.7">SWLDADDR/4</text>
<text x="144.8" y="72.8">PB0-STPDR</text>
<text x="145.9" y="75.4">PB0-OPIF3</text>
<text x="145.9" y="77.9">PB0-OPIF1</text>
<text x="172.7" y="73.7">P4-19</text>
<text x="172.7" y="76.3">P4-21</text>
<text x="186.3" y="73.7">P4-20</text>
<text x="186.3" y="76.3">P4-22</text>
<text x="207" y="72.8">PB0-CPL</text>
<text x="207" y="75.4">PB0-OPIF2</text>
<text x="207" y="77.9">UPC0</text>
<text x="243.2" y="77.9">FPPC15</text>
<text x="266.7" y="73.7">P7-21</text>
<text x="266.7" y="76.3">P7-23</text>
<text x="280.3" y="73.7">P7-22</text>
<text x="280.3" y="76.3">P7-24</text>
<text x="301" y="77.9">FPPC14</text>
<text x="342.2" y="72.8">BAEXT2</text>
<text x="342.2" y="75.4">BAEXT3</text>
<text x="342.2" y="77.9">BAEXT4</text>
<text x="36.3" y="78.8">SWSPARE/4</text>
<text x="66" y="78.8">P10-9</text>
<text x="66" y="83.9">P10-11</text>
<text x="78.3" y="78.8">P10-10</text>
<text x="78.3" y="83.9">P10-12</text>
<text x="101.8" y="78.8">SWLDAC/4</text>
<text x="101.8" y="83.9">SWLDIR/4</text>
<text x="143.5" y="83">PB0-IRQSUC</text>
<text x="152.1" y="80.5">UPC1</text>
<text x="172.7" y="78.8">P4-23</text>
<text x="172.7" y="81.4">P4-25</text>
<text x="172.7" y="83.9">P4-27</text>
<text x="186.3" y="78.8">P4-24</text>
<text x="186.3" y="81.4">P4-26</text>
<text x="186.3" y="83.9">P4-28</text>
<text x="207" y="80.5">PB0-RSTHOLD</text>
<text x="207" y="83">UPC2</text>
<text x="243.2" y="80.5">FPPC13</text>
<text x="243.2" y="83">FPPC11</text>
<text x="266.7" y="78.8">P7-25</text>
<text x="266.7" y="81.4">P7-27</text>
<text x="266.7" y="83.9">P7-29</text>
<text x="280.3" y="78.8">P7-26</text>
<text x="280.3" y="81.4">P7-28</text>
<text x="280.3" y="83.9">P7-30</text>
<text x="301" y="80.5">FPPC12</text>
<text x="301" y="83">FPPC10</text>
<text x="342.2" y="80.5">BAEXT5</text>
<text x="342.2" y="83">BAEXT6</text>
<text x="42.2" y="89">SR15/4</text>
<text x="66" y="89">P10-13</text>
<text x="78.3" y="89">P10-14</text>
<text x="101.8" y="89">SR14/4</text>
<text x="143.9" y="85.5">PB0-AINDEX</text>
<text x="149.2" y="88.1">WUNIT2</text>
<text x="172.7" y="86.4">P4-29</text>
<text x="172.7" y="89">P4-31</text>
<text x="186.3" y="86.4">P4-30</text>
<text x="186.3" y="89">P4-32</text>
<text x="207" y="85.5">UPC3</text>
<text x="207" y="88.1">PB0-SKIP</text>
<text x="244.6" y="85.5">FPPC9</text>
<text x="244.6" y="88.1">FPPC7</text>
<text x="266.7" y="86.4">P7-31</text>
<text x="266.7" y="89">P7-33</text>
<text x="280.3" y="86.4">P7-32</text>
<text x="280.3" y="89">P7-34</text>
<text x="301" y="85.5">FPPC8</text>
<text x="301" y="88.1">FPPC6</text>
<text x="330.8" y="89">MBEN/9</text>
<text x="342.2" y="85.5">BAEXT7</text>
<text x="42.2" y="94.1">SR13/4</text>
<text x="66" y="94.1">P10-15</text>
<text x="78.3" y="94.1">P10-16</text>
<text x="101.8" y="94.1">SR12/4</text>
<text x="144.2" y="93.2">PB0-RUNIT3</text>
<text x="144.2" y="95.7">PB0-RUNIT2</text>
<text x="149.2" y="90.6">WUNIT1</text>
<text x="172.7" y="91.5">P4-33</text>
<text x="172.7" y="94.1">P4-35</text>
<text x="186.3" y="91.5">P4-34</text>
<text x="186.3" y="94.1">P4-36</text>
<text x="207" y="90.6">PB0-FV</text>
<text x="207" y="95.7">PB0-OPIF0</text>
<text x="207" y="93.2">WUNIT0</text>
<text x="222.2" y="95.7">(rev F PB0 only)</text>
<text x="244.6" y="90.6">FPPC5</text>
<text x="244.6" y="93.2">FPPC3</text>
<text x="244.6" y="95.7">FPPC1</text>
<text x="266.7" y="91.5">P7-35</text>
<text x="266.7" y="94.1">P7-37</text>
<text x="280.3" y="91.5">P7-36</text>
<text x="280.3" y="94.1">P7-38</text>
<text x="301" y="90.6">FPPC4</text>
<text x="301" y="93.2">FPPC2</text>
<text x="301" y="95.7">FPPC0</text>
<text x="329.2" y="94.1">FPRAM/6</text>
<text x="42.2" y="99.1">SR11/4</text>
<text x="66" y="99.1">P10-17</text>
<text x="78.3" y="99.1">P10-18</text>
<text x="101.8" y="99.1">SR10/4</text>
<text x="144.2" y="98.2">PB0-RUNIT0</text>
<text x="172.7" y="96.6">P4-37</text>
<text x="172.7" y="99.1">P4-39</text>
<text x="186.3" y="96.6">P4-38</text>
<text x="186.3" y="99.1">P4-40</text>
<text x="207" y="98.2">PB0-RUNIT1</text>
<text x="266.7" y="96.6">P7-39</text>
<text x="280.3" y="96.6">P7-40</text>
<text x="381" y="98.2">GND</text>
<text x="43.6" y="104.2">SR9/4</text>
<text x="66" y="104.2">P10-19</text>
<text x="78.3" y="104.2">P10-20</text>
<text x="101.8" y="104.2">SR8/4</text>
<text x="39.1" y="109.3">SWIFR6/4</text>
<text x="66" y="109.3">P10-21</text>
<text x="78.3" y="109.3">P10-22</text>
<text x="101.8" y="109.3">SWIFR1/4</text>
<text x="125.7" y="110.9">FPIR[0..15]</text>
<text x="43.6" y="119.5">SR5/4</text>
<text x="43.6" y="114.4">SR7/4</text>
<text x="66" y="114.4">P10-23</text>
<text x="66" y="119.5">P10-25</text>
<text x="78.3" y="114.4">P10-24</text>
<text x="78.3" y="119.5">P10-26</text>
<text x="101.8" y="119.5">SR4/4</text>
<text x="101.8" y="114.4">SR6/4</text>
<text x="155.3" y="118.6">FPIR15</text>
<text x="168.8" y="115.9">2540-</text>
<text x="172.7" y="119.5">P5-1</text>
<text x="187.7" y="119.5">P5-2</text>
<text x="260.3" y="115.9">2540-</text>
<text x="264.1" y="119.5">P6-1</text>
<text x="281.7" y="119.5">P6-2</text>
<text x="43.6" y="124.5">SR3/4</text>
<text x="66" y="124.5">P10-27</text>
<text x="78.3" y="124.5">P10-28</text>
<text x="101.8" y="124.5">SR2/4</text>
<text x="155.3" y="123.6">FPIR13</text>
<text x="155.3" y="121.1">FPIR14</text>
<text x="172.7" y="122">P5-3</text>
<text x="172.7" y="124.5">P5-5</text>
<text x="187.7" y="122">P5-4</text>
<text x="187.7" y="124.5">P5-6</text>
<text x="264.1" y="122">P6-3</text>
<text x="264.1" y="124.5">P6-5</text>
<text x="281.7" y="122">P6-4</text>
<text x="281.7" y="124.5">P6-6</text>
<text x="43.6" y="129.6">SR1/4</text>
<text x="66" y="129.6">P10-29</text>
<text x="78.3" y="129.6">P10-30</text>
<text x="101.8" y="129.6">SR0/4</text>
<text x="155.3" y="131.3">FPIR10</text>
<text x="155.3" y="128.7">FPIR11</text>
<text x="155.3" y="126.2">FPIR12</text>
<text x="172.7" y="127.1">P5-7</text>
<text x="172.7" y="129.6">P5-9</text>
<text x="186.3" y="129.6">P5-10</text>
<text x="187.7" y="127.1">P5-8</text>
<text x="264.1" y="127.1">P6-7</text>
<text x="264.1" y="129.6">P6-9</text>
<text x="280.3" y="129.6">P6-10</text>
<text x="281.7" y="127.1">P6-8</text>
<text x="37.7" y="134.7">SWMFD0/3</text>
<text x="66" y="134.7">P10-31</text>
<text x="78.3" y="134.7">P10-32</text>
<text x="101.8" y="134.7">SWSLOW/4</text>
<text x="156.7" y="136.3">FPIR8</text>
<text x="156.7" y="133.8">FPIR9</text>
<text x="172.7" y="132.1">P5-11</text>
<text x="172.7" y="134.7">P5-13</text>
<text x="172.7" y="137.2">P5-15</text>
<text x="186.3" y="132.1">P5-12</text>
<text x="186.3" y="134.7">P5-14</text>
<text x="186.3" y="137.2">P5-16</text>
<text x="264.1" y="132.1">P6-11</text>
<text x="264.1" y="134.7">P6-13</text>
<text x="264.1" y="137.2">P6-15</text>
<text x="280.3" y="132.1">P6-12</text>
<text x="280.3" y="134.7">P6-14</text>
<text x="280.3" y="137.2">P6-16</text>
<text x="66" y="139.8">P10-33</text>
<text x="78.3" y="139.8">P10-34</text>
<text x="156.7" y="144">FPIR5</text>
<text x="156.7" y="141.4">FPIR6</text>
<text x="156.7" y="138.9">FPIR7</text>
<text x="172.7" y="139.8">P5-17</text>
<text x="172.7" y="142.3">P5-19</text>
<text x="186.3" y="139.8">P5-18</text>
<text x="186.3" y="142.3">P5-20</text>
<text x="211.1" y="142.3">FPCLKEN/7</text>
<text x="242.4" y="144">FPAC8</text>
<text x="264.1" y="139.8">P6-17</text>
<text x="264.1" y="142.3">P6-19</text>
<text x="280.3" y="139.8">P6-18</text>
<text x="280.3" y="142.3">P6-20</text>
<text x="301" y="144">FPAC9</text>
<text x="34.2" y="149.9">SWLEDSON/9</text>
<text x="37.7" y="144.8">SWMFD1/3</text>
<text x="66" y="144.8">P10-35</text>
<text x="66" y="149.9">P10-37</text>
<text x="78.3" y="144.8">P10-36</text>
<text x="78.3" y="149.9">P10-38</text>
<text x="101.8" y="144.8">SWFAST/4</text>
<text x="101.8" y="149.9">SWLEDSON/9</text>
<text x="156.7" y="149">FPIR3</text>
<text x="156.7" y="146.5">FPIR4</text>
<text x="172.7" y="144.8">P5-21</text>
<text x="172.7" y="147.4">P5-23</text>
<text x="172.7" y="149.9">P5-25</text>
<text x="186.3" y="144.8">P5-22</text>
<text x="186.3" y="147.4">P5-24</text>
<text x="186.3" y="149.9">P5-26</text>
<text x="211.1" y="147.4">FPUSTEP/7</text>
<text x="241" y="146.5">FPAC10</text>
<text x="241" y="149">FPAC12</text>
<text x="264.1" y="144.8">P6-21</text>
<text x="264.1" y="147.4">P6-23</text>
<text x="264.1" y="149.9">P6-25</text>
<text x="280.3" y="144.8">P6-22</text>
<text x="280.3" y="147.4">P6-24</text>
<text x="280.3" y="149.9">P6-26</text>
<text x="301" y="146.5">FPAC11</text>
<text x="301" y="149">FPAC13</text>
<text x="66" y="155">P10-39</text>
<text x="78.3" y="155">P10-40</text>
<text x="156.7" y="154.1">FPIR1</text>
<text x="156.7" y="151.6">FPIR2</text>
<text x="172.7" y="152.5">P5-27</text>
<text x="172.7" y="155">P5-29</text>
<text x="186.3" y="152.5">P5-28</text>
<text x="186.3" y="155">P5-30</text>
<text x="211.1" y="152.5">FPRESET/6</text>
<text x="241" y="151.6">FPAC14</text>
<text x="242.4" y="154.1">FPAC0</text>
<text x="264.1" y="152.5">P6-27</text>
<text x="264.1" y="155">P6-29</text>
<text x="280.3" y="152.5">P6-28</text>
<text x="280.3" y="155">P6-30</text>
<text x="301" y="151.6">FPAC15</text>
<text x="301" y="154.1">FPAC1</text>
<text x="39.1" y="160.1">SWRUN/4</text>
<text x="66" y="160.1">P10-41</text>
<text x="78.3" y="160.1">P10-42</text>
<text x="101.8" y="160.1">SWSTEP/4</text>
<text x="151.1" y="161.7">BFIRQ</text>
<text x="156.7" y="156.7">FPIR0</text>
<text x="172.7" y="157.5">P5-31</text>
<text x="172.7" y="160.1">P5-33</text>
<text x="186.3" y="157.5">P5-32</text>
<text x="186.3" y="160.1">P5-34</text>
<text x="211.1" y="157.5">POWEROK</text>
<text x="242.4" y="156.7">FPAC2</text>
<text x="242.4" y="159.2">FPAC4</text>
<text x="242.4" y="161.7">FPAC6</text>
<text x="264.1" y="157.5">P6-31</text>
<text x="264.1" y="160.1">P6-33</text>
<text x="280.3" y="157.5">P6-32</text>
<text x="280.3" y="160.1">P6-34</text>
<text x="301" y="156.7">FPAC3</text>
<text x="301" y="159.2">FPAC5</text>
<text x="301" y="161.7">FPAC7</text>
<text x="37.9" y="165.2">SWSTOP/4</text>
<text x="66" y="165.2">P10-43</text>
<text x="78.3" y="165.2">P10-44</text>
<text x="101.8" y="165.2">SWUSTEP/4</text>
<text x="148.6" y="166.8">BFZERO</text>
<text x="150.1" y="164.3">BFNEG</text>
<text x="172.7" y="162.6">P5-35</text>
<text x="172.7" y="165.2">P5-37</text>
<text x="172.7" y="167.7">P5-39</text>
<text x="186.3" y="162.6">P5-36</text>
<text x="186.3" y="165.2">P5-38</text>
<text x="186.3" y="167.7">P5-40</text>
<text x="264.1" y="162.6">P6-35</text>
<text x="264.1" y="165.2">P6-37</text>
<text x="264.1" y="167.7">P6-39</text>
<text x="280.3" y="162.6">P6-36</text>
<text x="280.3" y="165.2">P6-38</text>
<text x="280.3" y="167.7">P6-40</text>
<text x="36.2" y="170.2">SWRESET/4</text>
<text x="66" y="170.2">P10-45</text>
<text x="78.3" y="170.2">P10-46</text>
<text x="66" y="175.3">P10-47</text>
<text x="78.3" y="175.3">P10-48</text>
<text x="101.8" y="175.3">SWLOCK/4</text>
<text x="66" y="180.4">P10-49</text>
<text x="78.3" y="180.4">P10-50</text>
<text x="101.8" y="180.4">SWPOWER/2</text>
<text x="54.1" y="187.1">GND</text>
<text x="92.7" y="187.1">GND</text>
<text x="293.3" y="202.4">From power supply loom</text>
<text x="312.6" y="210.9">POWEROK</text>
<text x="312.6" y="216">SWPOWER/2</text>
<text x="104.7" y="220.1">PB0-DEC</text>
<text x="153.7" y="217">IC47</text>
<text x="181.6" y="220.1">DEC</text>
<text x="200.2" y="220.1">PB0-STI</text>
<text x="247.6" y="217">IC48</text>
<text x="275.6" y="220.1">STI</text>
<text x="104.2" y="222.7">PB0-MEM</text>
<text x="107.3" y="225.2">PB0-IO</text>
<text x="108.2" y="227.8">PB0-R</text>
<text x="181.6" y="222.7">MEM</text>
<text x="181.6" y="225.2">IO</text>
<text x="181.6" y="227.8">R</text>
<text x="195.6" y="227.8">PB0-STPDR</text>
<text x="196" y="225.2">PB0-STPAC</text>
<text x="196.2" y="222.7">PB0-INCPC</text>
<text x="275.6" y="222.7">INCPC</text>
<text x="275.6" y="225.2">STPAC</text>
<text x="275.6" y="227.8">STPDR</text>
<text x="294.6" y="225.2">P8</text>
<text x="104.2" y="230.3">PB0-WEN</text>
<text x="106.1" y="232.8">PB0-CLI</text>
<text x="181.6" y="232.8">CLI</text>
<text x="181.6" y="230.3">WEN</text>
<text x="192.1" y="232.8">PB0-RSTHOLD</text>
<text x="199.1" y="230.3">PB0-CPL</text>
<text x="275.6" y="230.3">CPL</text>
<text x="275.6" y="232.8">FPRST</text>
<text x="104.7" y="235.4">PB0-END</text>
<text x="105.4" y="237.9">PB0-CLL</text>
<text x="181.6" y="237.9">CLL</text>
<text x="181.6" y="235.4">END</text>
<text x="194.2" y="235.4">PB0-IRQSUC</text>
<text x="275.6" y="235.4">FPINT</text>
<text x="47" y="245.5" transform="rotate(-90 47 245.5)">VCC</text>
<text x="153.7" y="250.6">74HC540N</text>
<text x="247.6" y="250.6">74HC540N</text>
<text x="32.5" y="257.9">0.1uF</text>
<text x="32.5" y="252.8">C57</text>
<text x="40.1" y="257.9">0.1uF</text>
<text x="40.1" y="252.8">C58</text>
<text x="50.3" y="257.9">0.1uF</text>
<text x="50.3" y="252.8">C59</text>
<text x="123.2" y="254.3">RN8</text>
<text x="133.3" y="254.3">4k7</text>
<text x="143.5" y="253.2">GND</text>
<text x="217.1" y="254.3">RN12</text>
<text x="227.3" y="254.3">4k7</text>
<text x="237.5" y="253.2">GND</text>
<text x="117.6" y="260.8">GND</text>
<text x="211.6" y="260.8">GND</text>
<text x="29.2" y="268.4">GND</text>
</g>
<g font-size="2.1">
<text x="360.4" y="68.5">P9-2</text>
<text x="360.4" y="71.1">P9-4</text>
<text x="370.4" y="68.5">P9-1</text>
<text x="370.4" y="71.1">P9-3</text>
<text x="360.4" y="73.6">P9-6</text>
<text x="360.4" y="76.2">P9-8</text>
<text x="370.4" y="73.6">P9-5</text>
<text x="370.4" y="76.2">P9-7</text>
<text x="360.4" y="78.7">P9-10</text>
<text x="360.4" y="81.2">P9-12</text>
<text x="360.4" y="83.8">P9-14</text>
<text x="369.2" y="81.2">P9-11</text>
<text x="369.2" y="83.8">P9-13</text>
<text x="370.4" y="78.7">P9-9</text>
<text x="360.4" y="86.3">P9-16</text>
<text x="360.4" y="88.8">P9-18</text>
<text x="369.2" y="86.3">P9-15</text>
<text x="369.2" y="88.8">P9-17</text>
<text x="360.4" y="91.4">P9-20</text>
<text x="369.2" y="91.4">P9-19</text>
<text x="300.8" y="209.6">1</text>
<text x="300.8" y="212.2">2</text>
<text x="300.8" y="214.7">3</text>
<text x="150.1" y="219.8">2</text>
<text x="156" y="220.9">A1</text>
<text x="164" y="220.9">Y1</text>
<text x="171.2" y="219.8">18</text>
<text x="244.1" y="219.8">2</text>
<text x="250" y="220.9">A1</text>
<text x="257.9" y="220.9">Y1</text>
<text x="265.2" y="219.8">18</text>
<text x="300.8" y="217.2">4</text>
<text x="300.8" y="219.8">5</text>
<text x="150.1" y="222.3">3</text>
<text x="150.1" y="224.9">4</text>
<text x="150.1" y="227.4">5</text>
<text x="156" y="223.4">A2</text>
<text x="156" y="226">A3</text>
<text x="164" y="226">Y3</text>
<text x="164" y="223.4">Y2</text>
<text x="171.2" y="227.4">15</text>
<text x="171.2" y="224.9">16</text>
<text x="171.2" y="222.3">17</text>
<text x="244.1" y="222.3">3</text>
<text x="244.1" y="224.9">4</text>
<text x="244.1" y="227.4">5</text>
<text x="250" y="223.4">A2</text>
<text x="250" y="226">A3</text>
<text x="257.9" y="226">Y3</text>
<text x="257.9" y="223.4">Y2</text>
<text x="265.2" y="227.4">15</text>
<text x="265.2" y="224.9">16</text>
<text x="265.2" y="222.3">17</text>
<text x="150.1" y="229.9">6</text>
<text x="150.1" y="232.5">7</text>
<text x="156" y="228.5">A4</text>
<text x="156" y="231.1">A5</text>
<text x="156" y="233.6">A6</text>
<text x="164" y="233.6">Y6</text>
<text x="164" y="231.1">Y5</text>
<text x="164" y="228.5">Y4</text>
<text x="171.2" y="232.5">13</text>
<text x="171.2" y="229.9">14</text>
<text x="244.1" y="229.9">6</text>
<text x="244.1" y="232.5">7</text>
<text x="250" y="228.5">A4</text>
<text x="250" y="231.1">A5</text>
<text x="250" y="233.6">A6</text>
<text x="257.9" y="233.6">Y6</text>
<text x="257.9" y="231.1">Y5</text>
<text x="257.9" y="228.5">Y4</text>
<text x="265.2" y="232.5">13</text>
<text x="265.2" y="229.9">14</text>
<text x="150.1" y="235">8</text>
<text x="150.1" y="237.6">9</text>
<text x="156" y="236.1">A7</text>
<text x="156" y="238.7">A8</text>
<text x="164" y="238.7">Y8</text>
<text x="164" y="236.1">Y7</text>
<text x="171.2" y="237.6">11</text>
<text x="171.2" y="235">12</text>
<text x="244.1" y="235">8</text>
<text x="244.1" y="237.6">9</text>
<text x="250" y="236.1">A7</text>
<text x="250" y="238.7">A8</text>
<text x="257.9" y="238.7">Y8</text>
<text x="257.9" y="236.1">Y7</text>
<text x="265.2" y="237.6">11</text>
<text x="265.2" y="235">12</text>
<text x="120.3" y="242.6" transform="rotate(-90 120.3 242.6)">2</text>
<text x="122.8" y="242.6" transform="rotate(-90 122.8 242.6)">3</text>
<text x="125.4" y="242.6" transform="rotate(-90 125.4 242.6)">4</text>
<text x="127.9" y="242.6" transform="rotate(-90 127.9 242.6)">5</text>
<text x="130.4" y="242.6" transform="rotate(-90 130.4 242.6)">6</text>
<text x="133" y="242.6" transform="rotate(-90 133 242.6)">7</text>
<text x="135.5" y="242.6" transform="rotate(-90 135.5 242.6)">8</text>
<text x="138.1" y="242.6" transform="rotate(-90 138.1 242.6)">9</text>
<text x="148.9" y="245.2">19</text>
<text x="150.1" y="242.6">1</text>
<text x="156" y="243.8">G1</text>
<text x="214.3" y="242.6" transform="rotate(-90 214.3 242.6)">2</text>
<text x="216.8" y="242.6" transform="rotate(-90 216.8 242.6)">3</text>
<text x="219.3" y="242.6" transform="rotate(-90 219.3 242.6)">4</text>
<text x="221.9" y="242.6" transform="rotate(-90 221.9 242.6)">5</text>
<text x="224.4" y="242.6" transform="rotate(-90 224.4 242.6)">6</text>
<text x="226.9" y="242.6" transform="rotate(-90 226.9 242.6)">7</text>
<text x="229.5" y="242.6" transform="rotate(-90 229.5 242.6)">8</text>
<text x="232" y="242.6" transform="rotate(-90 232 242.6)">9</text>
<text x="242.9" y="245.2">19</text>
<text x="244.1" y="242.6">1</text>
<text x="250" y="243.8">G1</text>
<text x="156" y="246.3">G2</text>
<text x="250" y="246.3">G2</text>
<text x="120.3" y="254.7" transform="rotate(-90 120.3 254.7)">1</text>
<text x="214.3" y="254.7" transform="rotate(-90 214.3 254.7)">1</text>
</g>
</g></defs>
<g fill="none" stroke="#000" stroke-width=".25">
<path d="M67.8 18.2v3.9M115.2 18.2v3.9M162.7 18.2v3.9M210.2 18.2v3.9M257.6 18.2v3.9M305.1 18.2v3.9M352.6 18.2v3.9M20.3 22.1h379.7v252.6h-379.7zM39.1 56.1h11.4l1.6 1.5-1.6 1.5h-11.4zM40.1 56.5h8.4M52.1 57.6h10.1M90.2 57.6h10.1"/>
<path d="M100.3 57.6l1.6-1.5h11.2v3h-11.2zM101.9 56.5h8.2M147.9 48h10.8M161.3 50h7.6M161.3 52.5h7.6M161.3 55.1h7.6M161.3 57.6h7.6M196.8 50h7.6M196.8 52.5h7.6M196.8 55.1h7.6M196.8 57.6h2.6M207 48h11.4"/>
<path d="M207 50.5h8.2M207 53.1h7.4M207 58.1h11.3M255.2 50h7.7M255.2 52.5h7.7M255.2 55.1h7.7M255.2 57.6h7.7M255.2 47.5h7.7M290.8 50h7.6M290.8 52.5h7.6M290.8 55.1h7.6M290.8 57.6h7.6"/>
<path d="M290.8 47.5h7.6M16.5 72.6h3.8M35.3 76.4h15.2l1.6 1.5-1.6 1.6h-15.2zM35.3 71.3h15.2l1.6 1.6-1.6 1.5h-15.2zM35.9 66.3h14.6l1.6 1.5-1.6 1.5h-14.6zM36.3 76.8h12.2M36.3 71.7h12.2M36.9 66.7h11.6M38.6 61.2h11.9l1.6 1.5-1.6 1.5h-11.9zM39.6 61.6h8.9M52.1 62.7h10.1M52.1 67.8h10.1"/>
<path d="M52.1 72.9h10.1M52.1 77.9h10.1M90.2 62.7h2.5M90.2 67.8h10.1M90.2 72.9h10.1M90.2 77.9h10.1M101.9 71.3h17.2v3.1h-17.2l-1.6-1.5zM101.9 71.7h14.1M101.9 76.4h13.4v3.1h-13.4l-1.6-1.6zM101.9 76.8h10.4M101.9 66.3h12.5v3h-12.5l-1.6-1.5zM101.9 66.7h9.4"/>
<path d="M144.8 70.8h13.9M145.4 68.3h13.3M148.6 63.2h10.1M149.3 60.7h9.4M161.3 60.2h7.6M161.3 62.7h7.6M161.3 65.2h7.6M161.3 70.3h7.6M161.3 72.9h7.6M161.3 75.4h7.6M161.3 77.9h7.6M166.3 67.8h2.6"/>
<path d="M196.8 60.2h7.6M196.8 62.7h7.6M196.8 65.2h7.6M196.8 67.8h2.6M196.8 70.3h7.6M196.8 72.9h7.6M196.8 75.4h7.6M196.8 77.9h7.6M207 60.7h10.8M207 63.2h9.4M207 68.3h13.5M207 70.8h10.4"/>
<path d="M207 78.5h17.4M255.2 60.2h7.7M255.2 62.7h7.7M255.2 65.2h7.7M255.2 77.9h7.7M260.3 67.8h2.6M260.3 70.3h2.6M260.3 72.9h2.6M260.3 75.4h2.6M290.8 60.2h7.6M290.8 62.7h7.6M290.8 65.2h7.6"/>
<path d="M290.8 67.8h2.5M290.8 70.3h2.5M290.8 72.9h2.5M290.8 75.4h2.5M290.8 77.9h7.6M336.5 65.2l2.5 2.6h19.1M336.5 67.8l2.5 2.5h19.1M336.5 70.3l2.5 2.6h19.1M336.5 72.9l2.5 2.5h19.1M336.5 75.4l2.5 2.5h19.1M336.5 77.9l2.5 2.6h19.1M377.1 67.8h6.4v27.9"/>
<path d="M377.1 70.3h6.4M377.1 72.9h6.4M377.1 75.4h6.4M377.1 77.9h6.4M400 72.6h3.8M41.3 96.7h9.2l1.6 1.6-1.6 1.5h-9.2zM41.3 86.6h9.2l1.6 1.5-1.6 1.5h-9.2zM41.3 91.7h9.2l1.6 1.5-1.6 1.5h-9.2zM52.1 88.1h10.1M52.1 93.2h10.1M52.1 98.3h10.1M62.2 83h-5.1v101.6"/>
<path d="M90.2 83h10.1M90.2 88.1h10.1M90.2 93.2h10.1M90.2 98.3h10.1M101.9 81.5h12.6v3h-12.6l-1.6-1.5zM101.9 81.9h9.6M101.9 96.7h9.2v3.1h-9.2l-1.6-1.5zM101.9 86.6h9.2v3h-9.2l-1.6-1.5zM101.9 91.7h9.2v3h-9.2l-1.6-1.5zM143.4 81h15.3M143.9 83.5h14.8M161.3 80.5h7.6"/>
<path d="M161.3 83h7.6M161.3 85.6h7.6M161.3 88.1h7.6M161.3 90.6h7.6M161.3 93.2h7.6M161.3 95.7h7.6M161.3 98.3h7.6M196.8 80.5h7.6M196.8 83h7.6M196.8 85.6h7.6M196.8 88.1h7.6M196.8 90.6h7.6"/>
<path d="M196.8 93.2h7.6M196.8 95.7h2.6M196.8 98.3h7.6M201.9 95.7h2.5M207 86.1h11.3M255.2 80.5h7.7M255.2 83h7.7M255.2 85.6h7.7M255.2 88.1h7.7M255.2 90.6h7.7M255.2 93.2h7.7M255.2 95.7h7.7"/>
<path d="M290.8 80.5h7.6M290.8 83h7.6M290.8 85.6h7.6M290.8 88.1h7.6M290.8 90.6h7.6M290.8 93.2h7.6M290.8 95.7h7.6M328.3 91.7h11.8l1.5 1.5-1.5 1.5h-11.8zM329.2 92.1h8.8M329.8 86.6h10.3l1.5 1.5-1.5 1.5h-10.3zM336.5 83l2.5 2.6h19.1M336.5 80.5l2.5 2.5h19.1"/>
<path d="M341.6 88.1h16.5M358.1 90.6h-14v2.6h-2.5M377.1 80.5h6.4M377.1 83h6.4M377.1 85.6h6.4M377.1 88.1h6.4M377.1 90.6h6.4M381.6 95.7h3.8M38.1 106.9h12.4l1.6 1.5-1.6 1.5h-12.4zM39.1 107.3h9.4M42.7 101.8h7.8l1.6 1.5-1.6 1.5h-7.8zM42.7 112h7.8l1.6 1.5-1.6 1.5h-7.8z"/>
<path d="M42.7 117h7.8l1.6 1.6-1.6 1.5h-7.8zM52.1 118.6h10.1M52.1 103.3h10.1M52.1 108.4h10.1M52.1 113.5h10.1M90.2 118.6h10.1M90.2 103.3h10.1M90.2 108.4h10.1M90.2 113.5h10.1M100.3 103.3l1.6-1.5h7.8v3h-7.8zM100.3 113.5l1.6-1.5h7.8v3h-7.8zM100.3 118.6l1.6-1.6h7.8v3.1h-7.8z"/>
<path d="M101.9 106.9h12.3v3h-12.3l-1.6-1.5zM101.9 107.3h9.3M148.6 116l2.5 2.6h17.8M148.6 118.6l2.5 2.5h17.8M196.8 118.6h2.6M257.8 118.6h2.5M290.8 118.6h2.5M16.5 123.1h3.8M36.7 132.3h13.8l1.6 1.5-1.6 1.5h-13.8zM37.7 132.7h10.8M42.7 127.2h7.8l1.6 1.5-1.6 1.5h-7.8zM42.7 122.1h7.8l1.6 1.5-1.6 1.6h-7.8z"/>
<path d="M52.1 123.6h10.1M52.1 128.7h10.1M52.1 133.8h10.1M57.1 138.9h5.1M90.2 123.6h10.1M90.2 128.7h10.1M90.2 133.8h10.1M90.2 138.9h5v45.7M100.3 123.6l1.6-1.5h7.8v3.1h-7.8zM101.9 132.3h14.1v3h-14.1l-1.6-1.5zM101.9 132.7h11M101.9 127.2h7.8v3h-7.8l-1.6-1.5z"/>
<path d="M148.6 121.1l2.5 2.5h17.8M148.6 123.6l2.5 2.6h17.8M148.6 126.2l2.5 2.5h17.8M148.6 128.7l2.5 2.6h17.8M148.6 131.3l2.5 2.5h17.8M148.6 133.8l2.5 2.5h17.8M148.6 136.3l2.5 2.6h17.8M148.6 138.9l2.5 2.5h17.8M196.8 121.1h2.6M196.8 123.6h2.6M196.8 126.2h2.6M196.8 128.7h2.6"/>
<path d="M196.8 131.3h2.6M196.8 133.8h2.6M196.8 136.3h2.6M196.8 138.9h2.6M211.1 139.9h14.6v3h-14.6l-1.6-1.5zM257.8 121.1h2.5M257.8 123.6h2.5M257.8 126.2h2.5M257.8 128.7h2.5M257.8 131.3h2.5M257.8 133.8h2.5M257.8 136.3h2.5"/>
<path d="M257.8 138.9h2.5M290.8 121.1h2.5M290.8 123.6h2.5M290.8 126.2h2.5M290.8 128.7h2.5M290.8 131.3h2.5M290.8 133.8h2.5M290.8 136.3h2.5M290.8 138.9h2.5M400 123.1h3.8M33.2 147.5h17.3l1.6 1.5-1.6 1.6h-17.3zM34.2 147.9h14.3"/>
<path d="M36.7 142.4h13.8l1.6 1.6-1.6 1.5h-13.8zM37.7 142.8h10.8M38.2 157.7h12.3l1.6 1.5-1.6 1.5h-12.3zM39.1 158.1h9.4M52.1 144h10.1M52.1 149h10.1M52.1 159.2h10.1M57.1 154.1h5.1M90.2 144h10.1M90.2 149h10.1M90.2 154.1h5M90.2 159.2h10.1"/>
<path d="M101.9 157.7h13.4v3h-13.4l-1.6-1.5zM101.9 158.1h10.3M101.9 142.4h13.1v3.1h-13.1l-1.6-1.5zM101.9 142.8h10.1M101.9 147.5h17.3v3.1h-17.3l-1.6-1.6zM101.9 147.9h14.2M148.6 141.4l2.5 2.6h17.8M148.6 144l2.5 2.5h17.8M148.6 146.5l2.5 2.5h17.8M148.6 149l2.5 2.6h17.8M148.6 151.6l2.5 2.5h17.8M148.6 154.1l2.5 2.6h17.8"/>
<path d="M166.3 159.2h2.6M196.8 141.4h12.7M196.8 144h7.6v2.5h5.1M196.8 146.5h2.6M196.8 149h2.6M196.8 151.6h12.7M196.8 154.1h7.6v2.6h5.1M196.8 156.7h2.6M196.8 159.2h2.6M211.1 150.1h14.6v3h-14.6l-1.6-1.5zM211.1 145h14.5v3h-14.5l-1.6-1.5zM211.1 155.1h13.9v3.1h-13.9l-1.6-1.5z"/>
<path d="M211.1 150.5h11.5M252.7 144h7.6M252.7 146.5h7.6M252.7 149h7.6M252.7 151.6h7.6M252.7 154.1h7.6M252.7 156.7h7.6M252.7 159.2h7.6M257.8 141.4h2.5M290.8 141.4h2.5M290.8 144h7.6M290.8 146.5h7.6"/>
<path d="M290.8 149h7.6M290.8 151.6h7.6M290.8 154.1h7.6M290.8 156.7h7.6M290.8 159.2h7.6M16.5 173.7h3.8M35.2 167.8h15.3l1.6 1.6-1.6 1.5h-15.3zM36.2 168.2h12.3M37 162.8h13.5l1.6 1.5-1.6 1.5h-13.5zM37.9 163.2h10.6M52.1 164.3h10.1M52.1 169.4h10.1"/>
<path d="M57.1 174.4h5.1M57.1 179.5h5.1M90.2 164.3h10.1M90.2 169.4h5M90.2 174.4h10.1M90.2 179.5h10.1M101.9 178h16.4v3h-16.4l-1.6-1.5zM101.9 178.4h13.3M101.9 162.8h15.2v3h-15.2l-1.6-1.5zM101.9 163.2h12.2M101.9 172.9h13.6v3.1h-13.6l-1.6-1.6zM161.3 161.7h7.6"/>
<path d="M161.3 164.3h7.6M161.3 166.8h7.6M196.8 161.7h2.6M196.8 164.3h2.6M196.8 166.8h2.6M252.7 161.7h7.6M257.8 164.3h2.5M257.8 166.8h2.5M290.8 161.7h7.6M290.8 164.3h2.5M290.8 166.8h2.5M400 173.7h3.8"/>
<path d="M55.2 184.6h3.9M93.3 184.6h3.9M104.7 218.1h10.8M200.2 218.1h9.3M298.4 210h12.7M298.4 212.5h5.1M298.4 215.1h12.7M298.4 217.6h5.1M312.6 208.5h14v3h-14l-1.5-1.5zM312.6 213.6h16.5v3h-16.5l-1.5-1.5zM312.6 214h13.4M16.5 224.2h3.8"/>
<path d="M104.2 220.7h11.3M104.2 228.3h11.3M104.7 233.4h10.8M105.4 235.9h10.1M106.1 230.8h9.4M107.3 223.2h8.2M108.2 225.7h7.3M118.1 220.1h35.5M118.1 222.7h35.5M118.1 225.2h35.5M118.1 227.8h35.5M118.1 230.3h35.5"/>
<path d="M118.1 232.8h35.5M118.1 235.4h35.5M118.1 237.9h35.5M120.6 220.1v24.2M123.2 222.7v21.6M125.7 225.2v19.1M128.2 227.8v16.5M130.8 230.3v14M133.3 232.8v11.5M135.9 235.4v8.9M138.4 237.9v6.4M170.9 220.1h8.1"/>
<path d="M170.9 222.7h8.1M170.9 225.2h8.1M170.9 227.8h8.1M170.9 230.3h8.1M170.9 232.8h8.1M170.9 235.4h8.1M170.9 237.9h8.1M192.1 230.8h17.4M194.2 233.4h15.3M195.6 225.7h13.9M196 223.2h13.5M196.2 220.7h13.3"/>
<path d="M199.1 228.3h10.4M208.5 236.9l2 2M209.5 237.9h38.1M210.5 236.9l-2 2M212.1 220.1h35.5M212.1 222.7h35.5M212.1 225.2h35.5M212.1 227.8h35.5M212.1 230.3h35.5M212.1 232.8h35.5M212.1 235.4h35.5M214.6 220.1v24.2"/>
<path d="M217.1 222.7v21.6M219.7 225.2v19.1M222.2 227.8v16.5M224.8 230.3v14M227.3 232.8v11.5M229.8 235.4v8.9M232.4 237.9v6.4M264.8 220.1h8.2M264.8 222.7h8.2M264.8 225.2h8.2M264.8 227.8h8.2M264.8 230.3h8.2"/>
<path d="M264.8 232.8h8.2M264.8 235.4h8.2M264.8 237.9h3.1M298.4 220.1h5.1M400 224.2h3.8M31.7 255.2v10.7M39.4 248.1v5.6M39.4 255.2v5.6M49.5 243l1.3 1.9M49.5 243l-1.2 1.9M49.5 243v10.7M49.5 255.2v5.6h-17.8"/>
<path d="M49.5 248.1h-17.8v5.6M118.7 258.2h3.8M119.9 244.3h1.5v5h-1.5zM120.6 249.3v8.9M122.4 244.3h1.5v5h-1.5zM123.2 249.3v1.3M124.9 244.3h1.6v5h-1.6zM125.7 249.3v1.3M127.5 244.3h1.5v5h-1.5zM128.2 249.3v1.3M130 244.3h1.6v5h-1.6zM130.8 249.3v1.3"/>
<path d="M132.6 244.3h1.5v5h-1.5zM133.3 249.3v1.3M135.1 244.3h1.5v5h-1.5zM135.9 249.3v1.3M137.6 244.3h1.6v5h-1.6zM138.4 249.3v1.3h-17.8M144.1 250.6h3.8M146 245.5h5.7M151.7 243h-5.7v7.6M212.7 258.2h3.8M213.8 244.3h1.6v5h-1.6zM214.6 249.3v8.9"/>
<path d="M216.4 244.3h1.5v5h-1.5zM217.1 249.3v1.3M218.9 244.3h1.6v5h-1.6zM219.7 249.3v1.3M221.5 244.3h1.5v5h-1.5zM222.2 249.3v1.3M224 244.3h1.5v5h-1.5zM224.8 249.3v1.3M226.5 244.3h1.6v5h-1.6zM227.3 249.3v1.3M229.1 244.3h1.5v5h-1.5zM229.8 249.3v1.3"/>
<path d="M231.6 244.3h1.6v5h-1.6zM232.4 249.3v1.3h-17.8M238.1 250.6h3.8M240 245.5h5.6M245.6 243h-5.6v7.6M313.6 249.3h86.4M313.6 254.4h86.4M313.6 259.5h86.4M372.1 259.5v5.1M29.8 265.9h3.9M67.8 274.7v3.9M115.2 274.7v3.9"/>
<path d="M162.7 274.7v3.9M210.2 274.7v3.9M257.6 274.7v3.9M305.1 274.7v3.9M313.6 264.6h86.4M313.6 269.7h86.4M352.6 274.7v3.9M400 274.6h.1"/>
<circle cx="169.9" cy="225.2" r=".99"/>
<circle cx="169.9" cy="220.1" r=".99"/>
<circle cx="169.9" cy="237.9" r=".99"/>
<circle cx="169.9" cy="235.4" r=".99"/>
<circle cx="169.9" cy="227.8" r=".99"/>
<circle cx="169.9" cy="222.7" r=".99"/>
<circle cx="169.9" cy="232.8" r=".99"/>
<circle cx="169.9" cy="230.3" r=".99"/>
<circle cx="263.8" cy="225.2" r=".99"/>
<circle cx="263.8" cy="235.4" r=".99"/>
<circle cx="263.8" cy="232.8" r=".99"/>
<circle cx="263.8" cy="222.7" r=".99"/>
<circle cx="263.8" cy="230.3" r=".99"/>
<circle cx="263.8" cy="227.8" r=".99"/>
<circle cx="263.8" cy="220.1" r=".99"/>
<circle cx="263.8" cy="237.9" r=".99"/>
<circle cx="152.7" cy="245.5" r=".99"/>
<circle cx="152.7" cy="243" r=".99"/>
<circle cx="246.6" cy="243" r=".99"/>
<circle cx="246.6" cy="245.5" r=".99"/>
</g>
<g fill="none" stroke="#000" stroke-width=".61">
<path d="M20.3 22.1h379.7v252.6h-379.7zM358.1 67.8h1.3M358.1 70.3h1.3M358.1 72.9h1.3M358.1 75.4h1.3M358.1 77.9h1.3M375.9 67.8h1.2M375.9 70.3h1.2M375.9 72.9h1.2M375.9 75.4h1.2M375.9 77.9h1.2M358.1 80.5h1.3"/>
<path d="M358.1 83h1.3M358.1 85.6h1.3M358.1 88.1h1.3M358.1 90.6h1.3M375.9 80.5h1.2M375.9 83h1.2M375.9 85.6h1.2M375.9 88.1h1.2M375.9 90.6h1.2M153.6 217.6h15.3v30.5h-15.3zM247.6 217.6h15.3v30.5h-15.3zM297.1 215.1h1.3"/>
<path d="M297.1 212.5h1.3M297.1 210h1.3M297.1 217.6h1.3M297.1 220.1h1.3M313.6 244.3v30.4M400 244.3h-116.8v30.4"/>
</g>
<path d="M16.5 18.2h387.3v260.4h-387.3z" fill="none" stroke="#000" stroke-width=".32"/>
<g fill="#000" stroke="#000" stroke-width=".25">
<path d="M62 57.4h2.8v.5h-2.8zM87.6 57.4h2.8v.5h-2.8zM168.6 49.7h2.8v.5h-2.8zM168.6 52.3h2.8v.5h-2.8zM168.6 54.8h2.8v.5h-2.8zM168.6 57.4h2.8v.5h-2.8zM168.6 59.9h2.8v.5h-2.8zM194.3 49.7h2.8v.5h-2.8zM194.3 52.3h2.8v.5h-2.8zM194.3 54.8h2.8v.5h-2.8zM194.3 57.4h2.8v.5h-2.8zM194.3 59.9h2.8v.5h-2.8z"/>
<path d="M262.6 47.2h2.8v.5h-2.8zM262.6 49.7h2.8v.5h-2.8zM262.6 52.3h2.8v.5h-2.8zM262.6 54.8h2.8v.5h-2.8zM262.6 57.4h2.8v.5h-2.8zM262.6 59.9h2.8v.5h-2.8zM288.2 47.2h2.8v.5h-2.8zM288.2 49.7h2.8v.5h-2.8zM288.2 52.3h2.8v.5h-2.8zM288.2 54.8h2.8v.5h-2.8zM288.2 57.4h2.8v.5h-2.8zM288.2 59.9h2.8v.5h-2.8z"/>
<path d="M62 62.4h2.8v.5h-2.8zM62 67.5h2.8v.5h-2.8zM62 72.6h2.8v.5h-2.8zM62 77.7h2.8v.5h-2.8zM87.6 62.4h2.8v.5h-2.8zM87.6 67.5h2.8v.5h-2.8zM87.6 72.6h2.8v.5h-2.8zM87.6 77.7h2.8v.5h-2.8zM168.6 62.4h2.8v.5h-2.8zM168.6 65h2.8v.5h-2.8zM168.6 67.5h2.8v.5h-2.8zM168.6 70.1h2.8v.5h-2.8z"/>
<path d="M168.6 72.6h2.8v.5h-2.8zM168.6 75.1h2.8v.5h-2.8zM168.6 77.7h2.8v.5h-2.8zM194.3 62.4h2.8v.5h-2.8zM194.3 65h2.8v.5h-2.8zM194.3 67.5h2.8v.5h-2.8zM194.3 70.1h2.8v.5h-2.8zM194.3 72.6h2.8v.5h-2.8zM194.3 75.1h2.8v.5h-2.8zM194.3 77.7h2.8v.5h-2.8zM262.6 62.4h2.8v.5h-2.8zM262.6 65h2.8v.5h-2.8z"/>
<path d="M262.6 67.5h2.8v.5h-2.8zM262.6 70.1h2.8v.5h-2.8zM262.6 72.6h2.8v.5h-2.8zM262.6 75.1h2.8v.5h-2.8zM262.6 77.7h2.8v.5h-2.8zM288.2 62.4h2.8v.5h-2.8zM288.2 65h2.8v.5h-2.8zM288.2 67.5h2.8v.5h-2.8zM288.2 70.1h2.8v.5h-2.8zM288.2 72.6h2.8v.5h-2.8zM288.2 75.1h2.8v.5h-2.8zM288.2 77.7h2.8v.5h-2.8z"/>
<path d="M62 82.8h2.8v.5h-2.8zM62 87.8h2.8v.5h-2.8zM62 92.9h2.8v.5h-2.8zM62 98h2.8v.5h-2.8zM87.6 82.8h2.8v.5h-2.8zM87.6 87.8h2.8v.5h-2.8zM87.6 92.9h2.8v.5h-2.8zM87.6 98h2.8v.5h-2.8zM168.6 80.2h2.8v.5h-2.8zM168.6 82.8h2.8v.5h-2.8zM168.6 85.3h2.8v.5h-2.8zM168.6 87.8h2.8v.5h-2.8z"/>
<path d="M168.6 90.4h2.8v.5h-2.8zM168.6 92.9h2.8v.5h-2.8zM168.6 95.5h2.8v.5h-2.8zM168.6 98h2.8v.5h-2.8zM194.3 80.2h2.8v.5h-2.8zM194.3 82.8h2.8v.5h-2.8zM194.3 85.3h2.8v.5h-2.8zM194.3 87.8h2.8v.5h-2.8zM194.3 90.4h2.8v.5h-2.8zM194.3 92.9h2.8v.5h-2.8zM194.3 95.5h2.8v.5h-2.8zM194.3 98h2.8v.5h-2.8z"/>
<path d="M262.6 80.2h2.8v.5h-2.8zM262.6 82.8h2.8v.5h-2.8zM262.6 85.3h2.8v.5h-2.8zM262.6 87.8h2.8v.5h-2.8zM262.6 90.4h2.8v.5h-2.8zM262.6 92.9h2.8v.5h-2.8zM262.6 95.5h2.8v.5h-2.8zM288.2 80.2h2.8v.5h-2.8zM288.2 82.8h2.8v.5h-2.8zM288.2 85.3h2.8v.5h-2.8zM288.2 87.8h2.8v.5h-2.8zM288.2 90.4h2.8v.5h-2.8z"/>
<path d="M288.2 92.9h2.8v.5h-2.8zM288.2 95.5h2.8v.5h-2.8zM381.5 95.5h4v.5h-4zM62 103.1h2.8v.5h-2.8zM62 108.1h2.8v.5h-2.8zM62 113.2h2.8v.5h-2.8zM62 118.3h2.8v.5h-2.8zM87.6 103.1h2.8v.5h-2.8zM87.6 108.1h2.8v.5h-2.8zM87.6 113.2h2.8v.5h-2.8zM87.6 118.3h2.8v.5h-2.8zM168.6 118.3h2.8v.5h-2.8z"/>
<path d="M194.3 118.3h2.8v.5h-2.8zM260.1 118.3h2.8v.5h-2.8zM288.2 118.3h2.8v.5h-2.8zM62 123.4h2.8v.5h-2.8zM62 128.5h2.8v.5h-2.8zM62 133.5h2.8v.5h-2.8zM62 138.6h2.8v.5h-2.8zM87.6 123.4h2.8v.5h-2.8zM87.6 128.5h2.8v.5h-2.8zM87.6 133.5h2.8v.5h-2.8zM87.6 138.6h2.8v.5h-2.8zM168.6 120.8h2.8v.5h-2.8z"/>
<path d="M168.6 123.4h2.8v.5h-2.8zM168.6 125.9h2.8v.5h-2.8zM168.6 128.5h2.8v.5h-2.8zM168.6 131h2.8v.5h-2.8zM168.6 133.5h2.8v.5h-2.8zM168.6 136.1h2.8v.5h-2.8zM168.6 138.6h2.8v.5h-2.8zM194.3 120.8h2.8v.5h-2.8zM194.3 123.4h2.8v.5h-2.8zM194.3 125.9h2.8v.5h-2.8zM194.3 128.5h2.8v.5h-2.8zM194.3 131h2.8v.5h-2.8z"/>
<path d="M194.3 133.5h2.8v.5h-2.8zM194.3 136.1h2.8v.5h-2.8zM194.3 138.6h2.8v.5h-2.8zM260.1 120.8h2.8v.5h-2.8zM260.1 123.4h2.8v.5h-2.8zM260.1 125.9h2.8v.5h-2.8zM260.1 128.5h2.8v.5h-2.8zM260.1 131h2.8v.5h-2.8zM260.1 133.5h2.8v.5h-2.8zM260.1 136.1h2.8v.5h-2.8zM260.1 138.6h2.8v.5h-2.8zM288.2 120.8h2.8v.5h-2.8z"/>
<path d="M288.2 123.4h2.8v.5h-2.8zM288.2 125.9h2.8v.5h-2.8zM288.2 128.5h2.8v.5h-2.8zM288.2 131h2.8v.5h-2.8zM288.2 133.5h2.8v.5h-2.8zM288.2 136.1h2.8v.5h-2.8zM288.2 138.6h2.8v.5h-2.8zM62 143.7h2.8v.5h-2.8zM62 148.8h2.8v.5h-2.8zM62 153.9h2.8v.5h-2.8zM62 158.9h2.8v.5h-2.8zM87.6 143.7h2.8v.5h-2.8z"/>
<path d="M87.6 148.8h2.8v.5h-2.8zM87.6 153.9h2.8v.5h-2.8zM87.6 158.9h2.8v.5h-2.8zM168.6 141.2h2.8v.5h-2.8zM168.6 143.7h2.8v.5h-2.8zM168.6 146.2h2.8v.5h-2.8zM168.6 148.8h2.8v.5h-2.8zM168.6 151.3h2.8v.5h-2.8zM168.6 153.9h2.8v.5h-2.8zM168.6 156.4h2.8v.5h-2.8zM168.6 158.9h2.8v.5h-2.8zM194.3 141.2h2.8v.5h-2.8z"/>
<path d="M194.3 143.7h2.8v.5h-2.8zM194.3 146.2h2.8v.5h-2.8zM194.3 148.8h2.8v.5h-2.8zM194.3 151.3h2.8v.5h-2.8zM194.3 153.9h2.8v.5h-2.8zM194.3 156.4h2.8v.5h-2.8zM194.3 158.9h2.8v.5h-2.8zM260.1 141.2h2.8v.5h-2.8zM260.1 143.7h2.8v.5h-2.8zM260.1 146.2h2.8v.5h-2.8zM260.1 148.8h2.8v.5h-2.8zM260.1 151.3h2.8v.5h-2.8z"/>
<path d="M260.1 153.9h2.8v.5h-2.8zM260.1 156.4h2.8v.5h-2.8zM260.1 158.9h2.8v.5h-2.8zM288.2 141.2h2.8v.5h-2.8zM288.2 143.7h2.8v.5h-2.8zM288.2 146.2h2.8v.5h-2.8zM288.2 148.8h2.8v.5h-2.8zM288.2 151.3h2.8v.5h-2.8zM288.2 153.9h2.8v.5h-2.8zM288.2 156.4h2.8v.5h-2.8zM288.2 158.9h2.8v.5h-2.8zM62 164h2.8v.5h-2.8z"/>
<path d="M62 169.1h2.8v.5h-2.8zM62 174.2h2.8v.5h-2.8zM62 179.3h2.8v.5h-2.8zM87.6 164h2.8v.5h-2.8zM87.6 169.1h2.8v.5h-2.8zM87.6 174.2h2.8v.5h-2.8zM87.6 179.3h2.8v.5h-2.8zM168.6 161.5h2.8v.5h-2.8zM168.6 164h2.8v.5h-2.8zM168.6 166.6h2.8v.5h-2.8zM194.3 161.5h2.8v.5h-2.8zM194.3 164h2.8v.5h-2.8z"/>
<path d="M194.3 166.6h2.8v.5h-2.8zM260.1 161.5h2.8v.5h-2.8zM260.1 164h2.8v.5h-2.8zM260.1 166.6h2.8v.5h-2.8zM288.2 161.5h2.8v.5h-2.8zM288.2 164h2.8v.5h-2.8zM288.2 166.6h2.8v.5h-2.8zM55.1 184.3h4.1v.5h-4.1zM93.2 184.3h4.1v.5h-4.1zM29.7 253.7h4.1v.5h-4.1zM29.7 254.7h4.1v.5h-4.1zM37.3 253.7h4.1v.5h-4.1z"/>
<path d="M37.3 254.7h4.1v.5h-4.1zM47.5 253.7h4.1v.5h-4.1zM47.5 254.7h4.1v.5h-4.1zM118.6 258h4.1v.5h-4.1zM144 250.4h4.1v.5h-4.1zM212.6 258h4v.5h-4zM238 250.4h4v.5h-4zM29.7 265.6h4.1v.5h-4.1z"/>
</g>
<g fill="none" stroke="#000" stroke-width=".42">
<path d="M294.6 207.5h5.1v15.2h-5.1zM118.1 243h22.8v8.9h-22.8zM212.1 243h22.8v8.9h-22.8z"/>
<circle cx="120.6" cy="250.6" r=".25"/>
<circle cx="123.2" cy="250.6" r=".25"/>
<circle cx="125.7" cy="250.6" r=".25"/>
<circle cx="128.2" cy="250.6" r=".25"/>
<circle cx="130.8" cy="250.6" r=".25"/>
<circle cx="133.3" cy="250.6" r=".25"/>
<circle cx="135.9" cy="250.6" r=".25"/>
<circle cx="214.6" cy="250.6" r=".25"/>
<circle cx="217.1" cy="250.6" r=".25"/>
<circle cx="219.7" cy="250.6" r=".25"/>
<circle cx="222.2" cy="250.6" r=".25"/>
<circle cx="224.8" cy="250.6" r=".25"/>
<circle cx="227.3" cy="250.6" r=".25"/>
<circle cx="229.8" cy="250.6" r=".25"/>
</g>
<path d="M328.9 60.2h5.1l2.5 2.5v20.3M140.9 110.9h5.1l2.6 2.6v43.2" fill="none" stroke="#000" stroke-width=".76"/>
<g fill="#000" stroke="#000" stroke-width=".25">
<circle cx="383.5" cy="77.9" r=".51"/>
<circle cx="383.5" cy="72.9" r=".51"/>
<circle cx="383.5" cy="70.3" r=".51"/>
<circle cx="383.5" cy="75.4" r=".51"/>
<circle cx="383.5" cy="88.1" r=".51"/>
<circle cx="383.5" cy="90.6" r=".51"/>
<circle cx="383.5" cy="85.6" r=".51"/>
<circle cx="383.5" cy="83" r=".51"/>
<circle cx="383.5" cy="80.5" r=".51"/>
<circle cx="57.1" cy="138.9" r=".51"/>
<circle cx="57.1" cy="154.1" r=".51"/>
<circle cx="95.2" cy="154.1" r=".51"/>
<circle cx="57.1" cy="174.4" r=".51"/>
<circle cx="57.1" cy="179.5" r=".51"/>
<circle cx="95.2" cy="169.4" r=".51"/>
<circle cx="120.6" cy="220.1" r=".51"/>
<circle cx="123.2" cy="222.7" r=".51"/>
<circle cx="125.7" cy="225.2" r=".51"/>
<circle cx="128.2" cy="227.8" r=".51"/>
<circle cx="130.8" cy="230.3" r=".51"/>
<circle cx="133.3" cy="232.8" r=".51"/>
<circle cx="135.9" cy="235.4" r=".51"/>
<circle cx="138.4" cy="237.9" r=".51"/>
<circle cx="214.6" cy="220.1" r=".51"/>
<circle cx="217.1" cy="222.7" r=".51"/>
<circle cx="219.7" cy="225.2" r=".51"/>
<circle cx="222.2" cy="227.8" r=".51"/>
<circle cx="224.8" cy="230.3" r=".51"/>
<circle cx="227.3" cy="232.8" r=".51"/>
<circle cx="229.8" cy="235.4" r=".51"/>
<circle cx="232.4" cy="237.9" r=".51"/>
<circle cx="39.4" cy="248.1" r=".51"/>
<circle cx="49.5" cy="248.1" r=".51"/>
<circle cx="146" cy="245.5" r=".51"/>
<circle cx="240" cy="245.5" r=".51"/>
<circle cx="31.7" cy="260.8" r=".51"/>
<circle cx="39.4" cy="260.8" r=".51"/>
</g>
<use href="#words"/>
</svg>
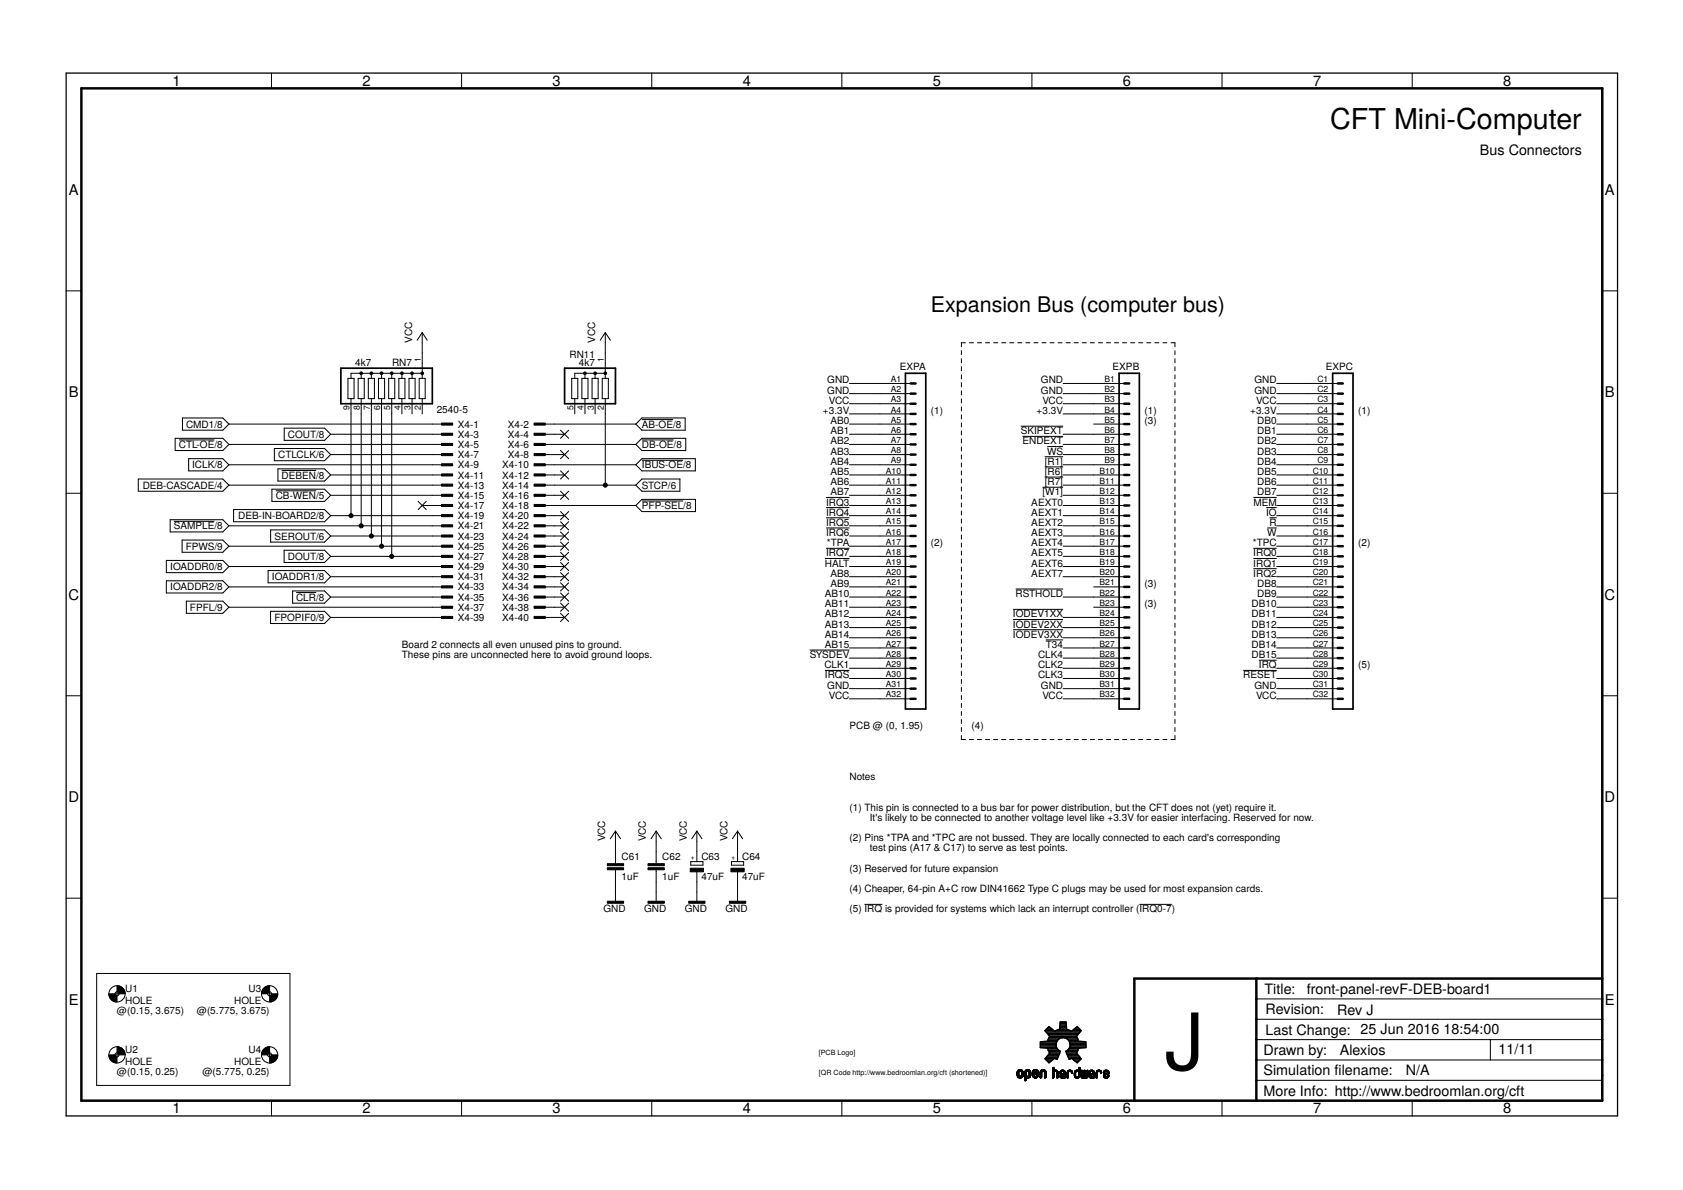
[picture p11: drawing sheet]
<svg xmlns="http://www.w3.org/2000/svg" width="420mm" height="297mm" viewBox="0 0 420 297" stroke-linecap="round" stroke-linejoin="round" font-family="sans-serif">
<defs><g id="words">
<text font-size="19.7" x="290.8" y="267.1">J</text>
<text font-size="7.2" x="332.1" y="32.2">CFT Mini-Computer</text>
<text font-size="5.4" x="232.4" y="77.9">Expansion Bus (computer bus)</text>
<g font-size="3.7">
<text x="43" y="21.4">1</text>
<text x="90.5" y="21.4">2</text>
<text x="138" y="21.4">3</text>
<text x="185.4" y="21.4">4</text>
<text x="232.9" y="21.4">5</text>
<text x="280.3" y="21.4">6</text>
<text x="327.8" y="21.4">7</text>
<text x="375.3" y="21.4">8</text>
<text x="17.2" y="48.6">A</text>
<text x="400.7" y="48.6">A</text>
<text x="17.2" y="99.2">B</text>
<text x="400.7" y="99.2">B</text>
<text x="17.1" y="149.7">C</text>
<text x="400.6" y="149.7">C</text>
<text x="17.1" y="200.2">D</text>
<text x="400.6" y="200.2">D</text>
<text x="17.2" y="250.8">E</text>
<text x="400.7" y="250.8">E</text>
<text x="43" y="277.9">1</text>
<text x="90.5" y="277.9">2</text>
<text x="138" y="277.9">3</text>
<text x="185.4" y="277.9">4</text>
<text x="232.9" y="277.9">5</text>
<text x="280.3" y="277.9">6</text>
<text x="327.8" y="277.9">7</text>
<text x="375.3" y="277.9">8</text>
</g>
<g font-size="3.6">
<text x="369.5" y="38.6">Bus Connectors</text>
<text x="315.7" y="248.1">Title:</text>
<text x="326.2" y="248.2">front-panel-revF-DEB-board1</text>
<text x="315.9" y="253.2">Revision:</text>
<text x="333.8" y="253.3">Rev J</text>
<text x="315.4" y="263.3">Drawn by:</text>
<text x="315.9" y="258.2">Last Change: 25 Jun 2016</text>
<text x="334.5" y="263.3">Alexios</text>
<text x="360.4" y="258.1">18:54:00</text>
<text x="374.1" y="263.2">11/11</text>
<text x="315.4" y="268.4">Simulation flename:</text>
<text x="333.2" y="268.4">i</text>
<text x="351" y="268.4">N/A</text>
<text x="315.4" y="273.5">More Info: http://www.bedroomlan.org/cft</text>
</g>
<g font-size="2.5">
<text x="102.9" y="85.5" transform="rotate(-90 102.9 85.5)">VCC</text>
<text x="142.2" y="89.4">RN11</text>
<text x="148.6" y="85.5" transform="rotate(-90 148.6 85.5)">VCC</text>
<text x="88.7" y="91.3">4k7</text>
<text x="97.9" y="91.3">RN7</text>
<text x="144.5" y="91.3">4k7</text>
<text x="206.5" y="95.7">GND</text>
<text x="224.6" y="92.4">EXPA</text>
<text x="259.9" y="95.7">GND</text>
<text x="277.8" y="92.4">EXPB</text>
<text x="313.2" y="95.7">GND</text>
<text x="331" y="92.4">EXPC</text>
<text x="206.5" y="98.2">GND</text>
<text x="206.9" y="100.8">VCC</text>
<text x="259.9" y="98.2">GND</text>
<text x="260.2" y="100.8">VCC</text>
<text x="313.2" y="98.2">GND</text>
<text x="313.6" y="100.8">VCC</text>
<text x="46.5" y="106.8">CMD1/8</text>
<text x="109" y="103.2">2540-5</text>
<text x="114.3" y="106.8">X4-1</text>
<text x="126.8" y="106.8">X4-2</text>
<text x="160.3" y="106.8">AB-OE/8</text>
<text x="205.4" y="103.3">+3.3V</text>
<text x="207.3" y="105.9">AB0</text>
<text x="232.4" y="103.3">(1)</text>
<text x="258.8" y="103.3">+3.3V</text>
<text x="285.7" y="103.3">(1)</text>
<text x="285.7" y="105.9">(3)</text>
<text x="312.1" y="103.3">+3.3V</text>
<text x="313.9" y="105.9">DB0</text>
<text x="339.1" y="103.3">(1)</text>
<text x="44.7" y="111.8">CTL-OE/8</text>
<text x="71.9" y="109.3">COUT/8</text>
<text x="114.3" y="109.3">X4-3</text>
<text x="114.3" y="111.8">X4-5</text>
<text x="126.8" y="109.3">X4-4</text>
<text x="126.8" y="111.8">X4-6</text>
<text x="160.3" y="111.8">DB-OE/8</text>
<text x="207.3" y="113.5">AB3</text>
<text x="207.3" y="110.9">AB2</text>
<text x="207.3" y="108.4">AB1</text>
<text x="254.8" y="108.4">SKIPEXT</text>
<text x="255.3" y="110.9">ENDEXT</text>
<text x="261.4" y="113.5">WS</text>
<text x="313.9" y="113.5">DB3</text>
<text x="313.9" y="110.9">DB2</text>
<text x="313.9" y="108.4">DB1</text>
<text x="48" y="116.9">ICLK/8</text>
<text x="69.4" y="114.4">CTLCLK/6</text>
<text x="70.3" y="119.5">DEBEN/8</text>
<text x="114.3" y="114.4">X4-7</text>
<text x="114.3" y="116.9">X4-9</text>
<text x="114.3" y="119.5">X4-11</text>
<text x="125.4" y="116.9">X4-10</text>
<text x="125.4" y="119.5">X4-12</text>
<text x="126.8" y="114.4">X4-8</text>
<text x="160.3" y="116.9">IBUS-OE/8</text>
<text x="207.3" y="118.6">AB5</text>
<text x="207.3" y="116">AB4</text>
<text x="260.8" y="116">[R1]</text>
<text x="260.8" y="118.6">[R6]</text>
<text x="313.9" y="118.6">DB5</text>
<text x="313.9" y="116">DB4</text>
<text x="35.6" y="122">DEB-CASCADE/4</text>
<text x="68.8" y="124.5">CB-WEN/5</text>
<text x="114.3" y="122">X4-13</text>
<text x="114.3" y="124.5">X4-15</text>
<text x="125.4" y="122">X4-14</text>
<text x="125.4" y="124.5">X4-16</text>
<text x="160.3" y="122">STCP/6</text>
<text x="207.3" y="123.6">AB7</text>
<text x="207.3" y="121.1">AB6</text>
<text x="260.3" y="123.6">[W1]</text>
<text x="260.8" y="121.1">[R7]</text>
<text x="313.9" y="123.6">DB7</text>
<text x="313.9" y="121.1">DB6</text>
<text x="59.4" y="129.6">DEB-IN-BOARD2/8</text>
<text x="114.3" y="127.1">X4-17</text>
<text x="114.3" y="129.6">X4-19</text>
<text x="125.4" y="127.1">X4-18</text>
<text x="125.4" y="129.6">X4-20</text>
<text x="160.3" y="127.1">PFP-SEL/8</text>
<text x="206.2" y="126.2">IRQ3</text>
<text x="206.2" y="128.7">IRQ4</text>
<text x="206.2" y="131.3">IRQ5</text>
<text x="257.5" y="131.3">AEXT2</text>
<text x="257.5" y="128.7">AEXT1</text>
<text x="257.5" y="126.2">AEXT0</text>
<text x="312.9" y="126.2">MEM</text>
<text x="316.1" y="128.7">IO</text>
<text x="316.9" y="131.3">R</text>
<text x="43.4" y="132.1">SAMPLE/8</text>
<text x="46.4" y="137.2">FPWS/9</text>
<text x="68.6" y="134.7">SEROUT/6</text>
<text x="114.3" y="132.1">X4-21</text>
<text x="114.3" y="134.7">X4-23</text>
<text x="114.3" y="137.2">X4-25</text>
<text x="125.4" y="132.1">X4-22</text>
<text x="125.4" y="134.7">X4-24</text>
<text x="125.4" y="137.2">X4-26</text>
<text x="206.2" y="133.8">IRQ6</text>
<text x="206.4" y="136.3">*TPA</text>
<text x="232.4" y="136.3">(2)</text>
<text x="257.5" y="136.3">AEXT4</text>
<text x="257.5" y="133.8">AEXT3</text>
<text x="312.8" y="136.3">*TPC</text>
<text x="316.4" y="133.8">W</text>
<text x="339.1" y="136.3">(2)</text>
<text x="42.5" y="142.3">IOADDR0/8</text>
<text x="71.9" y="139.8">DOUT/8</text>
<text x="114.3" y="139.8">X4-27</text>
<text x="114.3" y="142.3">X4-29</text>
<text x="125.4" y="139.8">X4-28</text>
<text x="125.4" y="142.3">X4-30</text>
<text x="205.9" y="141.4">HALT</text>
<text x="206.2" y="138.9">IRQ7</text>
<text x="207.3" y="144">AB8</text>
<text x="257.5" y="144">AEXT7</text>
<text x="257.5" y="141.4">AEXT6</text>
<text x="257.5" y="138.9">AEXT5</text>
<text x="312.9" y="138.9">IRQ0</text>
<text x="312.9" y="144">IRQ2</text>
<text x="312.9" y="141.4">IRQ1</text>
<text x="42.5" y="147.4">IOADDR2/8</text>
<text x="67.9" y="144.8">IOADDR1/8</text>
<text x="73.9" y="149.9">CLR/8</text>
<text x="114.3" y="144.8">X4-31</text>
<text x="114.3" y="147.4">X4-33</text>
<text x="114.3" y="149.9">X4-35</text>
<text x="125.4" y="144.8">X4-32</text>
<text x="125.4" y="147.4">X4-34</text>
<text x="125.4" y="149.9">X4-36</text>
<text x="205.9" y="149">AB10</text>
<text x="207.3" y="146.5">AB9</text>
<text x="253.5" y="149">RSTHOLD</text>
<text x="285.7" y="146.5">(3)</text>
<text x="313.9" y="149">DB9</text>
<text x="313.9" y="146.5">DB8</text>
<text x="47.4" y="152.5">FPFL/9</text>
<text x="68.5" y="155">FPOPIF0/9</text>
<text x="114.3" y="152.5">X4-37</text>
<text x="114.3" y="155">X4-39</text>
<text x="125.4" y="152.5">X4-38</text>
<text x="125.4" y="155">X4-40</text>
<text x="205.9" y="154.1">AB12</text>
<text x="205.9" y="151.6">AB11</text>
<text x="252.9" y="154.1">IODEV1XX</text>
<text x="285.7" y="151.6">(3)</text>
<text x="312.5" y="154.1">DB11</text>
<text x="312.5" y="151.6">DB10</text>
<text x="100.3" y="161.7">Board 2 connects all even unused pins to ground.</text>
<text x="205.9" y="161.7">AB15</text>
<text x="205.9" y="159.2">AB14</text>
<text x="205.9" y="156.7">AB13</text>
<text x="252.9" y="159.2">IODEV3XX</text>
<text x="252.9" y="156.7">IODEV2XX</text>
<text x="261.1" y="161.7">T34</text>
<text x="312.5" y="161.7">DB14</text>
<text x="312.5" y="159.2">DB13</text>
<text x="312.5" y="156.7">DB12</text>
<text x="100.3" y="164.3">These pins are unconnected here to avoid ground loops.</text>
<text x="202.1" y="164.3">SYSDEV</text>
<text x="205.8" y="166.8">CLK1</text>
<text x="259.1" y="166.8">CLK2</text>
<text x="259.1" y="164.3">CLK4</text>
<text x="312.5" y="164.3">DB15</text>
<text x="314.3" y="166.8">IRQ</text>
<text x="339.1" y="166.8">(5)</text>
<text x="205.9" y="169.4">IRQS</text>
<text x="206.5" y="171.9">GND</text>
<text x="259.1" y="169.4">CLK3</text>
<text x="259.9" y="171.9">GND</text>
<text x="310.4" y="169.4">RESET</text>
<text x="313.2" y="171.9">GND</text>
<text x="206.9" y="174.4">VCC</text>
<text x="260.2" y="174.4">VCC</text>
<text x="313.6" y="174.4">VCC</text>
<text x="212.1" y="182.1">PCB @ (0, 1.95)</text>
<text x="242.5" y="182.1">(4)</text>
<text x="212.1" y="194.7">Notes</text>
<text x="212.1" y="202.4">(1) This pin is connected to a bus bar for power distribution, but the CFT does not (yet) require it.</text>
<text x="151.1" y="210" transform="rotate(-90 151.1 210)">VCC</text>
<text x="161.3" y="210" transform="rotate(-90 161.3 210)">VCC</text>
<text x="171.4" y="210" transform="rotate(-90 171.4 210)">VCC</text>
<text x="181.6" y="210" transform="rotate(-90 181.6 210)">VCC</text>
<text x="212.1" y="210">(2) Pins *TPA and *TPC are not bussed. They are locally connected to each card's corresponding</text>
<text x="217.1" y="204.9">It's likely to be connected to another voltage level like +3.3V for easier interfacing. Reserved for now.</text>
<text x="155.2" y="214.7">C61</text>
<text x="165.3" y="214.7">C62</text>
<text x="175.1" y="214.6">C63</text>
<text x="185.3" y="214.6">C64</text>
<text x="217.1" y="212.5">test pins (A17 &amp; C17) to serve as test points.</text>
<text x="155.2" y="219.8">1uF</text>
<text x="165.3" y="219.8">1uF</text>
<text x="175.1" y="219.7">47uF</text>
<text x="185.3" y="219.7">47uF</text>
<text x="212.1" y="217.6">(3) Reserved for future expansion</text>
<text x="150.6" y="227.8">GND</text>
<text x="160.8" y="227.8">GND</text>
<text x="171" y="227.8">GND</text>
<text x="181.1" y="227.8">GND</text>
<text x="212.1" y="222.7">(4) Cheaper, 64-pin A+C row DIN41662 Type C plugs may be used for most expansion cards.</text>
<text x="212.1" y="227.8">(5) IRQ is provided for systems which lack an interrupt controller (IRQ0-7)</text>
<text x="31.2" y="250.5">HOLE</text>
<text x="31.2" y="247.5">U1</text>
<text x="58.5" y="250.5">HOLE</text>
<text x="62.1" y="247.5">U3</text>
<text x="29.2" y="253.2">@(0.15, 3.675)</text>
<text x="49.1" y="253.2">@(5.775, 3.675)</text>
<text x="31.2" y="262.7">U2</text>
<text x="62.1" y="262.7">U4</text>
<text x="29.2" y="268.4">@(0.15, 0.25)</text>
<text x="31.2" y="265.8">HOLE</text>
<text x="50.5" y="268.4">@(5.775, 0.25)</text>
<text x="58.5" y="265.8">HOLE</text>
</g>
<g font-size="2.1">
<text x="105" y="90.3" transform="rotate(-90 105 90.3)">1</text>
<text x="150.8" y="90.3" transform="rotate(-90 150.8 90.3)">1</text>
<text x="222.4" y="95.4">A1</text>
<text x="275.7" y="95.4">B1</text>
<text x="328.9" y="95.4">C1</text>
<text x="222.4" y="97.9">A2</text>
<text x="222.4" y="100.4">A3</text>
<text x="275.7" y="97.9">B2</text>
<text x="275.7" y="100.4">B3</text>
<text x="328.9" y="97.9">C2</text>
<text x="328.9" y="100.4">C3</text>
<text x="87.3" y="102.3" transform="rotate(-90 87.3 102.3)">9</text>
<text x="89.8" y="102.3" transform="rotate(-90 89.8 102.3)">8</text>
<text x="92.3" y="102.3" transform="rotate(-90 92.3 102.3)">7</text>
<text x="94.9" y="102.3" transform="rotate(-90 94.9 102.3)">6</text>
<text x="97.4" y="102.3" transform="rotate(-90 97.4 102.3)">5</text>
<text x="100" y="102.3" transform="rotate(-90 100 102.3)">4</text>
<text x="102.5" y="102.3" transform="rotate(-90 102.5 102.3)">3</text>
<text x="105" y="102.3" transform="rotate(-90 105 102.3)">2</text>
<text x="143.1" y="102.3" transform="rotate(-90 143.1 102.3)">5</text>
<text x="145.7" y="102.3" transform="rotate(-90 145.7 102.3)">4</text>
<text x="148.2" y="102.3" transform="rotate(-90 148.2 102.3)">3</text>
<text x="150.8" y="102.3" transform="rotate(-90 150.8 102.3)">2</text>
<text x="222.4" y="103">A4</text>
<text x="222.4" y="105.5">A5</text>
<text x="275.7" y="103">B4</text>
<text x="275.7" y="105.5">B5</text>
<text x="328.9" y="103">C4</text>
<text x="328.9" y="105.5">C5</text>
<text x="222.4" y="108">A6</text>
<text x="222.4" y="110.6">A7</text>
<text x="222.4" y="113.1">A8</text>
<text x="275.7" y="108">B6</text>
<text x="275.7" y="110.6">B7</text>
<text x="275.7" y="113.1">B8</text>
<text x="328.9" y="108">C6</text>
<text x="328.9" y="110.6">C7</text>
<text x="328.9" y="113.1">C8</text>
<text x="221.2" y="118.2">A10</text>
<text x="222.4" y="115.7">A9</text>
<text x="274.5" y="118.2">B10</text>
<text x="275.7" y="115.7">B9</text>
<text x="327.7" y="118.2">C10</text>
<text x="328.9" y="115.7">C9</text>
<text x="221.2" y="120.7">A11</text>
<text x="221.2" y="123.3">A12</text>
<text x="221.2" y="125.8">A13</text>
<text x="274.5" y="120.7">B11</text>
<text x="274.5" y="123.3">B12</text>
<text x="274.5" y="125.8">B13</text>
<text x="327.7" y="120.7">C11</text>
<text x="327.7" y="123.3">C12</text>
<text x="327.7" y="125.8">C13</text>
<text x="221.2" y="128.4">A14</text>
<text x="221.2" y="130.9">A15</text>
<text x="274.5" y="128.4">B14</text>
<text x="274.5" y="130.9">B15</text>
<text x="327.7" y="128.4">C14</text>
<text x="327.7" y="130.9">C15</text>
<text x="221.2" y="133.4">A16</text>
<text x="221.2" y="136">A17</text>
<text x="274.5" y="133.4">B16</text>
<text x="274.5" y="136">B17</text>
<text x="327.7" y="133.4">C16</text>
<text x="327.7" y="136">C17</text>
<text x="221.2" y="138.5">A18</text>
<text x="221.2" y="141.1">A19</text>
<text x="221.2" y="143.6">A20</text>
<text x="274.5" y="138.5">B18</text>
<text x="274.5" y="141.1">B19</text>
<text x="274.5" y="143.6">B20</text>
<text x="327.7" y="138.5">C18</text>
<text x="327.7" y="141.1">C19</text>
<text x="327.7" y="143.6">C20</text>
<text x="221.2" y="146.1">A21</text>
<text x="221.2" y="148.7">A22</text>
<text x="274.5" y="146.1">B21</text>
<text x="274.5" y="148.7">B22</text>
<text x="327.7" y="146.1">C21</text>
<text x="327.7" y="148.7">C22</text>
<text x="221.2" y="151.2">A23</text>
<text x="221.2" y="153.8">A24</text>
<text x="274.5" y="151.2">B23</text>
<text x="274.5" y="153.8">B24</text>
<text x="327.7" y="151.2">C23</text>
<text x="327.7" y="153.8">C24</text>
<text x="221.2" y="156.3">A25</text>
<text x="221.2" y="158.8">A26</text>
<text x="221.2" y="161.4">A27</text>
<text x="274.5" y="156.3">B25</text>
<text x="274.5" y="158.8">B26</text>
<text x="274.5" y="161.4">B27</text>
<text x="327.7" y="156.3">C25</text>
<text x="327.7" y="158.8">C26</text>
<text x="327.7" y="161.4">C27</text>
<text x="221.2" y="163.9">A28</text>
<text x="221.2" y="166.5">A29</text>
<text x="274.5" y="163.9">B28</text>
<text x="274.5" y="166.5">B29</text>
<text x="327.7" y="163.9">C28</text>
<text x="327.7" y="166.5">C29</text>
<text x="221.2" y="169">A30</text>
<text x="221.2" y="171.5">A31</text>
<text x="274.5" y="169">B30</text>
<text x="274.5" y="171.5">B31</text>
<text x="327.7" y="169">C30</text>
<text x="327.7" y="171.5">C31</text>
<text x="221.2" y="174.1">A32</text>
<text x="274.5" y="174.1">B32</text>
<text x="327.7" y="174.1">C32</text>
</g>
<g font-size="1.8">
<text x="173.4" y="214.7" transform="rotate(-90 173.4 214.7)">+</text>
<text x="183.5" y="214.7" transform="rotate(-90 183.5 214.7)">+</text>
<text x="204.4" y="263.3">[PCB Logo]</text>
<text x="204.4" y="268.4">[QR Code http://www.bedroomlan.org/cft (shortened)]</text>
</g>
</g></defs>
<g fill="none" stroke="#000" stroke-width=".25">
<path d="M67.8 18.2v3.9M115.2 18.2v3.9M162.7 18.2v3.9M210.2 18.2v3.9M257.6 18.2v3.9M305.1 18.2v3.9M352.6 18.2v3.9M20.3 22.1h379.7v252.6h-379.7zM16.5 72.6h3.8M400 72.6h3.8M86.9 94.4h1.5v5.1h-1.5zM87.6 99.5v29.2"/>
<path d="M89.4 94.4h1.5v5.1h-1.5zM90.2 93.2v1.2M90.2 99.5v31.8M91.9 94.4h1.6v5.1h-1.6zM92.7 93.2v1.2M92.7 99.5v34.3M94.5 94.4h1.5v5.1h-1.5zM95.2 93.2v1.2M95.2 99.5v36.8M97 94.4h1.6v5.1h-1.6zM97.8 93.2v1.2M97.8 99.5v39.4"/>
<path d="M99.6 94.4h1.5v5.1h-1.5zM100.3 93.2v1.2M100.3 99.5v3.8M102.1 94.4h1.5v5.1h-1.5zM102.9 93.2v1.2M102.9 99.5v3.8M104.6 94.4h1.6v5.1h-1.6zM105.4 83v11.4M105.4 99.5v3.8M105.4 93.2h-17.8v1.2M105.4 83l1.3 1.9M105.4 83l-1.3 1.9"/>
<path d="M142.7 94.4h1.6v5.1h-1.6zM143.5 99.5v3.8M145.3 94.4h1.5v5.1h-1.5zM146 93.2v1.2M146 99.5v3.8M147.8 94.4h1.5v5.1h-1.5zM148.6 93.2v1.2M148.6 99.5v3.8M150.3 94.4h1.6v5.1h-1.6zM151.1 93.2h-7.6v1.2M151.1 83l1.3 1.9M151.1 83l-1.3 1.9"/>
<path d="M151.1 83v11.4M151.1 99.5v21.6M212.1 95.7h15.2M212.1 98.3h15.2M240 87.5v1M240 89.6v1M240 91.5v1M240 93.6v1M240 95.5v1.1M240 97.6v1M240 99.5v1.1M241 85.6h-1v1"/>
<path d="M242 85.6h1M244 85.6h1M246 85.6h1.1M248.1 85.6h1M250.1 85.6h1M252.1 85.6h1M254.1 85.6h1M256.1 85.6h1M258.1 85.6h1M260.1 85.6h1M262.1 85.6h1M264.2 85.6h1"/>
<path d="M265.4 95.7h15.2M265.4 98.3h15.2M266.2 85.6h1M268.2 85.6h1M270.2 85.6h1M272.2 85.6h1M274.2 85.6h1M276.2 85.6h1M278.2 85.6h1.1M280.2 85.6h1.1M282.3 85.6h1M284.3 85.6h1"/>
<path d="M286.3 85.6h1M288.3 85.6h1M290.3 85.6h1M292.3 85.6h1v1M293.3 87.5v1M293.3 89.6v1M293.3 91.5v1M293.3 93.6v1M293.3 95.5v1.1M293.3 97.6v1M293.3 99.5v1.1M318.7 95.7h15.3"/>
<path d="M318.7 98.3h15.3M34.5 119.6h21.1l1.5 1.5-1.5 1.5h-21.1zM43.7 109.4h11.9l1.5 1.5-1.5 1.6h-11.9zM44.7 109.8h8.8M45.6 104.3h10l1.5 1.6-1.5 1.5h-10zM47.1 114.5h8.5l1.5 1.5-1.5 1.5h-8.5zM57.1 105.9h53.4M57.1 110.9h53.4M57.1 116h53.4M68.5 112h12.5l1.5 1.5-1.5 1.5h-12.5zM69.4 117h11.6l1.5 1.6-1.5 1.5h-11.6zM70.3 117.4h8.6"/>
<path d="M71 106.9h10l1.5 1.5-1.5 1.5h-10zM82.5 108.4h28M82.5 113.5h28M82.5 118.6h28M135.9 105.9h22.8M135.9 108.4h5M135.9 110.9h22.8M135.9 113.5h5M135.9 116h22.8M135.9 118.6h5M139.9 107.4l2.1 2M139.9 112.5l2.1 2"/>
<path d="M139.9 117.5l2.1 2.1M142 107.4l-2.1 2M142 112.5l-2.1 2M142 117.5l-2.1 2.1M158.7 116l1.6-1.5h13.3v3h-13.3zM160.3 109.4h10.9v3.1h-10.9l-1.6-1.6zM160.3 109.8h7.9M160.3 104.3h10.7v3.1h-10.7l-1.6-1.5zM160.3 104.7h7.7M160.3 114.9h10.2M212.1 100.8h15.2M212.1 103.3h15.2"/>
<path d="M212.1 105.9h15.2M212.1 108.4h15.2M212.1 110.9h15.2M212.1 113.5h15.2M212.1 116h15.2M212.1 118.6h15.2M240 101.6v1M240 103.5v1.1M240 105.6v1M240 107.5v1.1M240 109.6v1M240 111.5v1.1"/>
<path d="M240 113.6v1M240 115.6v1M240 117.6v1M240 119.6v1M254.8 106.4h10.6M255.3 108.9h10.1M260.8 114h4.6M260.8 116.5h4.6M260.8 119.1h4.6M261.5 111.5h3.9M265.4 100.8h15.2M265.4 103.3h15.2"/>
<path d="M265.4 108.4h15.2M265.4 110.9h15.2M265.4 113.5h15.2M265.4 116h15.2M265.4 118.6h15.2M273 105.9h7.6M293.3 101.6v1M293.3 103.5v1.1M293.3 105.6v1M293.3 107.5v1.1M293.3 109.6v1M293.3 111.5v1.1"/>
<path d="M293.3 113.6v1M293.3 115.6v1M293.3 117.6v1M293.3 119.6v1M318.7 100.8h15.3M318.7 103.3h15.3M318.7 105.9h15.3M318.7 108.4h15.3M318.7 110.9h15.3M318.7 113.5h15.3M318.7 116h15.3M318.7 118.6h15.3"/>
<path d="M16.5 123.1h3.8M41.5 139.9h14.1l1.5 1.5-1.5 1.5h-14.1zM42.5 129.7h13.1l1.5 1.6-1.5 1.5h-13.1zM43.4 130.1h10.1M45.5 134.8h10.1l1.5 1.5-1.5 1.6h-10.1zM57.1 121.1h53.4M57.1 131.3h53.4M57.1 136.3h53.4M58.3 127.2h22.7l1.5 1.5-1.5 1.5h-22.7zM67.6 132.3h13.4l1.5 1.5-1.5 1.5h-13.4zM67.9 122.1h13.1l1.5 1.5-1.5 1.6h-13.1zM68.9 122.5h10"/>
<path d="M70.9 137.4h10.1l1.5 1.5-1.5 1.5h-10.1zM82.5 123.6h28M82.5 128.7h28M82.5 133.8h28M82.5 138.9h28M104.4 125.2l2 2M105.4 126.2h5.1M106.4 125.2l-2 2M135.9 121.1h22.8M135.9 123.6h5M135.9 126.2h22.8M135.9 128.7h5"/>
<path d="M135.9 131.3h5M135.9 133.8h5M135.9 136.3h5M135.9 138.9h5M139.9 122.6l2.1 2.1M139.9 127.7l2.1 2M139.9 130.2l2.1 2.1M139.9 132.8l2.1 2M139.9 135.3l2.1 2.1M139.9 137.9l2.1 2M142 122.6l-2.1 2.1M142 127.7l-2.1 2"/>
<path d="M142 132.8l-2.1 2M142 137.9l-2.1 2M142 130.2l-2.1 2.1M142 135.3l-2.1 2.1M158.7 121.1l1.6-1.5h9.4v3h-9.4zM160.3 124.7h13.3v3h-13.3l-1.6-1.5zM160.3 125.1h10.3M205.9 139.4h6.2M206.2 124.2h5.9M206.2 126.7h5.9M206.2 129.2h5.9M206.2 131.8h5.9"/>
<path d="M206.2 136.9h5.9M212.1 121.1h15.2M212.1 123.6h15.2M212.1 126.2h15.2M212.1 128.7h15.2M212.1 131.3h15.2M212.1 133.8h15.2M212.1 136.3h15.2M212.1 138.9h15.2M240 121.6v1M240 123.6v1M240 125.6v1"/>
<path d="M240 127.6v1M240 129.6v1M240 131.6v1M240 133.6v1M240 135.6v1M240 137.6v1M240 139.6v1M260.3 121.6h5.1M265.4 121.1h15.2M265.4 123.6h15.2M265.4 126.2h15.2M265.4 128.7h15.2"/>
<path d="M265.4 131.3h15.2M265.4 133.8h15.2M265.4 136.3h15.2M265.4 138.9h15.2M293.3 121.6v1M293.3 123.6v1M293.3 125.6v1M293.3 127.6v1M293.3 129.6v1M293.3 131.6v1M293.3 133.6v1M293.3 135.6v1"/>
<path d="M293.3 137.6v1M293.3 139.6v1M312.9 139.4h5.8M312.9 136.9h5.8M312.9 124.2h5.8M316.1 126.7h2.6M316.4 131.8h2.3M316.9 129.2h1.8M318.7 121.1h15.3M318.7 123.6h15.3M318.7 126.2h15.3M318.7 128.7h15.3"/>
<path d="M318.7 131.3h15.3M318.7 133.8h15.3M318.7 136.3h15.3M318.7 138.9h15.3M400 123.1h3.8M41.5 145h14.1l1.5 1.5-1.5 1.5h-14.1zM46.5 150.1h9.1l1.5 1.5-1.5 1.5h-9.1zM57.1 141.4h53.4M57.1 146.5h53.4M57.1 151.6h53.4M66.9 142.4h14.1l1.5 1.6-1.5 1.5h-14.1zM67.5 152.6h13.5l1.5 1.5-1.5 1.5h-13.5z"/>
<path d="M73 147.5h8l1.5 1.5-1.5 1.6h-8zM73.9 147.9h5M82.5 144h28M82.5 149h28M82.5 154.1h28M135.9 141.4h5M135.9 144h5M135.9 146.5h5M135.9 149h5M135.9 151.6h5M135.9 154.1h5M139.9 140.4l2.1 2"/>
<path d="M139.9 142.9l2.1 2.1M139.9 145.5l2.1 2M139.9 148l2.1 2.1M139.9 150.6l2.1 2M139.9 153.1l2.1 2M142 142.9l-2.1 2.1M142 140.4l-2.1 2M142 145.5l-2.1 2M142 148l-2.1 2.1M142 150.6l-2.1 2M142 153.1l-2.1 2M212.1 141.4h15.2"/>
<path d="M212.1 144h15.2M212.1 146.5h15.2M212.1 149h15.2M212.1 151.6h15.2M212.1 154.1h15.2M212.1 156.7h15.2M212.1 159.2h15.2M240 141.6v1M240 143.6v1M240 145.6v1M240 147.6v1M240 149.6v1"/>
<path d="M240 151.6v1M240 153.6v1M240 155.6v1M240 157.6v1M240 159.6v1M252.9 157.2h12.5M252.9 154.6h12.5M252.9 152.1h12.5M253.6 147h11.8M261.1 159.7h4.3M265.4 141.4h15.2M265.4 144h15.2"/>
<path d="M265.4 149h15.2M265.4 154.1h15.2M265.4 156.7h15.2M265.4 159.2h15.2M273 146.5h7.6M273 151.6h7.6M293.3 141.6v1M293.3 143.6v1M293.3 145.6v1M293.3 147.6v1M293.3 149.6v1M293.3 151.6v1"/>
<path d="M293.3 153.6v1M293.3 155.6v1M293.3 157.6v1M293.3 159.6v1M312.9 141.9h5.8M318.7 141.4h15.3M318.7 144h15.3M318.7 146.5h15.3M318.7 149h15.3M318.7 151.6h15.3M318.7 154.1h15.3M318.7 156.7h15.3"/>
<path d="M318.7 159.2h15.3M16.5 173.7h3.8M202.1 162.3h10M206 167.3h6.1M212.1 161.7h15.2M212.1 164.3h15.2M212.1 166.8h15.2M212.1 169.4h15.2M212.1 171.9h15.2M212.1 174.4h15.2M240 161.6v1M240 163.6v1"/>
<path d="M240 165.6v1M240 167.6v1M240 169.6v1M240 171.6v1M240 173.6v1M240 175.6v1M240 177.6v1M240 179.6v1M265.4 161.7h15.2M265.4 164.3h15.2M265.4 166.8h15.2M265.4 169.4h15.2"/>
<path d="M265.4 171.9h15.2M265.4 174.4h15.2M293.3 161.6v1M293.3 163.6v1M293.3 165.6v1M293.3 167.6v1M293.3 169.6v1M293.3 171.6v1M293.3 173.6v1M293.3 175.6v1M293.3 177.6v1M293.3 179.6v1"/>
<path d="M310.4 167.3h8.3M314.3 164.8h4.4M318.7 161.7h15.3M318.7 164.3h15.3M318.7 166.8h15.3M318.7 169.4h15.3M318.7 171.9h15.3M318.7 174.4h15.3M400 173.7h3.8M240 181.6v1M240 183.6v1h1M242 184.6h1"/>
<path d="M244 184.6h1M246 184.6h1.1M248.1 184.6h1M250.1 184.6h1M252.1 184.6h1M254.1 184.6h1M256.1 184.6h1M258.1 184.6h1M260.1 184.6h1M262.1 184.6h1M264.2 184.6h1M266.2 184.6h1"/>
<path d="M268.2 184.6h1M270.2 184.6h1M272.2 184.6h1M274.2 184.6h1M276.2 184.6h1M278.2 184.6h1.1M280.2 184.6h1.1M282.3 184.6h1M284.3 184.6h1M286.3 184.6h1M288.3 184.6h1M290.3 184.6h1"/>
<path d="M293.3 183.6v1h-1M293.3 181.6v1M153.6 207.5l1.3 1.9M153.6 207.5l-1.2 1.9M153.6 207.5v8.1M153.6 217.1v8.1M163.8 207.5l1.3 1.9M163.8 207.5l-1.3 1.9M163.8 207.5v8.1M163.8 217.1v8.1M172.4 215.1h3.1v.9h-3.1zM174 207.5v7.6"/>
<path d="M174 217.6v7.6M174 207.5l1.2 1.9M174 207.5l-1.3 1.9M182.6 215.1h3.1v.9h-3.1zM184.1 207.5v7.6M184.1 217.6v7.6M184.1 207.5l1.3 1.9M184.1 207.5l-1.2 1.9M16.5 224.2h3.8M151.7 225.2h3.9M161.9 225.2h3.8M172.1 225.2h3.8"/>
<path d="M182.2 225.2h3.8M215.8 225.7h4.5M284.5 225.7h8M400 224.2h3.8M24.1 243h48.3v27.9h-48.3zM28.7 248.1h1M29.2 247.6v1M66.8 248.1h1M67.3 247.6v1M313.6 249.3h86.4M313.6 254.4h86.4M313.6 259.5h86.4"/>
<path d="M372.1 259.5v5.1M28.7 263.3h1M29.2 262.8v1M66.8 263.3h1M67.3 262.8v1M67.8 274.7v3.9M115.2 274.7v3.9M162.7 274.7v3.9M210.2 274.7v3.9M253.9 268.4l.5 .1M253.9 268.4h.4M253.9 268.3h.4"/>
<path d="M253.9 268.2h.4M253.9 268.1h.4M253.9 268h.4M253.9 267.9h.4M253.9 267.8h.4M253.9 267.7h.4M254 268.5l.4 .1M254 268.5h.4M254 268.6h.5M254 268.7h1.3M254 267.3h1.3M254.1 268.8h1.2"/>
<path d="M254.1 267.3h1.2M254.1 268.9h1.1M254.1 267.2h1.1M254.2 267.1h1M254.3 269h.8M254.3 267.1h.8M254.3 269h.7M254.3 267.6l-.4 .1M254.4 267.5l-.4 .1M254.4 267.5h-.4M254.4 267h.5M254.5 267.4l-.5 .1"/>
<path d="M254.5 269.1h.3M254.8 267.4h.6M254.9 267.5h.5M255 268.5h.4M255 267.5h.4M255 267.6h.4M255 268.4h.4M255 268.3h.4M255 268.2h.4M255 268.1h.4M255 268h.4M255 267.9h.4"/>
<path d="M255 267.8h.4M255 267.7h.4M255.2 268.9h-1M255.3 267.4h-1.3M255.4 268.6h-.6M255.4 268.6h-.5M255.9 269.5h.3M255.9 269.4h.3M255.9 269.3h.3M255.9 269.2h.3M255.9 269.1h.3M255.9 268.7h1.4"/>
<path d="M255.9 268.6h.5M255.9 268.5l.4 .1M255.9 268.5h.4M255.9 268.4h.3M255.9 268.3h.3M255.9 268.2h.3M255.9 268.1h.3M255.9 268h.3M255.9 267.9h.3M255.9 267.8h.3M255.9 267.7h.3M255.9 267.6h.3"/>
<path d="M255.9 269.8h.1M255.9 267.4h1.4M255.9 267.3h1.3M256 267.3h1.2M256 267.2h1.1M256.1 267.1h1M256.1 269.7l-.2 .1M256.2 267.1h.8M256.2 269.7h-.3M256.2 269.6h-.3M256.3 267.5l-.4 .1M256.3 267.5h-.4"/>
<path d="M256.3 267h.6M256.4 267.4h-.5M256.5 269.1h.2M256.8 267.4l.5 .1M256.9 267.5h.4M256.9 267.5l.4 .1M256.9 269l-1 .1M256.9 268.4h.4M256.9 267.7h.4M256.9 267.6h.4M256.9 268.3h.4M256.9 268.2h.4"/>
<path d="M256.9 268.1h.4M256.9 268h.4M256.9 267.9h.4M256.9 267.8h.4M257 269h-1.1M257.1 268.9l-1.2 .1M257.1 268.9h-1.2M257.2 268.8h-1.3M257.2 268.7l-1.3 .1M257.3 268.6h-.5M257.3 268.6h-.4M257.3 268.5h-.4"/>
<path d="M257.6 274.7v3.9M257.8 268.5h.4M257.8 268.4l.4 .1M257.8 267.9h1.4M257.8 267.8l.3 .1M257.8 267.8h.3M257.8 267.7h.3M257.8 267.5h.4M257.8 268.6h.5M257.8 268.5l.5 .1M257.8 268.7h1.3M257.9 267.3h1.2"/>
<path d="M257.9 268.8h1.2M258 267.2h1M258 267.1h1M258.1 269h.8M258.1 267.1h.8M258.1 269h.7M258.2 267.6h-.4M258.2 267h.6M258.3 268.4h-.5M258.3 267.5h-.5M258.3 267.9h.9M258.3 267.4l-.5 .1"/>
<path d="M258.4 269.1h.2M258.4 268.3h-.6M258.4 267.8h.8M258.5 268.2l-.7 .1M258.6 267.8h.6M258.7 268.2h-.9M258.7 267.7h.5M258.7 267.4h.5M258.7 267.5h.5M258.8 268.6h.4M258.8 267.7h.4M258.8 267.5h.4"/>
<path d="M258.8 268.5h.4M258.8 268.1h-1M258.8 268.4h.4M258.8 268.3h.4M258.9 268.3h.3M258.9 268l-1.1 .1M259 268.9h-1M259 268.2h.2M259.1 268h-1.3M259.1 268.7l-1.2 .1M259.2 267.4h-1.4M259.2 268.6h-.5"/>
<path d="M259.7 269h.2M259.7 268.9h.4M259.7 268.8h.4M259.7 268.7h.4M259.7 268.6h.4M259.7 268.5h.4M259.7 268.4h.4M259.7 268.3h.4M259.7 268.2h.4M259.7 268.1h.4M259.7 268h.4M259.7 267.9h.4"/>
<path d="M259.7 267.8h.4M259.7 267.7h.4M259.8 267.3h1.2M259.9 267.2h1.1M259.9 267.1h1M260 269h-.3M260 267.1h.8M260.1 268.9l-.4 .1M260.1 267.6h-.4M260.1 267.5l-.4 .1M260.2 267.5h-.5M260.2 267h.5"/>
<path d="M260.2 267.4l-.5 .1M260.6 267.4l.5 .1M260.7 267.5h.4M260.8 269h.2M260.8 268.9h.4M260.8 268.8h.4M260.8 268.7h.4M260.8 268.6h.4M260.8 268.5h.4M260.8 268.4h.4M260.8 268.3h.4M260.8 268.2h.4"/>
<path d="M260.8 268.1h.4M260.8 268h.4M260.8 267.9h.4M260.8 267.8h.4M260.8 267.7h.4M260.8 267.6h.4M261.1 269h-.3M261.1 267.4h-1.4M261.2 268.9l-.4 .1M262.8 266.6h.3M262.8 269.1h.1M262.8 268.9h.3"/>
<path d="M262.8 268.8h.3M262.8 268.7h.3M262.8 268.6h.3M262.8 268.5h.3M262.8 268.4h.3M262.8 268.3h.3M262.8 268.2h.3M262.8 268.1h.3M262.8 268h.3M262.8 267.9h.3M262.8 267.8h.3M262.8 267.7h.3"/>
<path d="M262.8 267.3h1.2M262.8 267.2l1.1 .1M262.8 267.2h1M262.8 267.1h.3M262.8 267h.3M262.8 266.9h.3M262.8 266.8h.3M262.8 266.7h.3M262.8 266.5h.3M262.9 266.5h.2M263 269l-.2 .1M263.1 269h-.3"/>
<path d="M263.1 267.7l-.3 .1M263.1 267.6h-.3M263.2 267.5l-.4 .1M263.2 267.5h-.4M263.2 267.1h.5M263.4 267.4h-.6M263.6 267.4l.5 .1M263.7 267.5h.4M263.8 267.5h.3M263.8 267.6h.3M263.9 267.8h.3M263.9 267.7h.3"/>
<path d="M263.9 269.1h.1M263.9 268.9h.3M263.9 268.8h.3M263.9 268.7h.3M263.9 268.6h.3M263.9 268.5h.3M263.9 268.4h.3M263.9 268.3h.3M263.9 268.2h.3M263.9 268.1h.3M263.9 268h.3M263.9 267.9h.3"/>
<path d="M264 267.4h-1.2M264.1 269l-.2 .1M264.1 269h-.2M264.2 268.9h-.3M264.6 268.7h.4M264.6 268.6h.3M264.6 267.7h.3M264.6 268.7l.4 .1M264.6 267.9h.1M264.6 268.8h.9M264.7 268.9h.8M264.7 267.4h1.2"/>
<path d="M264.8 269h.7M264.8 267.3h1M264.9 268.1h1.1M264.9 267.8l-.3 .1M264.9 267.3h.8M264.9 267.8h-.3M264.9 268.5l-.3 .1M264.9 267.7h-.3M264.9 267.2h.8M264.9 268.5h-.3M264.9 267.6h-.3M265 269.1h.5"/>
<path d="M265 268.4l-.4 .1M265 267.5l-.4 .1M265 268.1h1M265 267.5h-.3M265 267.1h.6M265.1 268.4h-.5M265.2 268h.8M265.2 269.1h.1M265.2 267.4l-.5 .1M265.3 268.3h-.7M265.3 267.9h.7M265.4 268.2l-.7 .1"/>
<path d="M265.4 267.4h.5M265.5 267.9h.5M265.5 267.5h.4M265.6 268.2h-.8M265.6 267.5l.4 .1M265.6 267.8h.4M265.6 268.2h.4M265.6 267.6h.4M265.7 267.7h.3M265.7 269.1h.1M265.7 268.9h.3M265.7 268.8h.3"/>
<path d="M265.7 268.7h.3M265.7 268.6h.3M265.7 268.5h.3M265.7 268.4h.3M265.7 268.3h.3M265.7 268.2h.3M266 269l-.3 .1M266 269h-.3M266.4 269.1h.1M266.4 268.9h.3M266.4 268.8h.3M266.4 268.7h.3"/>
<path d="M266.4 268.6h.3M266.4 268.5h.3M266.4 268.4h.3M266.4 268.3h.3M266.4 268.2h.3M266.4 268.1h.3M266.4 268h.3M266.4 267.9h.3M266.4 267.8h.3M266.4 267.7h.3M266.6 267.3h1M266.6 267.3h.9"/>
<path d="M266.7 269l-.3 .1M266.7 269h-.3M266.7 268.9l-.3 .1M266.7 267.2h.8M266.8 267.6h-.4M266.8 267.5l-.4 .1M266.8 267.1h.6M266.9 267.5h-.4M267 267.4h-.5M267.2 267.4h.5M267.3 267.5h.4M267.4 267.5h.4"/>
<path d="M267.4 267.6h.4M267.5 267.7h.3M267.5 267.8h.2M267.7 267.4h-1.2M267.8 267.8h-.3M268.2 268.4h.3M268.2 268.3h.3M268.2 268.2h.3M268.2 268.1h.3M268.2 268h.3M268.2 267.9h.3M268.2 267.8h.3"/>
<path d="M268.2 268.5h.3M268.2 267.7h.3M268.2 268.6h.4M268.2 268.5l.3 .1M268.3 268.7h.3M268.3 268.7l.4 .1M268.3 268.8h1.2M268.4 268.9h1.1M268.4 267.3h1.2M268.4 268.9h1M268.5 267.3h1.1M268.5 269h.8"/>
<path d="M268.5 267.2h1.1M268.6 267.6l-.4 .1M268.6 267.5l-.3 .1M268.6 269.1h.6M268.6 267.1h.6M268.7 267.5h-.4M268.8 267.4l-.5 .1M268.8 269.1h.1M268.9 269.1h.1M269 267.4h.6M269.2 267.5h.4M269.3 267.6h.3"/>
<path d="M269.3 268.5h.3M269.3 268.4h.3M269.3 268.3h.3M269.3 268.2h.3M269.3 268.1h.3M269.3 268h.3M269.3 267.9h.3M269.3 267.8h.3M269.3 267.7h.3M269.3 267.1h.3M269.3 267h.3M269.3 266.9h.3"/>
<path d="M269.3 266.8h.3M269.3 266.7h.3M269.3 266.6h.3M269.3 266.5h.3M269.3 269h-.8M269.4 266.5h.2M269.5 268.8h-.4M269.6 268.7h-.4M269.6 268.6h-.4M269.6 268.5l-.3 .1M269.6 267.4h-1.2M269.9 268.6h.3"/>
<path d="M269.9 268.5h.3M269.9 268.4h.3M269.9 268.3h.3M269.9 268.2h.3M269.9 268.1h.3M269.9 268h.3M269.9 267.9h.3M269.9 267.8h.3M269.9 267.7h.3M269.9 267.6h.3M269.9 267.5h.3M269.9 267.4h.3"/>
<path d="M269.9 267.3h.3M269.9 268.8h1.6M269.9 268.7l.3 .1M269.9 268.7h.3M269.9 268.9h1.6M269.9 267.2h.3M270 268.9h1.5M270 269h1.4M270 267.1h.2M270.2 269.1h.4M270.4 269.1h.1M270.5 268.8h.4"/>
<path d="M270.6 268.7h.3M270.6 268.6h.3M270.6 268.5h.3M270.6 268.4h.3M270.6 268.3h.3M270.6 268.2h.3M270.6 268.1h.3M270.6 268h.3M270.6 267.9h.3M270.6 267.8h.3M270.6 267.7h.3M270.6 267.6h.3"/>
<path d="M270.6 267.5h.3M270.6 267.4h.3M270.6 267.3h.3M270.6 267.2h.3M270.7 267.1h.2M270.8 269.1h.5M271.3 268.7h.3M271.3 268.6h.3M271.3 268.5h.3M271.3 268.4h.3M271.3 268.3h.3M271.3 268.2h.3"/>
<path d="M271.3 268.1h.3M271.3 268h.3M271.3 267.9h.3M271.3 267.8h.3M271.3 267.7h.3M271.3 267.6h.3M271.3 267.5h.3M271.3 267.4h.3M271.3 267.3h.3M271.3 267.2h.3M271.4 267.1h.1M271.6 268.7l-.4 .1"/>
<path d="M271.8 268.7h.4M271.8 268.6h.4M271.8 268.5h.4M271.9 268.7l.3 .1M271.9 267.9h.1M271.9 267.7h.2M271.9 268.8h.8M271.9 268.9h.8M272 268.9h.8M272 267.3h1.1M272.1 269h.7M272.1 267.8l-.2 .1"/>
<path d="M272.1 267.3h.9M272.1 267.8h-.2M272.2 267.7h-.3M272.2 268.5h-.4M272.2 267.6h-.3M272.2 267.2h.7M272.2 269.1h.5M272.2 268.4l-.3 .1M272.2 268.1h1M272.2 267.5l-.3 .1M272.3 267.1h.5M272.3 267.5h-.4"/>
<path d="M272.4 268.4h-.5M272.4 268h.8M272.4 267.4l-.5 .1M272.5 268.3h-.6M272.6 267.9h.6M272.6 267.4l.6 .1M272.6 268.2l-.7 .1M272.7 267.9h.5M272.8 267.5h.4M272.8 268.2h-.8M272.8 267.5l.4 .1M272.9 267.8h.3"/>
<path d="M272.9 267.6h.3M272.9 268.2h.3M272.9 267.7h.3M272.9 269.1h.1M272.9 269h.3M272.9 268.9h.3M272.9 268.8h.3M272.9 268.7h.3M272.9 268.6h.3M272.9 268.5h.3M272.9 268.4h.3M272.9 268.3h.3"/>
<path d="M273.1 267.4h-1.1M273.2 269l-.3 .1M273.2 268.1h-1.1M273.7 269.1h.1M273.7 268.9h.2M273.7 268.8h.2M273.7 268.7h.2M273.7 268.6h.2M273.7 268.5h.2M273.7 268.4h.2M273.7 268.3h.2M273.7 268.2h.2"/>
<path d="M273.7 268.1h.2M273.7 268h.2M273.7 267.9h.2M273.7 267.8h.2M273.7 267.7h.3M273.7 267.5h.3M273.8 267.4h1.1M273.8 267.3h1.1M273.9 267.3h.9M273.9 269l-.2 .1M273.9 269h-.2M274 267.2h.7"/>
<path d="M274 267.6h-.3M274.1 267.1h.5M274.1 267.5h-.4M274.3 267.4l-.6 .1M274.4 267.4l.6 .1M274.6 267.5h.4M274.7 267.5l.3 .1M274.7 267.6h.3M274.7 267.7h.3M274.9 267.8l-.2 .1M275 267.8h-.3M275.5 268.6h.3"/>
<path d="M275.5 268.5l.3 .1M275.5 268.5h.3M275.5 268h1.1M275.5 268h.3M275.5 267.9h.3M275.5 267.8h.3M275.5 267.7h.3M275.5 267.6h.3M275.5 268.7h.4M275.5 268.7l.4 .1M275.6 268.8h1.1M275.6 267.4h1.1"/>
<path d="M275.6 268.9h1.1M275.7 268.9h.9M275.7 267.3h1M275.7 267.3h.9M275.7 269h.9M275.8 269h.7M275.8 267.2h.7M275.8 267.7h-.3M275.8 268.4h-.3M275.9 267.5l-.4 .1M275.9 269.1h.5M275.9 267.1h.5"/>
<path d="M275.9 267.5h-.4M276 268.4h-.5M276.1 267.4l-.5 .1M276.1 268.3h-.6M276.1 269.1h.1M276.2 268.2l-.7 .1M276.2 267.9h.6M276.2 267.4l.6 .1M276.4 268.2h-.9M276.4 267.8h.4M276.4 267.5h.4M276.5 267.5h.3"/>
<path d="M276.5 268.6h.3M276.5 267.6h.3M276.5 267.8h.3M276.5 267.7h.3M276.5 268.1h-1M276.6 268.5h.2M276.6 268.4h.2M276.7 268.3h.1M276.8 268.8h-.4M276.8 268h-.8M276.8 268.7h-.4M276.8 268.6h-.3"/>
<path d="M276.8 267.9h-.7M305.1 274.7v3.9M313.6 264.6h86.4M313.6 269.7h86.4M352.6 274.7v3.9M400 274.6h.1"/>
<circle cx="29.2" cy="248.1" r="2.03"/>
<circle cx="29.2" cy="248.1" r=".51"/>
<circle cx="67.3" cy="248.1" r="2.03"/>
<circle cx="67.3" cy="248.1" r=".51"/>
<circle cx="29.2" cy="263.3" r="2.03"/>
<circle cx="29.2" cy="263.3" r=".51"/>
<circle cx="67.3" cy="263.3" r="2.03"/>
<circle cx="67.3" cy="263.3" r=".51"/>
</g>
<g fill="none" stroke="#000" stroke-width=".42">
<path d="M85.1 91.9h22.8v8.9h-22.8zM140.9 91.9h12.7v8.9h-12.7zM226 93.2h5.1v83.8h-5.1zM279.4 93.2h5v83.8h-5zM332.7 93.2h5.1v83.8h-5.1z"/>
<circle cx="90.2" cy="93.2" r=".25"/>
<circle cx="92.7" cy="93.2" r=".25"/>
<circle cx="95.2" cy="93.2" r=".25"/>
<circle cx="97.8" cy="93.2" r=".25"/>
<circle cx="100.3" cy="93.2" r=".25"/>
<circle cx="102.9" cy="93.2" r=".25"/>
<circle cx="105.4" cy="93.2" r=".25"/>
<circle cx="146" cy="93.2" r=".25"/>
<circle cx="148.6" cy="93.2" r=".25"/>
<circle cx="151.1" cy="93.2" r=".25"/>
</g>
<g fill="none" stroke="#000" stroke-width=".61">
<path d="M20.3 22.1h379.7v252.6h-379.7zM227.3 98.3h1.3M227.3 95.7h1.3M280.6 98.3h1.3M280.6 95.7h1.3M334 98.3h1.2M334 95.7h1.2M227.3 118.6h1.3M227.3 116h1.3M227.3 113.5h1.3M227.3 110.9h1.3M227.3 108.4h1.3"/>
<path d="M227.3 105.9h1.3M227.3 103.3h1.3M227.3 100.8h1.3M280.6 118.6h1.3M280.6 116h1.3M280.6 113.5h1.3M280.6 110.9h1.3M280.6 108.4h1.3M280.6 105.9h1.3M280.6 103.3h1.3M280.6 100.8h1.3M334 118.6h1.2"/>
<path d="M334 116h1.2M334 113.5h1.2M334 110.9h1.2M334 108.4h1.2M334 105.9h1.2M334 103.3h1.2M334 100.8h1.2M227.3 138.9h1.3M227.3 136.3h1.3M227.3 133.8h1.3M227.3 131.3h1.3M227.3 128.7h1.3"/>
<path d="M227.3 126.2h1.3M227.3 123.6h1.3M227.3 121.1h1.3M280.6 138.9h1.3M280.6 136.3h1.3M280.6 133.8h1.3M280.6 131.3h1.3M280.6 128.7h1.3M280.6 126.2h1.3M280.6 123.6h1.3M280.6 121.1h1.3M334 138.9h1.2"/>
<path d="M334 136.3h1.2M334 133.8h1.2M334 131.3h1.2M334 128.7h1.2M334 126.2h1.2M334 123.6h1.2M334 121.1h1.2M227.3 159.2h1.3M227.3 156.7h1.3M227.3 154.1h1.3M227.3 151.6h1.3M227.3 149h1.3"/>
<path d="M227.3 146.5h1.3M227.3 144h1.3M227.3 141.4h1.3M280.6 159.2h1.3M280.6 156.7h1.3M280.6 154.1h1.3M280.6 151.6h1.3M280.6 149h1.3M280.6 146.5h1.3M280.6 144h1.3M280.6 141.4h1.3M334 159.2h1.2"/>
<path d="M334 156.7h1.2M334 154.1h1.2M334 151.6h1.2M334 149h1.2M334 146.5h1.2M334 144h1.2M334 141.4h1.2M227.3 174.4h1.3M227.3 171.9h1.3M227.3 169.4h1.3M227.3 166.8h1.3M227.3 164.3h1.3"/>
<path d="M227.3 161.7h1.3M280.6 174.4h1.3M280.6 171.9h1.3M280.6 169.4h1.3M280.6 166.8h1.3M280.6 164.3h1.3M280.6 161.7h1.3M334 174.4h1.2M334 171.9h1.2M334 169.4h1.2M334 166.8h1.2M334 164.3h1.2"/>
<path d="M334 161.7h1.2M313.6 244.3v30.4M400 244.3h-116.8v30.4"/>
</g>
<path d="M16.5 18.2h387.3v260.4h-387.3z" fill="none" stroke="#000" stroke-width=".32"/>
<g fill="#000" stroke="#000" stroke-width=".25">
<path d="M110.2 105.6h2.8v.5h-2.8zM110.2 108.1h2.8v.5h-2.8zM110.2 110.7h2.8v.5h-2.8zM110.2 113.2h2.8v.5h-2.8zM110.2 115.8h2.8v.5h-2.8zM110.2 118.3h2.8v.5h-2.8zM133.3 105.6h2.8v.5h-2.8zM133.3 108.1h2.8v.5h-2.8zM133.3 110.7h2.8v.5h-2.8zM133.3 113.2h2.8v.5h-2.8zM133.3 115.8h2.8v.5h-2.8zM133.3 118.3h2.8v.5h-2.8z"/>
<path d="M110.2 120.8h2.8v.5h-2.8zM110.2 123.4h2.8v.5h-2.8zM110.2 125.9h2.8v.5h-2.8zM110.2 128.5h2.8v.5h-2.8zM110.2 131h2.8v.5h-2.8zM110.2 133.5h2.8v.5h-2.8zM110.2 136.1h2.8v.5h-2.8zM110.2 138.6h2.8v.5h-2.8zM133.3 120.8h2.8v.5h-2.8zM133.3 123.4h2.8v.5h-2.8zM133.3 125.9h2.8v.5h-2.8zM133.3 128.5h2.8v.5h-2.8z"/>
<path d="M133.3 131h2.8v.5h-2.8zM133.3 133.5h2.8v.5h-2.8zM133.3 136.1h2.8v.5h-2.8zM133.3 138.6h2.8v.5h-2.8zM110.2 141.2h2.8v.5h-2.8zM110.2 143.7h2.8v.5h-2.8zM110.2 146.2h2.8v.5h-2.8zM110.2 148.8h2.8v.5h-2.8zM110.2 151.3h2.8v.5h-2.8zM110.2 153.9h2.8v.5h-2.8zM133.3 141.2h2.8v.5h-2.8zM133.3 143.7h2.8v.5h-2.8z"/>
<path d="M133.3 146.2h2.8v.5h-2.8zM133.3 148.8h2.8v.5h-2.8zM133.3 151.3h2.8v.5h-2.8zM133.3 153.9h2.8v.5h-2.8zM151.6 216.6h4.1v.5h-4.1zM151.6 215.6h4.1v.5h-4.1zM161.8 216.6h4v.5h-4zM161.8 215.6h4v.5h-4zM172.3 216.7h3.3v.9h-3.3zM182.5 216.7h3.3v.9h-3.3zM151.6 225h4.1v.5h-4.1zM161.8 225h4v.5h-4z"/>
<path d="M171.9 225h4.1v.5h-4.1zM182.1 225h4.1v.5h-4.1z"/>
</g>
<g fill="none" stroke="#000" stroke-width=".38">
<path d="M260.9 257.3l1.2 1.4-.5 1.2-1.9 .2v1.4M260.9 257.3h2.2M261.2 257.6h8.4M261.3 256.9h1.4M261.5 258h7.8M261.6 256.6h.6M261.6 259.7h2.4M261.7 259.4h2.6M261.7 258.3h7.3M261.9 259h7M262 258.7h6.8M263.7 257.3h3.4"/>
<path d="M263.7 257.2l.8-.3 .2-1.8h1.4l.2 1.8 .8 .3M263.7 257.2l-.4 .3-1.4-1.2-1 1M264 259.7l-.4 1.1M264.5 256.9h1.8M264.6 256.6h1.6M264.6 256.2h1.6M264.6 255.9h1.6M264.7 255.5h1.4M264.7 255.2h1.4M265.3 259l-.9 .3-.4 .4M265.6 259l.5 .1 .7 .6M266.5 259.4h2.5"/>
<path d="M266.8 259.7l.3 .5 .1 .9M266.8 259.7h2.4M267.1 257.2l.4 .3 1.4-1.2 1 1M267.7 257.3h2.2M268.1 256.9h1.5M268.6 256.6h.6M269.9 257.3l-1.2 1.4 .5 1.2 1.9 .2v1.4M259.7 261.5l1.9 .2 .3 .8M259.7 261.5h4.1M259.7 261.1h4M259.7 260.8h3.9M259.7 260.4h4"/>
<path d="M260.1 260.1h3.7M260.9 264.2h2.3M261.2 264.6h1.5M261.2 263.9h2.9M261.5 263.5h2.8M261.5 264.9h.8M261.6 261.8h2.3M261.7 262.1h2.6M261.8 263.2h2.6M261.9 262.5l.2 .3M261.9 262.5h2.8M262.1 262.8h2.4"/>
<path d="M263.5 264.2h.5M263.6 260.8v.3M263.6 261.1l.4 .8 .7 .5-.8 2-.6-.3-1.4 1.2-1-1 1.2-1.5M266.1 262.5h2.8M266.3 262.8h2.4M266.4 263.2h2.6M266.6 263.5h2.7M266.6 262.1h2.5M266.7 263.9h2.9M266.8 264.2h.5M266.9 261.8h2.3M267 260.1h3.7"/>
<path d="M267.1 261.5h4M267.1 260.4h4M267.2 261.1l-.4 .8-.7 .5 .8 2 .6-.3 1.4 1.2 1-1-1.2-1.5M267.2 261.1h3.9M267.2 260.8h3.9M267.6 264.2h2.3M268.1 264.6h1.5M268.5 264.9h.8M268.9 262.5l-.2 .3M271.1 261.5l-1.9 .2-.3 .8"/>
</g>
<g fill="#000" stroke="#000" stroke-width=".25">
<path d="M27.2 248.1h1.5l.2 .4 .3 .1v1.5a2 2 0 0 1-2-2z" fill-rule="evenodd"/>
<path d="M29.2 246a2.04 2.04 0 0 1 2 2.1h-1.5l-.1-.3-.4-.2z" fill-rule="evenodd"/>
<path d="M65.7 246.8l.6-.5 1-.3v1.6l-.4 .2-.1 .3h-1.5v-.6z" fill-rule="evenodd"/>
<path d="M67.3 248.6l.3-.1 .2-.4h1.5a2.04 2.04 0 0 1-2 2z" fill-rule="evenodd"/>
<path d="M27.2 263.3h1.5l.2 .4 .3 .1v1.5a2 2 0 0 1-2-2z" fill-rule="evenodd"/>
<path d="M29.2 261.3a2.04 2.04 0 0 1 2 2h-1.5l-.1-.3-.4-.2z" fill-rule="evenodd"/>
<path d="M65.7 262l.6-.5 1-.2v1.5l-.4 .2-.1 .3h-1.5v-.6z" fill-rule="evenodd"/>
<path d="M67.8 263.3h1.5a2.04 2.04 0 0 1-2 2v-1.5l.3-.1z" fill-rule="evenodd"/>
<circle cx="87.6" cy="128.7" r=".51"/>
<circle cx="90.2" cy="131.3" r=".51"/>
<circle cx="92.7" cy="133.8" r=".51"/>
<circle cx="95.2" cy="136.3" r=".51"/>
<circle cx="97.8" cy="138.9" r=".51"/>
<circle cx="151.1" cy="121.1" r=".51"/>
</g>
<use href="#words"/>
</svg>
